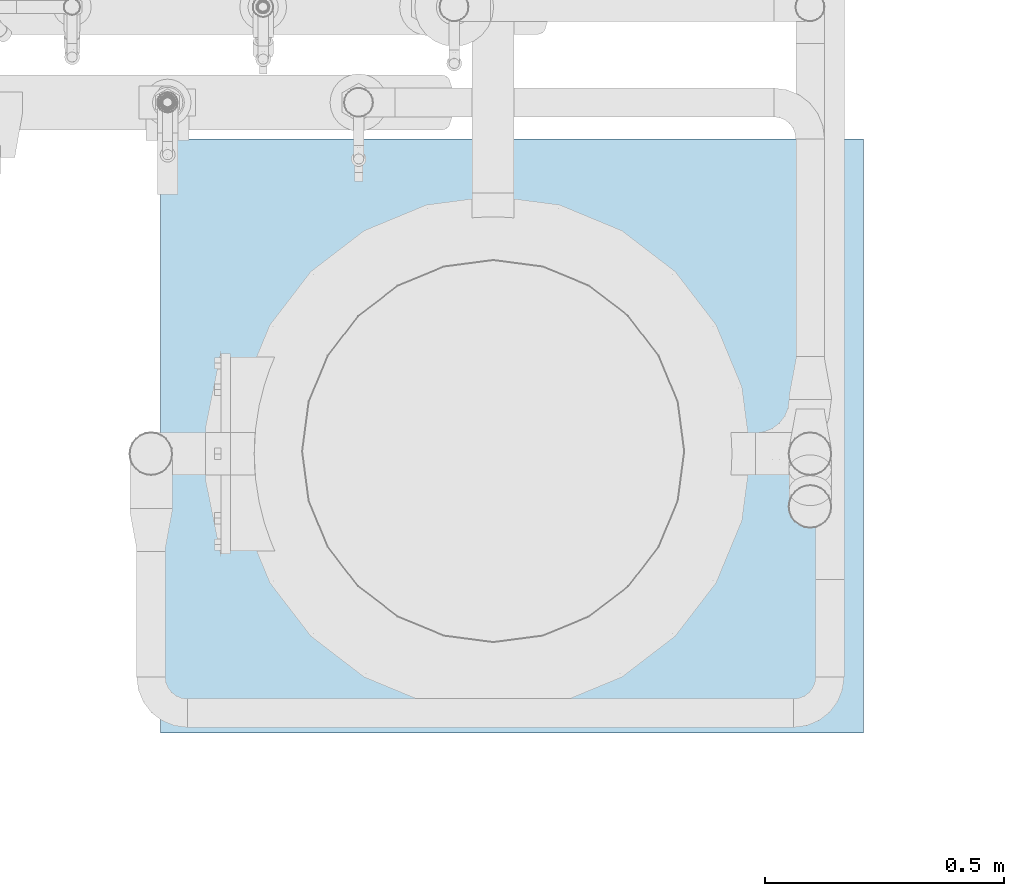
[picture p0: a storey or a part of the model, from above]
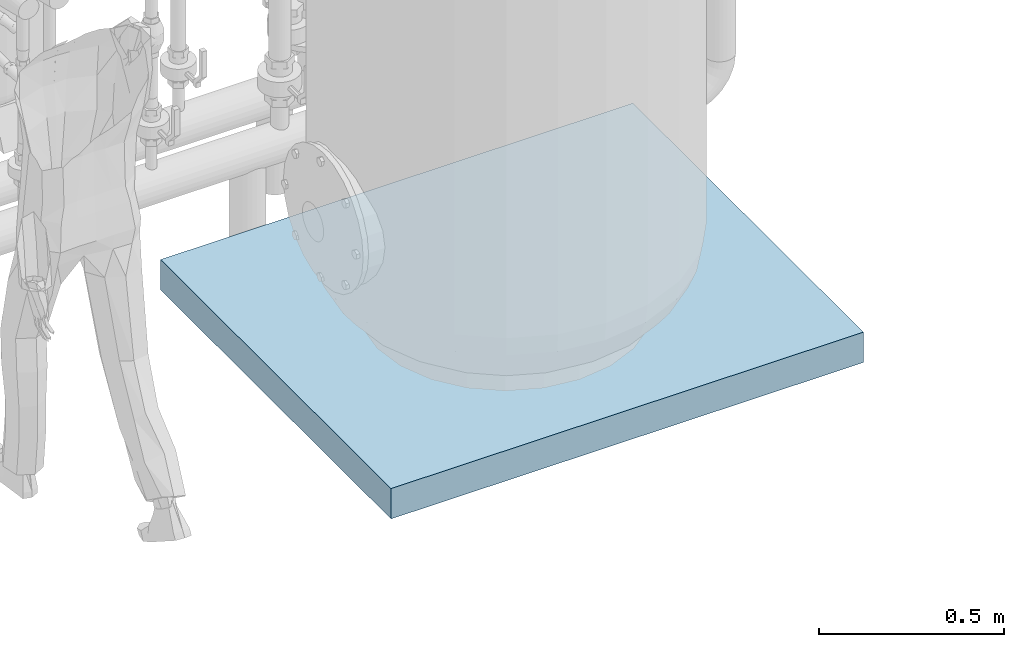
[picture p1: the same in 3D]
Properties of the parts of a building model (IFC2X3), part 1 of 4

# File
Description: ViewDefinition [CoordinationView_V2.0]
File name: Plancal nova.ifc
Time: 2015-04-08T17:33:02+02:00
Written by: Plancal nova (Build = 11.0.0.7, Compile = Apr 1 2015)
Made in: Plancal nova (Build = 11.0.0.7, Compile = Apr 1 2015)

# IfcSite, Site 1
RefLatitude: 50, 43, 8; RefLongitude: 7, 8, 56; RefElevation: 60 m

# IfcBuildingStorey (6)
In: Undefined
Name | Elevation (m)

Toiture | 17.4
R+2 | 13.45
Mezzannine | 9.425
R+1 | 5.4
Rez de chaussŽe | 0

# IfcBuildingElementProxy (54)
Name | In | Description | Group
BuildingElementProxy 1 | Toiture | Cube | Géométrie
BuildingElementProxy 2 | R+2 | Cloison
BuildingElementProxy 3 | R+2 | Cloison
BuildingElementProxy 4 | R+2 | Cloison
BuildingElementProxy 5 | R+2 | Cloison
BuildingElementProxy 6 | Mezzannine | Cloison
BuildingElementProxy 7 | Mezzannine | Cloison
BuildingElementProxy 8 | Mezzannine | Cloison
BuildingElementProxy 9 | Mezzannine | Cloison
BuildingElementProxy 10 | R+1 | Cloison
BuildingElementProxy 11 | R+1 | Cloison
BuildingElementProxy 12 | R+1 | Cloison
BuildingElementProxy 13 | R+1 | Cloison
BuildingElementProxy 14 | Rez de chaussŽe | IfcBuildingElementProxy | Géométrie
BuildingElementProxy 15 | Rez de chaussŽe | IfcBuildingElementProxy | Géométrie
BuildingElementProxy 16 | Rez de chaussŽe | IfcBuildingElementProxy | Géométrie
BuildingElementProxy 17 | Rez de chaussŽe | IfcBuildingElementProxy | Géométrie
BuildingElementProxy 18 | Rez de chaussŽe | IfcBuildingElementProxy | Géométrie
BuildingElementProxy 19 | Rez de chaussŽe | IfcBuildingElementProxy | Géométrie
BuildingElementProxy 20 | Rez de chaussŽe | IfcBuildingElementProxy | Géométrie
BuildingElementProxy 21 | Rez de chaussŽe | IfcBuildingElementProxy | Géométrie
BuildingElementProxy 22 | Rez de chaussŽe | IfcBuildingElementProxy | Géométrie
BuildingElementProxy 23 | Rez de chaussŽe | IfcBuildingElementProxy | Géométrie
BuildingElementProxy 24 | Rez de chaussŽe | IfcBuildingElementProxy | Géométrie
BuildingElementProxy 25 | Rez de chaussŽe | IfcBuildingElementProxy | Géométrie
BuildingElementProxy 26 | Rez de chaussŽe | IfcBuildingElementProxy | Géométrie
BuildingElementProxy 27 | Rez de chaussŽe | IfcBuildingElementProxy | Géométrie
BuildingElementProxy 28 | Rez de chaussŽe | IfcBuildingElementProxy | Géométrie
BuildingElementProxy 29 | Rez de chaussŽe | IfcBuildingElementProxy | Géométrie
BuildingElementProxy 30 | Rez de chaussŽe | IfcBuildingElementProxy | Géométrie
BuildingElementProxy 31 | Rez de chaussŽe | IfcBuildingElementProxy | Géométrie
BuildingElementProxy 32 | Rez de chaussŽe | IfcBuildingElementProxy | Géométrie
BuildingElementProxy 33 | Rez de chaussŽe | IfcBuildingElementProxy | Géométrie
BuildingElementProxy 34 | Rez de chaussŽe | IfcBuildingElementProxy | Géométrie
BuildingElementProxy 35 | Rez de chaussŽe | IfcBuildingElementProxy | Géométrie
BuildingElementProxy 36 | Rez de chaussŽe | IfcBuildingElementProxy | Géométrie
BuildingElementProxy 37 | Rez de chaussŽe | IfcBuildingElementProxy | Géométrie
BuildingElementProxy 38 | Rez de chaussŽe | IfcBuildingElementProxy | Géométrie
BuildingElementProxy 39 | Rez de chaussŽe | IfcBuildingElementProxy | Géométrie
BuildingElementProxy 40 | Rez de chaussŽe | IfcBuildingElementProxy | Géométrie
BuildingElementProxy 41 | Rez de chaussŽe | IfcBuildingElementProxy | Géométrie
BuildingElementProxy 42 | Rez de chaussŽe | IfcBuildingElementProxy | Géométrie
BuildingElementProxy 43 | Rez de chaussŽe | IfcBuildingElementProxy | Géométrie
BuildingElementProxy 44 | Rez de chaussŽe | IfcBuildingElementProxy | Géométrie
BuildingElementProxy 45 | Rez de chaussŽe | IfcBuildingElementProxy | Géométrie
BuildingElementProxy 46 | Rez de chaussŽe | IfcBuildingElementProxy | Géométrie
BuildingElementProxy 47 | Rez de chaussŽe | IfcBuildingElementProxy | Géométrie
BuildingElementProxy 48 | Rez de chaussŽe | IfcBuildingElementProxy | Géométrie
BuildingElementProxy 49 | Rez de chaussŽe | IfcBuildingElementProxy | Géométrie
BuildingElementProxy 50 | Rez de chaussŽe | IfcBuildingElementProxy | Géométrie
BuildingElementProxy 51 | Rez de chaussŽe | Cloison
BuildingElementProxy 52 | Rez de chaussŽe | Cloison
BuildingElementProxy 53 | Rez de chaussŽe | Cloison
BuildingElementProxy 54 | Rez de chaussŽe | Cloison

# IfcDistributionControlElement: Compteur d'eau (3)
In: Rez de chaussŽe
Description: Compteur d'eau
Pset Plancal nova - MEP - Tech-Type de connection (filetage=2, bride=3): 3; Nom: Compteur d'eau; Tech-PN: 16; Tech-Epaisseur isolant (m): 0 m
Name | Geom-Ø exterieur (m) (m) | Geom-DN | Geom-Longueur (m) (m) | Group
Compteur d'eau | 0.185 | 65 | 0.185 | Eau froide
Compteur d'eau | 0.105 | 20 | 0.13 | Aller
Compteur d'eau | 0.115 | 25 | 0.13 | Aller

# IfcDistributionControlElement: Thermomètre droit (12)
In: Rez de chaussŽe
Description: Thermomètre droit
Pset Plancal nova - MEP - Nom: Thermomètre droit; Tech-Epaisseur isolant (m): 0 m
Name | Group
6 x Thermomètre droit | Aller
6 x Thermomètre droit | Retour

# IfcDistributionControlElement: Thermomètre droit ind. horloge
In: Rez de chaussŽe
Description: Thermomètre droit ind. horloge; Group: Retour
Pset Plancal nova - MEP - Nom: Thermomètre droit ind. horloge; Tech-Epaisseur isolant (m): 0 m

# IfcDistributionElement: Angle (7)
Description: Angle; Group: Medium
Pset Plancal nova - MEP - Geom-Côte 1 (m): 0.08 m; Info: CDC d'installation; Nom: Angle; Geom-Angle (gauche) (°): 90 rad
Name | In | Geom-Côte 2 (m) (m)
2 x Angle | R+2 | 0.4
Angle | R+1 | 0.6
2 x Angle | Rez de chaussŽe | 0.4
2 x Angle | Rez de chaussŽe | 0.6

# IfcDistributionElement: Chemin(s) de câbles (229)
Description: Chemin(s) de câbles; Group: Medium
Pset Plancal nova - MEP - Geom-Côte 1 (m): 0.08 m; Info: CDC d'installation; Nom: Chemin(s) de câbles
Name | In | Geom-Côte 2 (m) (m) | Geom-Longueur (m) (m)
Chemin(s) de câbles | R+2 | 0.6 | 2.89034
17 x Chemin(s) de câbles | R+2 | 0.6 | 3
6 x Chemin(s) de câbles | R+2 | 0.4 | 0.57
Chemin(s) de câbles | R+2 | 0.6 | 1.03241
Chemin(s) de câbles | R+2 | 0.4 | 0.943808
5 x Chemin(s) de câbles | R+2 | 0.4 | 3
3 x Chemin(s) de câbles | R+2 | 0.4 | 0.239526
Chemin(s) de câbles | R+2 | 0.6 | 2.85
Chemin(s) de câbles | R+2 | 0.4 | 2.47819
Chemin(s) de câbles | R+2 | 0.4 | 2.9178
Chemin(s) de câbles | R+2 | 0.6 | 2.65
Chemin(s) de câbles | R+2 | 0.4 | 0.818883
Chemin(s) de câbles | R+2 | 0.4 | 2.54668
Chemin(s) de câbles | R+2 | 0.4 | 1.85332
Chemin(s) de câbles | R+2 | 0.4 | 2.05628
Chemin(s) de câbles | R+2 | 0.4 | 0.321721
Chemin(s) de câbles | R+2 | 0.6 | 2
Chemin(s) de câbles | R+2 | 0.6 | 0.636449
Chemin(s) de câbles | R+2 | 0.6 | 0.175401
Chemin(s) de câbles | R+2 | 0.6 | 0.564941
Chemin(s) de câbles | R+2 | 0.4 | 0.974952
2 x Chemin(s) de câbles | R+2 | 0.4 | 0.108728
Chemin(s) de câbles | R+2 | 0.4 | 0.503318
Chemin(s) de câbles | R+2 | 0.4 | 1.96584
Chemin(s) de câbles | R+2 | 0.6 | 1.20888
Chemin(s) de câbles | R+2 | 0.4 | 0.977718
2 x Chemin(s) de câbles | R+2 | 0.4 | 0.17756
Chemin(s) de câbles | R+2 | 0.4 | 2.1746
Chemin(s) de câbles | R+2 | 0.4 | 1.61629
Chemin(s) de câbles | R+2 | 0.4 | 1.37933
Chemin(s) de câbles | R+2 | 0.4 | 1.18202
Chemin(s) de câbles | R+2 | 0.4 | 0.250378
18 x Chemin(s) de câbles | Mezzannine | 0.6 | 3
Chemin(s) de câbles | Mezzannine | 0.6 | 2.89034
Chemin(s) de câbles | Mezzannine | 0.6 | 0.324264
2 x Chemin(s) de câbles | Mezzannine | 0.4 | 0.19664
Chemin(s) de câbles | Mezzannine | 0.4 | 0.14602
Chemin(s) de câbles | Mezzannine | 0.6 | 1.03241
9 x Chemin(s) de câbles | Mezzannine | 0.4 | 3
Chemin(s) de câbles | Mezzannine | 0.6 | 0.931529
Chemin(s) de câbles | Mezzannine | 0.6 | 2.85
Chemin(s) de câbles | Mezzannine | 0.6 | 2.65
Chemin(s) de câbles | Mezzannine | 0.4 | 0.818883
4 x Chemin(s) de câbles | Mezzannine | 0.4 | 0.57
2 x Chemin(s) de câbles | Mezzannine | 0.4 | 2.2
2 x Chemin(s) de câbles | Mezzannine | 0.4 | 0.239526
Chemin(s) de câbles | Mezzannine | 0.4 | 0.943808
Chemin(s) de câbles | Mezzannine | 0.4 | 2.9178
Chemin(s) de câbles | Mezzannine | 0.4 | 1.4642
Chemin(s) de câbles | Mezzannine | 0.6 | 1.35025
Chemin(s) de câbles | Mezzannine | 0.4 | 0.978
Chemin(s) de câbles | Mezzannine | 0.4 | 2.47819
Chemin(s) de câbles | Mezzannine | 0.6 | 0.772425
2 x Chemin(s) de câbles | Mezzannine | 0.4 | 0.484968
Chemin(s) de câbles | Mezzannine | 0.4 | 0.388981
Chemin(s) de câbles | Mezzannine | 0.4 | 0.475627
Chemin(s) de câbles | Mezzannine | 0.4 | 1.5
Chemin(s) de câbles | R+1 | 0.6 | 1.03241
Chemin(s) de câbles | R+1 | 0.6 | 2.89034
Chemin(s) de câbles | R+1 | 0.6 | 0.324264
Chemin(s) de câbles | R+1 | 0.6 | 0.372253
9 x Chemin(s) de câbles | R+1 | 0.6 | 3
Chemin(s) de câbles | R+1 | 0.6 | 2.025
Chemin(s) de câbles | R+1 | 0.4 | 0.486201
2 x Chemin(s) de câbles | R+1 | 0.4 | 0.19664
Chemin(s) de câbles | R+1 | 0.4 | 0.14602
18 x Chemin(s) de câbles | R+1 | 0.4 | 3
Chemin(s) de câbles | R+1 | 0.4 | 2.125
Chemin(s) de câbles | R+1 | 0.4 | 1.98413
4 x Chemin(s) de câbles | R+1 | 0.4 | 0.57
Chemin(s) de câbles | R+1 | 0.6 | 0.443752
Chemin(s) de câbles | R+1 | 0.4 | 1.5733
Chemin(s) de câbles | R+1 | 0.4 | 0.541421
Chemin(s) de câbles | R+1 | 0.4 | 1.96584
Chemin(s) de câbles | R+1 | 0.4 | 0.735506
Chemin(s) de câbles | R+1 | 0.4 | 2.291
Chemin(s) de câbles | R+1 | 0.4 | 1.48875
Chemin(s) de câbles | R+1 | 0.4 | 0.127835
Chemin(s) de câbles | R+1 | 0.4 | 2.31888
Chemin(s) de câbles | R+1 | 0.4 | 0.290161
Chemin(s) de câbles | R+1 | 0.4 | 2.65509
Chemin(s) de câbles | R+1 | 0.4 | 1.40586
Chemin(s) de câbles | R+1 | 0.4 | 0.1925
Chemin(s) de câbles | R+1 | 0.4 | 1.13405
Chemin(s) de câbles | R+1 | 0.4 | 2.89846
Chemin(s) de câbles | Rez de chaussŽe | 0.4 | 1.44436
21 x Chemin(s) de câbles | Rez de chaussŽe | 0.4 | 3
Chemin(s) de câbles | Rez de chaussŽe | 0.4 | 0.398976
Chemin(s) de câbles | Rez de chaussŽe | 0.4 | 1.96335
Chemin(s) de câbles | Rez de chaussŽe | 0.4 | 1.83191
Chemin(s) de câbles | Rez de chaussŽe | 0.4 | 2.10462
Chemin(s) de câbles | Rez de chaussŽe | 0.4 | 0.95
Chemin(s) de câbles | Rez de chaussŽe | 0.4 | 1.55
Chemin(s) de câbles | Rez de chaussŽe | 0.3 | 3
Chemin(s) de câbles | Rez de chaussŽe | 0.3 | 2.5
9 x Chemin(s) de câbles | Rez de chaussŽe | 0.6 | 3
Chemin(s) de câbles | Rez de chaussŽe | 0.6 | 0.415136
Chemin(s) de câbles | Rez de chaussŽe | 0.6 | 1.4
Chemin(s) de câbles | Rez de chaussŽe | 0.6 | 2.30191
Chemin(s) de câbles | Rez de chaussŽe | 0.4 | 1.49536
Chemin(s) de câbles | Rez de chaussŽe | 0.6 | 1.058
Chemin(s) de câbles | Rez de chaussŽe | 0.6 | 2.31727
Chemin(s) de câbles | Rez de chaussŽe | 0.4 | 1.73463
Chemin(s) de câbles | Rez de chaussŽe | 0.4 | 1.33737
2 x Chemin(s) de câbles | Rez de chaussŽe | 0.4 | 2.9
Chemin(s) de câbles | Rez de chaussŽe | 0.6 | 1.35
Chemin(s) de câbles | Rez de chaussŽe | 0.4 | 2.40002
Chemin(s) de câbles | Rez de chaussŽe | 0.6 | 0.816972
2 x Chemin(s) de câbles | Rez de chaussŽe | 0.4 | 2.18303

# IfcDistributionElement: Connecteur articulé vertical Descendant (26)
Description: Connecteur articulé vertical Descendant; Group: Medium
Pset Plancal nova - MEP - Geom-Côte 1 (m): 0.08 m; Info: CDC d'installation; Nom: Connecteur articulé vertical Descendant
Name | In | Geom-Côte 2 (m) (m) | Geom-Angle (°) (rad)
6 x Connecteur articulé vertical Descendant | R+2 | 0.4 | 30
4 x Connecteur articulé vertical Descendant | Mezzannine | 0.4 | 45
Connecteur articulé vertical Descendant | Mezzannine | 0.6 | 45
4 x Connecteur articulé vertical Descendant | Mezzannine | 0.4 | 30
Connecteur articulé vertical Descendant | R+1 | 0.6 | 45
2 x Connecteur articulé vertical Descendant | R+1 | 0.4 | 45
7 x Connecteur articulé vertical Descendant | R+1 | 0.4 | 30
Connecteur articulé vertical Descendant | R+1 | 0.4 | 90

# IfcDistributionElement: Connecteur articulé vertical Montant (20)
Description: Connecteur articulé vertical Montant; Group: Medium
Pset Plancal nova - MEP - Geom-Côte 1 (m): 0.08 m; Info: CDC d'installation; Nom: Connecteur articulé vertical Montant
Name | In | Geom-Côte 2 (m) (m) | Geom-Angle (°) (rad)
6 x Connecteur articulé vertical Montant | R+2 | 0.4 | 30
4 x Connecteur articulé vertical Montant | Mezzannine | 0.4 | 45
Connecteur articulé vertical Montant | Mezzannine | 0.6 | 45
4 x Connecteur articulé vertical Montant | Mezzannine | 0.4 | 30
Connecteur articulé vertical Montant | R+1 | 0.6 | 45
2 x Connecteur articulé vertical Montant | R+1 | 0.4 | 45
Connecteur articulé vertical Montant | R+1 | 0.4 | 30
Connecteur articulé vertical Montant | R+1 | 0.4 | 90

# IfcDistributionElement: Coude (7)
In: R+1
Description: Coude; Group: Medium
Pset Plancal nova - MEP - Geom-Côte 1 (m): 0.08 m; Geom-Côte 2 (m): 0.4 m; Info: CDC d'installation; Nom: Coude
Name | Geom-Angle (°) (rad)
2 x Coude | 45
2 x Coude | 49
2 x Coude | 90
Coude | 82.4

# IfcDistributionElement: Coude vertical 2 parties Descendant (7)
In: R+2
Description: Coude vertical 2 parties Descendant; Group: Medium
Pset Plancal nova - MEP - Geom-Côte 1 (m): 0.08 m; Info: CDC d'installation; Nom: Coude vertical 2 parties Descendant; Geom-Angle (°): 45 rad
Name | Geom-Côte 2 (m) (m)
Coude vertical 2 parties Descendant | 0.6
6 x Coude vertical 2 parties Descendant | 0.4

# IfcDistributionElement: Coude vertical 2 parties Montant (7)
In: R+2
Description: Coude vertical 2 parties Montant; Group: Medium
Pset Plancal nova - MEP - Geom-Côte 1 (m): 0.08 m; Info: CDC d'installation; Nom: Coude vertical 2 parties Montant; Geom-Angle (°): 45 rad
Name | Geom-Côte 2 (m) (m)
Coude vertical 2 parties Montant | 0.6
6 x Coude vertical 2 parties Montant | 0.4

# IfcDistributionElement: Croisement (2)
Description: Croisement; Group: Medium
Pset Plancal nova - MEP - Geom-Côte 1 (m): 0.08 m; Geom-Côte 2 (m): 0.6 m; Info: CDC d'installation; Nom: Croisement; Geom-Longueur suppl (m): 0.05 m
Name | In
Croisement | R+2
Croisement | Mezzannine

# IfcDistributionElement: Decken-Rechteckleuchte mit Rahmen AP (607)
Description: IfcDistributionElement; Group: Luminaires
Pset Plancal nova - MEP - Description: Decken-Rechteckleuchte mit Rahmen AP; Tech-Hauteur de montage (m): 0.15 m; Calc-Puissance nominale (W): 100 W; Code de reperage: E; Calc-Voltage (V): 230 V
Name | In
185 x Decken-Rechteckleuchte mit Rahmen AP | R+2
184 x Decken-Rechteckleuchte mit Rahmen AP | Mezzannine
89 x Decken-Rechteckleuchte mit Rahmen AP | R+1
149 x Decken-Rechteckleuchte mit Rahmen AP | Rez de chaussŽe

# IfcDistributionElement: Einbau-Downlight, 1-flammig (12)
Description: IfcDistributionElement; Group: Luminaires
Pset Plancal nova - MEP - Description: Einbau-Downlight, 1-flammig; Tech-Hauteur de montage (m): 0 m; Calc-Puissance nominale (W): 100 W; Code de reperage: E; Calc-Voltage (V): 230 V
Name | In
3 x Einbau-Downlight, 1-flammig | R+2
3 x Einbau-Downlight, 1-flammig | Mezzannine
3 x Einbau-Downlight, 1-flammig | R+1
3 x Einbau-Downlight, 1-flammig | Rez de chaussŽe

# IfcDistributionElement: Entonnoir, axial (4)
Description: Entonnoir, axial; Group: Medium
Pset Plancal nova - MEP - Geom-Côte 1 (m): 0.08 m; Geom-Côte 2 (m): 0.6 m; Info: CDC d'installation; Nom: Entonnoir, axial
Name | In | Geom-Longueur (m) (m)
Entonnoir, axial | R+2 | 0.34
Entonnoir, axial | Mezzannine | 0.34
Entonnoir, axial | R+1 | 0.34
Entonnoir, axial | Rez de chaussŽe | 0.58

# IfcDistributionElement: HAK (4)
Description: IfcDistributionElement; Group: Courant fort
Pset Plancal nova - MEP - Geom-Largeur (m): 2.8 m; Description: HAK; Geom-Description fonctionnelle: HAK; Geom-Hauteur (m): 2 m; Geom-Hauteur de montage (m): 0 m; Geom-Profondeur (m): 0.4 m
Name | In
HAK | R+2
HAK | Mezzannine
HAK | R+1
HAK | Rez de chaussŽe

# IfcDistributionElement: Pièce en té (10)
Description: Pièce en té; Group: Medium
Pset Plancal nova - MEP - Geom-Epaisseur (m): 0.08 m; Info: CDC d'installation; Nom: Pièce en té; Geom-Longueur suppl (m): 0.05 m
Name | In | Geom-côte 1 (m) (m) = Geom-côte 2 (m) (m) | Geom-Debordement largeur (m) (m)
Pièce en té | R+2 | 0.4 | 0.6
Pièce en té | R+2 | 0.6 | 0.6
Pièce en té | Mezzannine | 0.4 | 0.6
Pièce en té | Mezzannine | 0.6 | 0.6
Pièce en té | R+1 | 0.6 | 0.6
Pièce en té | R+1 | 0.4 | 0.6
2 x Pièce en té | Rez de chaussŽe | 0.4 | 0.6
Pièce en té | Rez de chaussŽe | 0.4 | 0.3
Pièce en té | Rez de chaussŽe | 0.6 | 0.6

# IfcDistributionElement: Réduction
In: R+1
Description: Réduction; Group: Medium
Pset Plancal nova - MEP - Geom-Côte 1 (m): 0.08 m; Geom-Côte 2 (m): 0.6 m; Info: CDC d'installation; Nom: Réduction; Geom-Longueur 1 (m): 0.05 m; Geom-Longueur 2 (m): 0.05 m

# IfcDistributionElement: T5 1-flammig 21W (8)
Description: IfcDistributionElement; Group: Luminaires
Pset Plancal nova - MEP - Description: T5 1-flammig 21W; Tech-Hauteur de montage (m): -0.1 m; Calc-Puissance nominale (W): 2.1 W; Code de reperage: E; Calc-Voltage (V): 230 V
Name | In
2 x T5 1-flammig 21W | R+2
2 x T5 1-flammig 21W | Mezzannine
2 x T5 1-flammig 21W | R+1
2 x T5 1-flammig 21W | Rez de chaussŽe

# IfcDistributionFlowElement: Chambre de répartition (4)
In: Toiture
Description: Chambre de répartition; Group: Climatiseur
Pset Plancal nova - MEP - Geom-Largeur (m): 1.5 m; Nom: Chambre de répartition; Geom-Hauteur (m): 1.4 m; Geom-Longueur (m): 3 m; Tech-Fluide: V_Air_soufflé

# IfcDistributionFlowElement: Socle pour appareil/centrale (2)
In: Toiture
Description: Socle pour appareil/centrale; Group: Climatiseur
Pset Plancal nova - MEP - Geom-Largeur (m): 1.5 m; Nom: Socle pour appareil/centrale; Geom-Hauteur (m): 0.2 m; Geom-Longueur (m): 3 m; Tech-Fluide: V_Air_soufflé

# IfcFlowController: Clapet coupe-feu rect. (12)
Description: Clapet coupe-feu rect.; Group: CCF
Pset Plancal nova - MEP - Nom: Clapet coupe-feu rect.; Abbreviation: CCFR; Geom-Longueur (m): 0.5 m; Tech-Epaisseur isolant (m): 0 m; Calc-Zeta: 2
Name | In | Geom-Côte 1 (m) (m) | Geom-Côte 2 (m) (m) | Tech-Fluide
Clapet coupe-feu rect. | R+2 | 0.5 | 0.5 | V_Air_soufflé
Clapet coupe-feu rect. | R+2 | 0.45 | 0.45 | V_Air_soufflé
2 x Clapet coupe-feu rect. | R+2 | 0.8 | 0.5 | V_Air_extrait
Clapet coupe-feu rect. | R+2 | 0.5 | 0.5 | V_Air_extrait
Clapet coupe-feu rect. | R+2 | 0.6 | 0.5 | V_Air_soufflé
Clapet coupe-feu rect. | R+2 | 0.9 | 0.5 | V_Air_extrait
Clapet coupe-feu rect. | Mezzannine | 0.5 | 0.5 | V_Air_soufflé
Clapet coupe-feu rect. | Mezzannine | 0.45 | 0.45 | V_Air_soufflé
Clapet coupe-feu rect. | Mezzannine | 0.8 | 0.5 | V_Air_extrait
Clapet coupe-feu rect. | Mezzannine | 0.5 | 0.5 | V_Air_extrait
Clapet coupe-feu rect. | Mezzannine | 0.9 | 0.5 | V_Air_extrait

# IfcFlowController: Clapet de retenue (5)
In: Rez de chaussŽe
Description: Clapet de retenue
Pset Plancal nova - MEP - Tech-Type de connection (filetage=2, bride=3): 3; Nom: Clapet de retenue; Tech-PN: 16; Tech-Epaisseur isolant (m): 0 m
Name | Geom-Ø exterieur (m) (m) | Geom-DN | Geom-Longueur (m) (m) | Group
Clapet de retenue | 0.185 | 65 | 0.185 | Eau froide
Clapet de retenue | 0.15 | 40 | 0.13 | Aller
2 x Clapet de retenue | 0.115 | 25 | 0.105 | Aller
Clapet de retenue | 0.14 | 32 | 0.12 | Aller

# IfcFlowController: Clapet de réglage cylindrique (13)
Description: Clapet de réglage cylindrique; Group: Elément
Pset Plancal nova - MEP - Nom: Clapet de réglage cylindrique; Abbreviation: DKE; Geom-Longueur (m): 0.5 m; Tech-Epaisseur isolant (m): 0 m; Calc-Zeta: 0.05
Name | In | Geom-Ø (m) (m) | Calc-Perte de charge (Pa) (Pa) | Calc-Valeur d'equilibrage (Pa) (Pa) | Tech-Fluide
Clapet de réglage cylindrique | R+1 | 0.25 | 0.345843 | 107.203 | V_Air_extrait
Clapet de réglage cylindrique | R+1 | 0.25 | 0.345843 | 118.299 | V_Air_extrait
Clapet de réglage cylindrique | R+1 | 0.45 | 0.527119 | 0 | V_Air_extrait
Clapet de réglage cylindrique | R+1 | 0.2 | 0.375264 | 126.714 | V_Air_extrait
Clapet de réglage cylindrique | R+1 | 0.315 | 0.747051 | 14.4965 | V_Air_soufflé
Clapet de réglage cylindrique | R+1 | 0.2 | 0.375264 | 0 | V_Air_soufflé
Clapet de réglage cylindrique | Rez de chaussŽe | 0.355 | 0.604871 | 0 | V_Air_soufflé
Clapet de réglage cylindrique | Rez de chaussŽe | 0.16 | 0.229043 | 66.7975 | V_Air_soufflé
Clapet de réglage cylindrique | Rez de chaussŽe | 0.16 | 0.229043 | 63.6076 | V_Air_soufflé
Clapet de réglage cylindrique | Rez de chaussŽe | 0.25 | 0.345843 | 133.919 | V_Air_extrait
Clapet de réglage cylindrique | Rez de chaussŽe | 0.5 | 0.614832 | 74.982 | V_Air_extrait
Clapet de réglage cylindrique | Rez de chaussŽe | 0.25 | 0.345843 | 125.034 | V_Air_extrait
Clapet de réglage cylindrique | Rez de chaussŽe | 0.45 | 0.618633 | 75.6427 | V_Air_extrait

# IfcFlowController: Clapet/registre d'équilibrage cyl. (2)
Description: Clapet/registre d'équilibrage cyl.; Group: Elément
Pset Plancal nova - MEP - Nom: Clapet/registre d'équilibrage cyl.; Abbreviation: CEC; Geom-Longueur (m): 0.3 m; Tech-Epaisseur isolant (m): 0 m; Calc-Zeta: 2
Name | In | Geom-Ø (m) (m) | Calc-Perte de charge (Pa) (Pa) | Calc-Valeur d'equilibrage (Pa) (Pa) | Tech-Fluide
Clapet/registre d'équilibrage cyl. | R+2 | 0.45 | 28.6987 | 31.3517 | V_Air_extrait
Clapet/registre d'équilibrage cyl. | R+1 | 0.16 | 22 | 0 | V_Air_soufflé

# IfcFlowController: Clapet/registre rect.
In: R+2
Description: Clapet/registre rect.; Group: Elément
Pset Plancal nova - MEP - Geom-Côte 1 (m): 0.5 m; Geom-Côte 2 (m): 0.5 m; Nom: Clapet/registre rect.; Abbreviation: RER; Geom-Longueur (m): 0.18 m; Tech-Fluide: V_Air_extrait; Tech-Epaisseur isolant (m): 0 m; Calc-Zeta: 2

# IfcFlowController: Robinet à boisseau
In: Rez de chaussŽe
Description: Robinet à boisseau; Group: Retour
Pset Plancal nova - MEP - Tech-Type de connection (filetage=2, bride=3): 3; Nom: Robinet à boisseau; Geom-Ø exterieur (m): 0.095 m; Geom-DN: 15; Geom-Longueur (m): 0.055 m; Tech-PN: 16; Tech-Epaisseur isolant (m): 0 m

# IfcFlowController: Robinet à boisseau sphér. DN 32 (3)
In: Rez de chaussŽe
Description: Robinet à boisseau sphér. DN 32
Pset Plancal nova - MEP - Tech-Type de connection (filetage=2, bride=3): 3; Nom: Robinet à boisseau sphér. DN 32; Geom-Longueur (m): 0.078 m; Tech-PN: 16; Tech-Epaisseur isolant (m): 0 m
Name | Geom-Ø exterieur (m) (m) | Geom-DN | Group
2 x Robinet à boisseau sphér. DN 32 | 0.14 | 32 | Aller
Robinet à boisseau sphér. DN 32 | 0.15 | 40 | Eau chaude

# IfcFlowController: Robinet à boisseau sphérique (23)
In: Rez de chaussŽe
Description: Robinet à boisseau sphérique
Pset Plancal nova - MEP - Tech-Type de connection (filetage=2, bride=3): 3; Nom: Robinet à boisseau sphérique; Tech-PN: 16
Name | Geom-Ø exterieur (m) (m) | Geom-DN | Geom-Longueur (m) (m) | Tech-Epaisseur isolant (m) (m) | Group
Robinet à boisseau sphérique | 0.185 | 65 | 0.185 | 0 | Eau froide
4 x Robinet à boisseau sphérique | 0.115 | 25 | 0.105 | 0 | Aller
2 x Robinet à boisseau sphérique | 0.14 | 32 | 0.12 | 0 | Eau froide
Robinet à boisseau sphérique | 0.14 | 32 | 0.12 | 0 | Retour
2 x Robinet à boisseau sphérique | 0.105 | 20 | 0.095 | 0 | Aller
2 x Robinet à boisseau sphérique | 0.115 | 25 | 0.105 | 0 | Retour
2 x Robinet à boisseau sphérique | 0.14 | 32 | 0.12 | 0 | Aller
Robinet à boisseau sphérique | 0.095 | 15 | 0.09 | 0 | Retour
2 x Robinet à boisseau sphérique | 0.15 | 40 | 0.13 | 0 | Aller
Robinet à boisseau sphérique | 0.15 | 40 | 0.13 | 0 | Retour
Robinet à boisseau sphérique | 0.105 | 20 | 0.095 | 0 | Retour
Robinet à boisseau sphérique | 0.095 | 15 | 0.09 | 0 | Aller
Robinet à boisseau sphérique | 0.165 | 50 | 0.15 | 0 | Aller
Robinet à boisseau sphérique | 0.165 | 50 | 0.15 | 0.02 | Retour
Robinet à boisseau sphérique | 0.115 | 25 | 0.105 | 0 | Eau froide

# IfcFlowController: Vanne 3 voies (4)
In: Rez de chaussŽe
Description: Vanne 3 voies
Pset Plancal nova - MEP - Tech-Type de connection (filetage=2, bride=3): 3; Nom: Vanne 3 voies; Tech-PN: 16; Tech-Epaisseur isolant (m): 0 m
Name | Geom-Ø exterieur (m) (m) | Geom-DN | Group
2 x Vanne 3 voies | 0.105 | 20 | Aller
Vanne 3 voies | 0.14 | 32 | Aller
Vanne 3 voies | 0.14 | 32 | Retour

# IfcFlowController: Vanne papillon (2)
In: Rez de chaussŽe
Description: Vanne papillon; Group: Retour
Pset Plancal nova - MEP - Tech-Type de connection (filetage=2, bride=3): 2; Nom: Vanne papillon; Geom-DN: 50; Geom-Longueur (m): 0.043 m; Tech-PN: 16
Name | Tech-Epaisseur isolant (m) (m)
Vanne papillon | 0
Vanne papillon | 0.02

# IfcFlowFitting: Bride (8)
In: Rez de chaussŽe
Description: Bride
Pset Plancal nova - MEP - Nom: Bride; Tech-PN: 16
Name | Geom-Ø exterieur (m) (m) | Geom-DN | Geom-Depth (m) | Tech-Epaisseur isolant (m) (m) | Group | Tech-Material
Bride | 0.42 | 400 | 0.052 | 0 | Medium
Bride | 0.125 | 50 | 0.045 | 0 | Retour | Selon DIN 2627
Bride | 0.125 | 50 | 0.045 | 0.02 | Retour | Selon DIN 2627
3 x Bride | 0.165 | 50 | 0.045 | 0.02 | Retour | Selon DIN 2627
2 x Bride | 0.165 | 50 | 0.045 | 0 | Retour | Selon DIN 2627

# IfcFlowFitting: Contre-coude
In: R+1
Description: Contre-coude; Group: Air extrait
Pset Plancal nova - MEP - Nom: Contre-coude; Geom-Ø principal (m): 0.2 m; Abbreviation: R-ETB; Geom-Longueur (m): 0.403849 m; Geom-Ecart (m): 0.00384941 m; Tech-Fluide: V_Air_extrait; Tech-Materiel (ID): 1; Tech-Epaisseur isolant (m): 0 m

# IfcFlowFitting: Coude (161)
Description: Coude
Pset Plancal nova - MEP - Nom: Coude; Abbreviation: BGE; Tech-Materiel (ID): 1; Tech-Epaisseur isolant (m): 0 m
Name | In | Geom-Ø (m) (m) = Geom-Rayon de courbure (m) | Calc-Perte de charge (Pa) (Pa) | Tech-Fluide | Geom-Surface (m2) (m2) | Geom-Angle (°) (rad) | Group
11 x Coude | R+2 | 0.16 | 1.60447 | V_Air_extrait | 0.166543 | 90 | Air extrait
Coude | R+2 | 0.25 | 2.25817 | V_Air_extrait | 0.402673 | 90 | Air extrait
Coude | R+2 | 0.4 | 3.57272 | V_Air_extrait | 0.99063 | 90 | Air extrait
Coude | R+2 | 0.4 | 2.8939 | V_Air_extrait | 0.99063 | 90 | Air extrait
4 x Coude | R+2 | 0.355 | 3.74923 | V_Air_extrait | 0.75574 | 90 | Air extrait
Coude | R+2 | 0.315 | 2.40408 | V_Air_soufflé | 0.608408 | 90 | Air soufflé
4 x Coude | R+2 | 0.16 | 1.60447 | V_Air_soufflé | 0.166543 | 90 | Air soufflé
Coude | R+2 | 0.25 | 2.25817 | V_Air_soufflé | 0.402673 | 90 | Air soufflé
Coude | R+2 | 0.2 | 2.5364 | V_Air_soufflé | 0.247658 | 90 | Air soufflé
Coude | R+2 | 0.25 |  | V_Air_extrait | 0.402673 | 90 | Air extrait
3 x Coude | Mezzannine | 0.16 | 1.60447 | V_Air_soufflé | 0.166543 | 90 | Air soufflé
Coude | Mezzannine | 0.315 | 3.46187 | V_Air_soufflé | 0.36358 | 45 | Air soufflé
Coude | Mezzannine | 0.315 | 4.71199 | V_Air_soufflé | 0.608408 | 90 | Air soufflé
Coude | Mezzannine | 0.2 | 2.5364 | V_Air_soufflé | 0.247658 | 90 | Air soufflé
5 x Coude | Mezzannine | 0.16 | 1.60447 | V_Air_extrait | 0.166543 | 90 | Air extrait
2 x Coude | Mezzannine | 0.315 | 4.71199 | V_Air_extrait | 0.36358 | 45 | Air extrait
Coude | Mezzannine | 0.25 | 1.00363 | V_Air_extrait | 0.402673 | 90 | Air extrait
Coude | Mezzannine | 0.315 |  | V_Air_soufflé | 0.36358 | 45 | Air soufflé
4 x Coude | Mezzannine | 0.16 | 2.5364 | V_Air_soufflé | 0.103378 | 45 | Air soufflé
2 x Coude | Mezzannine | 0.16 | 2.5364 | V_Air_soufflé | 0.166543 | 90 | Air soufflé
4 x Coude | Mezzannine | 0.16 | 1.00363 | V_Air_extrait | 0.103378 | 45 | Air extrait
3 x Coude | Mezzannine | 0.16 | 1.60447 | V_Air_extrait | 0.103378 | 45 | Air extrait
2 x Coude | R+1 | 0.25 | 2.25817 | V_Air_extrait | 0.402673 | 90 | Air extrait
6 x Coude | R+1 | 0.16 | 1.60447 | V_Air_extrait | 0.166543 | 90 | Air extrait
Coude | R+1 | 0.2 | 2.5364 | V_Air_extrait | 0.247658 | 90 | Air extrait
Coude | R+1 | 0.315 | 2.40408 | V_Air_extrait | 0.160101 | 7.6 | Air extrait
2 x Coude | R+1 | 0.16 | 1.60447 | V_Air_soufflé | 0.166543 | 90 | Air soufflé
Coude | R+1 | 0.315 | 4.71199 | V_Air_soufflé | 0.608408 | 90 | Air soufflé
Coude | R+1 | 0.2 | 2.5364 | V_Air_soufflé | 0.247658 | 90 | Air soufflé
6 x Coude | R+1 | 0.315 | 1.53861 | V_Air_soufflé | 0.608408 | 90 | Air soufflé
Coude | R+1 | 0.315 | 1.53861 | V_Air_soufflé | 0.160645 | 7.7 | Air soufflé
Coude | R+1 | 0.315 | 1.53861 | V_Air_soufflé | 0.566515 | 82.3 | Air soufflé
2 x Coude | R+1 | 0.16 | 1.60447 | V_Air_soufflé | 0.103378 | 45 | Air soufflé
4 x Coude | R+1 | 0.16 |  | V_Air_extrait | 0.103378 | 45 | Air extrait
Coude | R+1 | 0.315 | 1.53861 | V_Air_extrait | 0.566515 | 82.3 | Air extrait
4 x Coude | R+1 | 0.315 | 1.53861 | V_Air_extrait | 0.608408 | 90 | Air extrait
3 x Coude | R+1 | 0.16 | 1.60447 | V_Air_extrait | 0.103378 | 45 | Air extrait
Coude | Rez de chaussŽe | 0.355 | 3.74923 | V_Air_soufflé | 0.75574 | 90 | Air soufflé
22 x Coude | Rez de chaussŽe | 0.16 | 1.60447 | V_Air_soufflé | 0.166543 | 90 | Air soufflé
Coude | Rez de chaussŽe | 0.25 | 2.25817 | V_Air_soufflé | 0.402673 | 90 | Air soufflé
2 x Coude | Rez de chaussŽe | 0.4 | 2.8939 | V_Air_soufflé | 0.595846 | 45 | Air soufflé
Coude | Rez de chaussŽe | 0.25 | 2.25817 | V_Air_extrait | 0.402673 | 90 | Air extrait
36 x Coude | Rez de chaussŽe | 0.16 | 1.60447 | V_Air_extrait | 0.166543 | 90 | Air extrait
2 x Coude | Rez de chaussŽe | 0.315 | 4.71199 | V_Air_extrait | 0.36358 | 45 | Air extrait
2 x Coude | Rez de chaussŽe | 0.16 |  | V_Air_soufflé | 0.0823227 | 30 | Air soufflé
Coude | Rez de chaussŽe | 0.16 |  | V_Air_extrait | 0.166543 | 90 | Air extrait
3 x Coude | Rez de chaussŽe | 0.16 | 1.60447 | V_Air_extrait | 0.103378 | 45 | Air extrait

# IfcFlowFitting: Coude asymétrique (5)
Description: Coude asymétrique
Pset Plancal nova - MEP - Nom: Coude asymétrique; Abbreviation: BA; Tech-Materiel (ID): 1; Geom-Rayon de courbure (m): 0.1 m; Geom-Angle (°): 90 rad; Tech-Epaisseur isolant (m): 0 m
Name | In | Geom-Epaisseur (m) (m) | Geom-Côte 1 (m) (m) | Geom-Côte 2 (m) (m) | Calc-Perte de charge (Pa) (Pa) | Tech-Poids (kg) (kg) | Tech-Fluide | Geom-Surface (m2) (m2) | Group
Coude asymétrique | Toiture | 0.9 | 0.5 | 0.6 | 3.85329 | 23.0315 | V_Air_extrait | 3.59867 | Air extrait
Coude asymétrique | Toiture | 1.3 | 1.2 | 0.5 | 4.3208 | 85.6814 | V_Air_extrait | 10.7102 | Air extrait
Coude asymétrique | Mezzannine | 0.9 | 0.5 | 0.4 | 6.31612 | 18.6812 | V_Air_extrait | 2.91894 | Air extrait
Coude asymétrique | Mezzannine | 0.55 | 0.45 | 0.4 | 2.41486 | 12.3384 | V_Air_soufflé | 1.92788 | Air soufflé
Coude asymétrique | R+1 | 0.45 | 0.45 | 0.4 | 4.25929 | 8.32842 | V_Air_soufflé | 1.73509 | Air soufflé

# IfcFlowFitting: Coude symétrique (55)
Description: Coude symétrique
Pset Plancal nova - MEP - Nom: Coude symétrique; Abbreviation: BS; Tech-Materiel (ID): 1; Geom-Rayon de courbure (m): 0.1 m; Tech-Epaisseur isolant (m): 0 m
Name | In | Geom-Epaisseur (m) (m) | Geom-Côte 1 (m) (m) = Geom-Côte 2 (m) (m) | Calc-Perte de charge (Pa) (Pa) | Tech-Poids (kg) (kg) | Tech-Fluide | Geom-Surface (m2) (m2) | Geom-Angle (°) (rad) | Group
Coude symétrique | Toiture | 0.6 | 0.9 | 2.58943 | 32.0793 | V_Air_extrait | 5.01239 | 90 | Air extrait
2 x Coude symétrique | Toiture | 1 | 0.5 | 2.91832 | 20.0156 | V_Air_soufflé | 3.12743 | 90 | Air soufflé
Coude symétrique | Toiture | 0.8 | 0.5 | 4.15339 | 17.3468 | V_Air_extrait | 2.71044 | 90 | Air extrait
Coude symétrique | Toiture | 0.6 | 0.5 | 4.40922 | 14.6781 | V_Air_soufflé | 2.29345 | 90 | Air soufflé
Coude symétrique | Toiture | 0.5 | 0.8 | 4.67209 | 25.1882 | V_Air_extrait | 3.93566 | 90 | Air extrait
Coude symétrique | Toiture | 0.5 | 0.6 | 1.58732 | 16.8898 | V_Air_soufflé | 2.63903 | 90 | Air soufflé
4 x Coude symétrique | Toiture | 1.2 | 1.3 | 0.66232 | 91.9646 | V_Air_rejeté | 11.4956 | 90 | Air rejeté
Coude symétrique | Toiture | 0.5 | 0.5 | 4.62162 | 10.0078 | V_Air_extrait | 2.08496 | 90 | Air extrait
Coude symétrique | Toiture | 0.5 | 0.5 | 2.68284 | 10.0078 | V_Air_soufflé | 2.08496 | 90 | Air soufflé
Coude symétrique | Toiture | 0.5 | 0.8 | 4.15339 | 25.1882 | V_Air_extrait | 3.93566 | 90 | Air extrait
Coude symétrique | Toiture | 1.3 | 1.2 | 0.66232 | 85.6814 | V_Air_extrait | 10.7102 | 90 | Air extrait
Coude symétrique | Toiture | 0.5 | 0.5 | 3.78323 | 10.0078 | V_Air_soufflé | 2.08496 | 90 | Air soufflé
Coude symétrique | Toiture | 0.5 | 0.6 | 4.40922 | 16.8898 | V_Air_soufflé | 2.63903 | 90 | Air soufflé
2 x Coude symétrique | R+2 | 0.5 | 0.5 | 3.78323 | 10.0078 | V_Air_extrait | 2.08496 | 90 | Air extrait
Coude symétrique | R+2 | 0.5 | 0.6 | 4.40922 | 16.8898 | V_Air_soufflé | 2.63903 | 90 | Air soufflé
Coude symétrique | R+2 | 0.6 | 0.5 | 4.40922 | 14.6781 | V_Air_soufflé | 2.29345 | 90 | Air soufflé
3 x Coude symétrique | R+2 | 0.5 | 0.5 | 3.78323 | 10.0078 | V_Air_soufflé | 2.08496 | 90 | Air soufflé
3 x Coude symétrique | R+2 | 0.45 | 0.45 | 4.25929 | 8.32842 | V_Air_soufflé | 1.73509 | 90 | Air soufflé
2 x Coude symétrique | R+2 | 0.8 | 0.5 | 4.67209 | 17.3468 | V_Air_extrait | 2.71044 | 90 | Air extrait
3 x Coude symétrique | R+2 | 0.5 | 0.5 | 4.62162 | 10.0078 | V_Air_extrait | 2.08496 | 90 | Air extrait
2 x Coude symétrique | R+2 | 0.9 | 0.5 | 3.85329 | 18.6812 | V_Air_extrait | 2.91894 | 90 | Air extrait
Coude symétrique | R+2 | 0.5 | 0.8 | 4.67209 | 25.1882 | V_Air_extrait | 3.93566 | 90 | Air extrait
3 x Coude symétrique | R+2 | 0.5 | 0.9 | 3.85329 | 29.9407 | V_Air_extrait | 4.67823 | 90 | Air extrait
Coude symétrique | R+2 | 0.5 | 0.8 | 3.67589 | 13.4261 | V_Air_extrait | 2.09783 | 45 | Air extrait
2 x Coude symétrique | R+2 | 0.5 | 0.5 | 3.54561 | 5.48389 | V_Air_extrait | 1.14248 | 45 | Air extrait
Coude symétrique | R+2 | 0.5 | 0.8 |  | 13.4261 | V_Air_extrait | 2.09783 | 45 | Air extrait
Coude symétrique | R+2 | 0.45 | 0.45 | 3.54561 | 4.59621 | V_Air_soufflé | 1 | 45 | Air soufflé
Coude symétrique | R+2 | 0.45 | 0.45 |  | 4.59621 | V_Air_soufflé | 1 | 45 | Air soufflé
Coude symétrique | R+2 | 0.5 | 0.5 | 3.54561 | 5.48389 | V_Air_soufflé | 1.14248 | 45 | Air soufflé
Coude symétrique | R+2 | 0.5 | 0.5 |  | 5.48389 | V_Air_soufflé | 1.14248 | 45 | Air soufflé
Coude symétrique | Mezzannine | 0.45 | 0.45 | 5.39066 | 8.32842 | V_Air_extrait | 1.73509 | 90 | Air extrait
Coude symétrique | Mezzannine | 0.4 | 0.55 | 3.13533 | 13.6316 | V_Air_soufflé | 2.12993 | 90 | Air soufflé
Coude symétrique | R+1 | 0.65 | 0.35 | 5.7875 | 10.3278 | V_Air_extrait | 1.61372 | 90 | Air extrait
2 x Coude symétrique | R+1 | 0.35 | 0.65 | 5.7875 | 16.3596 | V_Air_extrait | 2.55619 | 90 | Air extrait
Coude symétrique | R+1 | 0.45 | 0.45 |  | 8.32842 | V_Air_soufflé | 1.73509 | 90 | Air soufflé
Coude symétrique | Rez de chaussŽe | 0.5 | 0.5 | 3.78323 | 10.0078 | V_Air_soufflé | 2.08496 | 90 | Air soufflé
Coude symétrique | Rez de chaussŽe | 0.8 | 0.5 | 4.67209 | 17.3468 | V_Air_extrait | 2.71044 | 90 | Air extrait
Coude symétrique | Rez de chaussŽe | 0.5 | 0.5 |  | 10.0078 | V_Air_soufflé | 2.08496 | 90 | Air soufflé

# IfcFlowFitting: Coude à segment 3 parties (3)
Description: Coude à segment 3 parties
Pset Plancal nova - MEP - Nom: Coude à segment 3 parties; Geom-Ø (m): 0.5 m; Abbreviation: BSE; Tech-Materiel (ID): 1; Geom-Rayon de courbure (m): 0.5; Geom-Nb de segments (si segmente): 3; Tech-Epaisseur isolant (m): 0 m
Name | In | Calc-Perte de charge (Pa) (Pa) | Tech-Fluide | Geom-Surface (m2) (m2) | Geom-Angle (°) (rad) | Group
2 x Coude à segment 3 parties | R+2 | 4.92877 | V_Air_soufflé | 0.868178 | 45 | Air soufflé
Coude à segment 3 parties | Rez de chaussŽe | 6.15009 | V_Air_extrait | 1.48503 | 90 | Air extrait

# IfcFlowFitting: Coude à segment 4 parties (7)
Description: Coude à segment 4 parties
Pset Plancal nova - MEP - Nom: Coude à segment 4 parties; Abbreviation: BSE; Tech-Materiel (ID): 1; Geom-Nb de segments (si segmente): 4; Geom-Angle (°): 90 rad; Tech-Epaisseur isolant (m): 0 m
Name | In | Geom-Ø (m) (m) = Geom-Rayon de courbure (m) | Calc-Perte de charge (Pa) (Pa) | Tech-Fluide | Geom-Surface (m2) (m2) | Group
Coude à segment 4 parties | Toiture | 0.5 | 4.92877 | V_Air_soufflé | 1.48503 | Air soufflé
Coude à segment 4 parties | R+2 | 0.45 | 4.80782 | V_Air_soufflé | 1.22549 | Air soufflé
3 x Coude à segment 4 parties | R+2 | 0.5 | 4.92877 | V_Air_soufflé | 1.48503 | Air soufflé
Coude à segment 4 parties | Mezzannine | 0.5 | 6.33073 | V_Air_extrait | 1.48503 | Air extrait
Coude à segment 4 parties | Rez de chaussŽe | 0.5 | 5.60784 | V_Air_extrait | 1.48503 | Air extrait

# IfcFlowFitting: Couvercle circulaire (2)
In: Mezzannine
Description: Couvercle circulaire; Group: Air extrait
Pset Plancal nova - MEP - Nom: Couvercle circulaire; Geom-Ø (m): 0.16 m; Abbreviation: CC; Geom-Longueur (m): 0.04 m; Tech-Fluide: V_Air_extrait; Tech-Materiel (ID): 1; Tech-Epaisseur isolant (m): 0 m

# IfcFlowFitting: Couvercle de nettoyage (3)
Description: Couvercle de nettoyage; Group: Air extrait
Pset Plancal nova - MEP - Nom: Couvercle de nettoyage; Abbreviation: CNC; Tech-Fluide: V_Air_extrait; Tech-Materiel (ID): 1; Tech-Epaisseur isolant (m): 0 m
Name | In | Geom-Ø (m) (m) | Geom-Longueur (m) (m)
Couvercle de nettoyage | Mezzannine | 0.16 | 0.04
Couvercle de nettoyage | Rez de chaussŽe | 0.25 | 0.06
Couvercle de nettoyage | Rez de chaussŽe | 0.16 | 0.04

# IfcFlowFitting: Enddeckel (16)
Description: Enddeckel
Pset Plancal nova - MEP - Nom: Enddeckel; Abbreviation: DRE; Tech-Materiel (ID): 1; Tech-Epaisseur isolant (m): 0 m
Name | In | Geom-Ø (m) (m) | Geom-Longueur (m) (m) | Tech-Fluide | Group
Enddeckel | R+2 | 0.2 | 0.04 | V_Air_soufflé | Air soufflé
Enddeckel | Mezzannine | 0.315 | 0.06 | V_Air_soufflé | Air soufflé
Enddeckel | Mezzannine | 0.16 | 0.04 | V_Air_soufflé | Air soufflé
Enddeckel | Mezzannine | 0.16 | 0.04 | V_Air_extrait | Air extrait
Enddeckel | Mezzannine | 0.5 | 0.08 | V_Air_extrait | Air extrait
2 x Enddeckel | R+1 | 0.16 | 0.04 | V_Air_extrait | Air extrait
2 x Enddeckel | R+1 | 0.315 | 0.06 | V_Air_extrait | Air extrait
Enddeckel | R+1 | 0.5 | 0.08 | V_Air_extrait | Air extrait
Enddeckel | R+1 | 0.2 | 0.04 | V_Air_soufflé | Air soufflé
Enddeckel | R+1 | 0.315 | 0.06 | V_Air_soufflé | Air soufflé
Enddeckel | R+1 | 0.16 | 0.04 | V_Air_soufflé | Air soufflé
2 x Enddeckel | Rez de chaussŽe | 0.25 | 0.06 | V_Air_extrait | Air extrait
Enddeckel | Rez de chaussŽe | 0.315 | 0.06 | V_Air_extrait | Air extrait

# IfcFlowFitting: Fixation pour bride de raccord
In: Rez de chaussŽe
Description: Fixation pour bride de raccord; Group: Medium
Pset Plancal nova - MEP - Nom: Fixation pour bride de raccord; Geom-DN: 400; Tech-PN: 16

# IfcFlowFitting: Fond/couvercle (3)
In: Rez de chaussŽe
Description: Fond/couvercle
Pset Plancal nova - MEP - Nom: Fond/couvercle; Tech-Material: Tube acier d'après DIN 2448; Tech-Epaisseur isolant (m): 0 m
Name | Geom-Ø exterieur (m) (m) | Geom-DN | Group
Fond/couvercle | 0.0603 | 50 | Retour
Fond/couvercle | 0.0603 | 50 | Medium
Fond/couvercle | 0.0761 | 65 | Eau froide

# IfcFlowFitting: Grille de sol verticale (4)
In: Toiture
Description: Grille de sol verticale; Group: Eaux pluviales (EP)
Pset Plancal nova - MEP - Nom: Grille de sol verticale; Geom-DN: 100; Tech-Fluide: S_Eaux_pluviales

# IfcFlowFitting: Nourrice (2)
In: Rez de chaussŽe
Description: Nourrice
Pset - MEP - Tech-Type de connection (filetage=2, bride=3): 2; Nom: Nourrice; Geom-DN Manifold: 100; Geom-Longueur (m): 2.4 m; Tech-PN: 16; Tech-Epaisseur isolant (m): 0.02 m
Name | Group
Nourrice | Aller
Nourrice | Retour

# IfcFlowFitting: PE-HD Entonnoir ovale, siphonné
In: Rez de chaussŽe
Description: PE-HD Entonnoir ovale, siphonné; Group: Eaux usées (EU)
Pset Plancal nova - MEP - Nom: PE-HD Entonnoir ovale, siphonné; Geom-DN: 48; Tech-Fluide: S_Eaux_usées

# IfcFlowFitting: PE-HD coude 45° (99)
Description: PE-HD coude 45°
Pset Plancal nova - MEP - Nom: PE-HD coude 45°; Tech-Catalogue: Geberit Evacuation des eaux usées 2012 CH; Tech-Systeme: PE HD; Tech-Nom de produit: PE-HD coude 45°; Geom-angle (°): 45 rad
Name | In | Info | Tech-N° d'article | Geom-DN (m) | Tech-Fluide | Group
3 x PE-HD coude 45° | R+2 | DN 125 | 368.045.16.1 | 0.125 | S_Eaux_pluviales | Eaux pluviales (EP)
13 x PE-HD coude 45° | R+2 | DN 100 | 367.045.16.1 | 0.11 | S_Eaux_pluviales | Eaux pluviales (EP)
4 x PE-HD coude 45° | R+2 | DN 100 | 367.045.16.1 | 0.11 | S_Eaux_usées | Eaux usées (EU)
8 x PE-HD coude 45° | Mezzannine | DN 60 | 364.045.16.1 | 0.063 | S_Eaux_usées | Eaux usées (EU)
4 x PE-HD coude 45° | Mezzannine | DN 100 | 367.045.16.1 | 0.11 | S_Eaux_usées | Eaux usées (EU)
8 x PE-HD coude 45° | R+1 | DN 60 | 364.045.16.1 | 0.063 | S_Eaux_usées | Eaux usées (EU)
4 x PE-HD coude 45° | R+1 | DN 100 | 367.045.16.1 | 0.11 | S_Eaux_usées | Eaux usées (EU)
19 x PE-HD coude 45° | Rez de chaussŽe | DN 100 | 367.045.16.1 | 0.11 | S_Eaux_usées | Eaux usées (EU)
18 x PE-HD coude 45° | Rez de chaussŽe | DN 150 | 369.045.16.1 | 0.16 | S_Eaux_pluviales | Eaux pluviales (EP)
10 x PE-HD coude 45° | Rez de chaussŽe | DN 125 | 368.045.16.1 | 0.125 | S_Eaux_pluviales | Eaux pluviales (EP)
8 x PE-HD coude 45° | Rez de chaussŽe | DN 60 | 364.045.16.1 | 0.063 | S_Eaux_usées | Eaux usées (EU)

# IfcFlowFitting: PE-HD coude 90° à grand rayon (11)
Description: PE-HD coude 90° à grand rayon
Pset Plancal nova - MEP - Nom: PE-HD coude 90° à grand rayon; Tech-Catalogue: Geberit Evacuation des eaux usées 2012 CH; Tech-Systeme: PE HD; Tech-Nom de produit: PE-HD coude 90° à grand rayon; Geom-angle (°): 90 rad
Name | In | Info | Info 1 | Tech-N° d'article | Geom-DN (m) | Tech-Fluide | Group
2 x PE-HD coude 90° à grand rayon | R+2 | DN 100 | Couper l' angle à la dimension | 367.055.16.1 | 0.11 | S_Eaux_pluviales | Eaux pluviales (EP)
7 x PE-HD coude 90° à grand rayon | Rez de chaussŽe | DN 150 | Couper l' angle à la dimension | 369.055.16.1 | 0.16 | S_Eaux_pluviales | Eaux pluviales (EP)
PE-HD coude 90° à grand rayon | Rez de chaussŽe | DN 125 |  | 368.055.16.1 | 0.125 | S_Eaux_pluviales | Eaux pluviales (EP)
PE-HD coude 90° à grand rayon | Rez de chaussŽe | DN 56 |  | 363.055.16.1 | 0.056 | S_Eaux_usées | Eaux usées (EU)

# IfcFlowFitting: PE-HD embranchement 45° (19)
Description: PE-HD embranchement 45°
Pset Plancal nova - MEP - Nom: PE-HD embranchement 45°; Tech-Catalogue: Geberit Evacuation des eaux usées 2012 CH; Tech-Systeme: PE HD; Tech-Nom de produit: PE-HD embranchement 45°; Geom-angle (°): 45 rad
Name | In | Info | Tech-N° d'article | Geom-DN | Geom-DN embranchement | Tech-Fluide | Group
2 x PE-HD embranchement 45° | R+2 | 125/100 | 368.135.16.1 | 125 | 100 | S_Eaux_pluviales | Eaux pluviales (EP)
PE-HD embranchement 45° | R+2 | 125/125 | 368.139.16.1 | 125 | 125 | S_Eaux_pluviales | Eaux pluviales (EP)
PE-HD embranchement 45° | Mezzannine | 60/60 | 364.120.16.1 | 60 | 60 | S_Eaux_usées | Eaux usées (EU)
2 x PE-HD embranchement 45° | Mezzannine | 100/100 | 367.135.16.1 | 100 | 100 | S_Eaux_usées | Eaux usées (EU)
PE-HD embranchement 45° | Mezzannine | 100/60 | 367.120.16.1 | 100 | 60 | S_Eaux_usées | Eaux usées (EU)
2 x PE-HD embranchement 45° | R+1 | 100/100 | 367.135.16.1 | 100 | 100 | S_Eaux_usées | Eaux usées (EU)
PE-HD embranchement 45° | R+1 | 100/60 | 367.120.16.1 | 100 | 60 | S_Eaux_usées | Eaux usées (EU)
PE-HD embranchement 45° | R+1 | 60/60 | 364.120.16.1 | 60 | 60 | S_Eaux_usées | Eaux usées (EU)
6 x PE-HD embranchement 45° | Rez de chaussŽe | 100/100 | 367.135.16.1 | 100 | 100 | S_Eaux_usées | Eaux usées (EU)
PE-HD embranchement 45° | Rez de chaussŽe | 100/60 | 367.120.16.1 | 100 | 60 | S_Eaux_usées | Eaux usées (EU)
PE-HD embranchement 45° | Rez de chaussŽe | 60/60 | 364.120.16.1 | 60 | 60 | S_Eaux_usées | Eaux usées (EU)

# IfcFlowFitting: PE-HD machon long (11)
Description: PE-HD machon long
Pset Plancal nova - MEP - Nom: PE-HD machon long; Tech-Catalogue: Geberit Evacuation des eaux usées 2012 CH; Tech-Systeme: PE HD; Tech-Nom de produit: PE-HD machon long
Name | In | Info | Tech-N° d'article | Geom-DN | Tech-Fluide | Group
2 x PE-HD machon long | R+2 | DN 100 | 367.700.16.1 | 100 | S_Eaux_usées | Eaux usées (EU)
PE-HD machon long | R+2 | DN 125 | 368.700.16.1 | 125 | S_Eaux_pluviales | Eaux pluviales (EP)
2 x PE-HD machon long | R+2 | DN 100 | 367.700.16.1 | 100 | S_Eaux_pluviales | Eaux pluviales (EP)
PE-HD machon long | Mezzannine | DN 100 | 367.700.16.1 | 100 | S_Eaux_usées | Eaux usées (EU)
PE-HD machon long | Mezzannine | DN 125 | 368.700.16.1 | 125 | S_Eaux_pluviales | Eaux pluviales (EP)
PE-HD machon long | R+1 | DN 100 | 367.700.16.1 | 100 | S_Eaux_usées | Eaux usées (EU)
PE-HD machon long | R+1 | DN 125 | 368.700.16.1 | 125 | S_Eaux_pluviales | Eaux pluviales (EP)
PE-HD machon long | Rez de chaussŽe | DN 100 | 367.700.16.1 | 100 | S_Eaux_usées | Eaux usées (EU)
PE-HD machon long | Rez de chaussŽe | DN 125 | 368.700.16.1 | 125 | S_Eaux_pluviales | Eaux pluviales (EP)

# IfcFlowFitting: PE-HD manchon pour WC au sol (8)
Description: PE-HD manchon pour WC au sol; Group: Eaux usées (EU)
Pset Plancal nova - MEP - Info: DN 100; Tech-N° d'article: 367.898.16.1; Nom: PE-HD manchon pour WC au sol; Geom-DN: 100; Tech-Catalogue: Geberit Evacuation des eaux usées 2012 CH; Tech-Fluide: S_Eaux_usées; Tech-Systeme: PE HD; Tech-Nom de produit: PE-HD manchon pour WC au sol
Name | In
2 x PE-HD manchon pour WC au sol | Mezzannine
2 x PE-HD manchon pour WC au sol | R+1
4 x PE-HD manchon pour WC au sol | Rez de chaussŽe

# IfcFlowFitting: PE-HD manchon à emboiter (6)
Description: PE-HD manchon à emboiter
Pset Plancal nova - MEP - Info: DN 100; Tech-N° d'article: 367.779.16.1; Nom: PE-HD manchon à emboiter; Geom-DN: 100; Tech-Catalogue: Geberit Evacuation des eaux usées 2012 CH; Tech-Systeme: PE HD; Tech-Nom de produit: PE-HD manchon à emboiter
Name | In | Tech-Fluide | Group
4 x PE-HD manchon à emboiter | R+2 | S_Eaux_pluviales | Eaux pluviales (EP)
2 x PE-HD manchon à emboiter | Rez de chaussŽe | S_Eaux_usées | Eaux usées (EU)

# IfcFlowFitting: PE-HD manchon à emboiter réduit (6)
Description: PE-HD manchon à emboiter réduit; Group: Eaux usées (EU)
Pset Plancal nova - MEP - Info: DN 60/56; Tech-N° d'article: 364.752.16.1; Nom: PE-HD manchon à emboiter réduit; Geom-DN: 0.063 m; Tech-Catalogue: Geberit Evacuation des eaux usées 2012 CH; Tech-Fluide: S_Eaux_usées; Tech-Systeme: PE HD; Tech-Nom de produit: PE-HD manchon à emboiter réduit; Geom-angle (°): 0.004 rad
Name | In
2 x PE-HD manchon à emboiter réduit | Mezzannine
2 x PE-HD manchon à emboiter réduit | R+1
2 x PE-HD manchon à emboiter réduit | Rez de chaussŽe

# IfcFlowFitting: PE-HD manchon électro soudable (25)
Description: PE-HD manchon électro soudable
Pset Plancal nova - MEP - Nom: PE-HD manchon électro soudable; Tech-Catalogue: Geberit Evacuation des eaux usées 2012 CH; Tech-Systeme: PE HD; Tech-Nom de produit: PE-HD manchon électro soudable
Name | In | Info | Tech-N° d'article | Geom-DN | Tech-Fluide | Group
3 x PE-HD manchon électro soudable | R+2 | DN 100 | 367.771.16.1 | 100 | S_Eaux_usées | Eaux usées (EU)
3 x PE-HD manchon électro soudable | R+2 | DN 100 | 367.771.16.1 | 100 | S_Eaux_pluviales | Eaux pluviales (EP)
PE-HD manchon électro soudable | R+2 | DN 125 | 368.771.16.1 | 125 | S_Eaux_pluviales | Eaux pluviales (EP)
5 x PE-HD manchon électro soudable | Mezzannine | DN 100 | 367.771.16.1 | 100 | S_Eaux_usées | Eaux usées (EU)
PE-HD manchon électro soudable | Mezzannine | DN 60 | 364.771.16.1 | 60 | S_Eaux_usées | Eaux usées (EU)
5 x PE-HD manchon électro soudable | R+1 | DN 100 | 367.771.16.1 | 100 | S_Eaux_usées | Eaux usées (EU)
PE-HD manchon électro soudable | R+1 | DN 60 | 364.771.16.1 | 60 | S_Eaux_usées | Eaux usées (EU)
5 x PE-HD manchon électro soudable | Rez de chaussŽe | DN 100 | 367.771.16.1 | 100 | S_Eaux_usées | Eaux usées (EU)
PE-HD manchon électro soudable | Rez de chaussŽe | DN 60 | 364.771.16.1 | 60 | S_Eaux_usées | Eaux usées (EU)

# IfcFlowFitting: PE-HD réduction concentrique (2)
In: Rez de chaussŽe
Description: PE-HD réduction concentrique; Group: Eaux usées (EU)
Pset Plancal nova - MEP - Info: 100/56; Tech-N° d'article: 367.565.16.1; Nom: PE-HD réduction concentrique; Geom-DN 1: 100; Geom-DN 2: 56; Tech-Catalogue: Geberit Evacuation des eaux usées 2012 CH; Tech-Fluide: S_Eaux_usées; Tech-Systeme: PE HD; Tech-Nom de produit: PE-HD réduction concentrique

# IfcFlowFitting: PE-HD réduction excentrique (2)
In: R+2
Description: PE-HD réduction excentrique; Group: Eaux pluviales (EP)
Pset Plancal nova - MEP - Info: 125/100; Tech-N° d'article: 368.586.16.1; Nom: PE-HD réduction excentrique; Geom-DN 1: 125; Geom-DN 2: 100; Tech-Catalogue: Geberit Evacuation des eaux usées 2012 CH; Tech-Fluide: S_Eaux_pluviales; Tech-Systeme: PE HD; Tech-Nom de produit: PE-HD réduction excentrique

# IfcFlowFitting: PE-HD tubulure avec raccord
In: Rez de chaussŽe
Description: PE-HD tubulure avec raccord; Group: Eaux usées (EU)
Pset Plancal nova - MEP - Info: DN 56 Rg 70x1/6; Tech-N° d'article: 363.740.16.1; Nom: PE-HD tubulure avec raccord; Geom-DN: 56; Tech-Catalogue: Geberit Evacuation des eaux usées 2012 CH; Tech-Fluide: S_Eaux_usées; Tech-Systeme: PE HD; Tech-Nom de produit: PE-HD tubulure avec raccord

# IfcFlowFitting: PE-HD équerre avec mamachon de raccordement pour siphon (8)
Description: PE-HD équerre avec mamachon de raccordement pour siphon; Group: Eaux usées (EU)
Pset Plancal nova - MEP - Info: DN 56; Tech-N° d'article: 363.061.16.1; Nom: PE-HD équerre avec mamachon de raccordement pour siphon; Geom-DN: 0.056 m; Tech-Catalogue: Geberit Evacuation des eaux usées 2012 CH; Tech-Fluide: S_Eaux_usées; Tech-Systeme: PE HD; Tech-Nom de produit: PE-HD équerre avec mamachon de raccordement pour siphon; Geom-angle (°): 90 rad
Name | In
2 x PE-HD équerre avec mamachon de raccordement pour siphon | R+2
2 x PE-HD équerre avec mamachon de raccordement pour siphon | Mezzannine
2 x PE-HD équerre avec mamachon de raccordement pour siphon | R+1
2 x PE-HD équerre avec mamachon de raccordement pour siphon | Rez de chaussŽe

# IfcFlowFitting: PE-HD équerre de raccordement 88.5° (10)
Description: PE-HD équerre de raccordement 88.5°; Group: Eaux usées (EU)
Pset Plancal nova - MEP - Nom: PE-HD équerre de raccordement 88.5°; Tech-Catalogue: Geberit Evacuation des eaux usées 2012 CH; Tech-Fluide: S_Eaux_usées; Tech-Systeme: PE HD; Tech-Nom de produit: PE-HD équerre de raccordement 88.5°; Geom-angle (°): 88.5 rad
Name | In | Info | Tech-N° d'article | Geom-DN (m)
2 x PE-HD équerre de raccordement 88.5° | R+2 | DN 100 | 367.088.16.1 | 0.11
4 x PE-HD équerre de raccordement 88.5° | Rez de chaussŽe | DN 100 | 367.088.16.1 | 0.11
4 x PE-HD équerre de raccordement 88.5° | Rez de chaussŽe | DN 50 | 361.088.16.1 | 0.05

# IfcFlowFitting: Pièce combinée 2 Parties (4)
In: Toiture
Description: Pièce combinée 2 Parties
Pset Plancal nova - MEP - Info: Eléments: N° Pos: .1 N° Pos: .2; Nom: Pièce combinée 2 Parties; Abbreviation: KO; Tech-Materiel (ID): 1; Tech-Epaisseur isolant (m): 0 m
Name | Geom-Epaisseur (m) (m) | Geom-Overall side (m) (m) | Tech-Poids (kg) (kg) | Tech-Fluide | Geom-Surface (m2) (m2) | Group
Pièce combinée 2 Parties | 0.6 | 1 | 28.16 | V_Air_soufflé | 4.4 | Air soufflé
Pièce combinée 2 Parties | 0.5 | 1.3 | 20.992 | V_Air_extrait | 3.68 | Air extrait
Pièce combinée 2 Parties | 0.5 | 1 | 19.2 | V_Air_soufflé | 4 | Air soufflé
Pièce combinée 2 Parties | 1.2 | 1.1 | 84 | V_Air_extrait | 10.5 | Air extrait

# IfcFlowFitting: Pièce combinée rect. 3 parties
In: R+2
Description: Pièce combinée rect. 3 parties; Group: Air extrait
Pset Plancal nova - MEP - Geom-Epaisseur (m): 0.5 m; Geom-Overall side (m): 0.8 m; Nom: Pièce combinée rect. 3 parties; Tech-Poids (kg): 18.014 kg; Abbreviation: PCR; Tech-Fluide: V_Air_extrait; Tech-Materiel (ID): 1; Geom-Surface (m2): 3.75292 m2; Tech-Epaisseur isolant (m): 0 m

# IfcFlowFitting: Pièce d' embranchement (3)
In: Rez de chaussŽe
Description: Pièce d' embranchement
Pset Plancal nova - MEP - Nom: Pièce d' embranchement; Geom-Longueur (m): 0.128 m; Geom-Longueur sorties (m): 0.064 m
Name | Geom-Ø ext 1 (m) (m) = Geom-Ø ext 2 (m) (m) = Geom-Ø ext 3 (m) (m) | Geom-DN1 = Geom-DN2 = Geom-DN3 | Tech-Material | Tech-Epaisseur isolant (m) (m) | Group
Pièce d' embranchement | 0.0424 | 32 | Tube acier d'après DIN 2448 | 0 | Aller
Pièce d' embranchement | 0.0424 | 32 | Tube acier d'après DIN 2448 | 0 | Retour
Pièce d' embranchement | 0.0603 | 50 | Selon DIN 2615 | 0.02 | Retour

# IfcFlowFitting: Pièce en té (oblique)
In: Mezzannine
Description: Pièce en té (oblique); Group: Air extrait
Pset Plancal nova - MEP - Geom-Epaisseur (m): 0.45 m; Geom-Côte 1 (m): 0.45 m; Nom: Pièce en té (oblique); Geom-Côte 2 (m): 0.5 m; Geom-Ecart (m): 0.025 m; Tech-Poids (kg): 5.22619 kg; Abbreviation: TA; Geom-Longueur (m): 0.46 m; Tech-Fluide: V_Air_extrait; Geom-Longueur de branche (m): 0.15 m; Tech-Materiel (ID): 1; Geom-Ecart à branche (m): 0.15 m; Geom-Surface (m2): 1.08879 m2; Tech-Epaisseur isolant (m): 0 m

# IfcFlowFitting: Pièce en té 45°
In: R+1
Description: Pièce en té 45°; Group: Air soufflé
Pset Plancal nova - MEP - Nom: Pièce en té 45°; Geom-Ø principal (m): 0.2 m; Geom-Ø secondaire (m): 0.2 m; Geom-Ø branche (m): 0.16 m; Abbreviation: AYE; Geom-Longueur (m): 0.39 m; Geom-Longueur branch (m): 0.305 m; Tech-Fluide: V_Air_soufflé; Tech-Materiel (ID): 1; Angle (°): 45 rad; Tech-Epaisseur isolant (m): 0 m

# IfcFlowFitting: Pièce en té 90° (121)
Description: Pièce en té 90°
Pset Plancal nova - MEP - Nom: Pièce en té 90°; Abbreviation: ATE; Tech-Materiel (ID): 1; Angle (°): 90 rad; Tech-Epaisseur isolant (m): 0 m
Name | In | Geom-Ø principal (m) (m) = Geom-Ø secondaire (m) (m) | Geom-Ø branche (m) (m) | Geom-Longueur (m) (m) | Geom-Longueur branch (m) (m) | Tech-Fluide | Group
4 x Pièce en té 90° | R+2 | 0.25 | 0.16 | 0.26 | 0.175 | V_Air_extrait | Air extrait
3 x Pièce en té 90° | R+2 | 0.2 | 0.16 | 0.26 | 0.15 | V_Air_extrait | Air extrait
5 x Pièce en té 90° | R+2 | 0.4 | 0.16 | 0.26 | 0.25 | V_Air_extrait | Air extrait
2 x Pièce en té 90° | R+2 | 0.355 | 0.16 | 0.26 | 0.23 | V_Air_extrait | Air extrait
5 x Pièce en té 90° | R+2 | 0.315 | 0.16 | 0.26 | 0.21 | V_Air_extrait | Air extrait
3 x Pièce en té 90° | R+2 | 0.45 | 0.16 | 0.26 | 0.275 | V_Air_extrait | Air extrait
2 x Pièce en té 90° | R+2 | 0.45 | 0.16 | 0.26 | 0.275 | V_Air_soufflé | Air soufflé
3 x Pièce en té 90° | R+2 | 0.4 | 0.16 | 0.26 | 0.25 | V_Air_soufflé | Air soufflé
Pièce en té 90° | R+2 | 0.355 | 0.16 | 0.26 | 0.23 | V_Air_soufflé | Air soufflé
3 x Pièce en té 90° | R+2 | 0.315 | 0.16 | 0.26 | 0.21 | V_Air_soufflé | Air soufflé
2 x Pièce en té 90° | R+2 | 0.25 | 0.16 | 0.26 | 0.175 | V_Air_soufflé | Air soufflé
Pièce en té 90° | R+2 | 0.2 | 0.16 | 0.26 | 0.15 | V_Air_soufflé | Air soufflé
Pièce en té 90° | Mezzannine | 0.5 | 0.16 | 0.26 | 0.3 | V_Air_soufflé | Air soufflé
Pièce en té 90° | Mezzannine | 0.45 | 0.16 | 0.26 | 0.275 | V_Air_soufflé | Air soufflé
Pièce en té 90° | Mezzannine | 0.45 | 0.315 | 0.465 | 0.3 | V_Air_soufflé | Air soufflé
3 x Pièce en té 90° | Mezzannine | 0.315 | 0.16 | 0.26 | 0.21 | V_Air_soufflé | Air soufflé
Pièce en té 90° | Mezzannine | 0.25 | 0.16 | 0.26 | 0.175 | V_Air_soufflé | Air soufflé
Pièce en té 90° | Mezzannine | 0.25 | 0.2 | 0.33 | 0.19 | V_Air_soufflé | Air soufflé
Pièce en té 90° | Mezzannine | 0.2 | 0.16 | 0.26 | 0.15 | V_Air_soufflé | Air soufflé
3 x Pièce en té 90° | Mezzannine | 0.5 | 0.16 | 0.26 | 0.3 | V_Air_extrait | Air extrait
5 x Pièce en té 90° | Mezzannine | 0.45 | 0.16 | 0.26 | 0.275 | V_Air_extrait | Air extrait
6 x Pièce en té 90° | Mezzannine | 0.4 | 0.16 | 0.26 | 0.25 | V_Air_extrait | Air extrait
2 x Pièce en té 90° | Mezzannine | 0.355 | 0.16 | 0.26 | 0.23 | V_Air_extrait | Air extrait
6 x Pièce en té 90° | Mezzannine | 0.315 | 0.16 | 0.26 | 0.21 | V_Air_extrait | Air extrait
6 x Pièce en té 90° | Mezzannine | 0.25 | 0.16 | 0.26 | 0.175 | V_Air_extrait | Air extrait
4 x Pièce en té 90° | Mezzannine | 0.2 | 0.16 | 0.26 | 0.15 | V_Air_extrait | Air extrait
2 x Pièce en té 90° | Mezzannine | 0.16 | 0.16 | 0.26 | 0.13 | V_Air_extrait | Air extrait
2 x Pièce en té 90° | R+1 | 0.25 | 0.16 | 0.26 | 0.175 | V_Air_extrait | Air extrait
4 x Pièce en té 90° | R+1 | 0.2 | 0.16 | 0.26 | 0.15 | V_Air_extrait | Air extrait
Pièce en té 90° | R+1 | 0.45 | 0.16 | 0.26 | 0.275 | V_Air_extrait | Air extrait
3 x Pièce en té 90° | R+1 | 0.4 | 0.16 | 0.26 | 0.25 | V_Air_extrait | Air extrait
Pièce en té 90° | R+1 | 0.355 | 0.16 | 0.26 | 0.23 | V_Air_extrait | Air extrait
2 x Pièce en té 90° | R+1 | 0.315 | 0.16 | 0.26 | 0.21 | V_Air_extrait | Air extrait
2 x Pièce en té 90° | Rez de chaussŽe | 0.355 | 0.16 | 0.26 | 0.23 | V_Air_soufflé | Air soufflé
6 x Pièce en té 90° | Rez de chaussŽe | 0.315 | 0.16 | 0.26 | 0.21 | V_Air_soufflé | Air soufflé
Pièce en té 90° | Rez de chaussŽe | 0.25 | 0.25 | 0.38 | 0.19 | V_Air_soufflé | Air soufflé
3 x Pièce en té 90° | Rez de chaussŽe | 0.25 | 0.16 | 0.26 | 0.175 | V_Air_soufflé | Air soufflé
2 x Pièce en té 90° | Rez de chaussŽe | 0.2 | 0.16 | 0.26 | 0.15 | V_Air_soufflé | Air soufflé
Pièce en té 90° | Rez de chaussŽe | 0.4 | 0.16 | 0.26 | 0.25 | V_Air_soufflé | Air soufflé
2 x Pièce en té 90° | Rez de chaussŽe | 0.5 | 0.16 | 0.26 | 0.3 | V_Air_extrait | Air extrait
2 x Pièce en té 90° | Rez de chaussŽe | 0.45 | 0.16 | 0.26 | 0.275 | V_Air_extrait | Air extrait
5 x Pièce en té 90° | Rez de chaussŽe | 0.4 | 0.16 | 0.26 | 0.25 | V_Air_extrait | Air extrait
Pièce en té 90° | Rez de chaussŽe | 0.355 | 0.16 | 0.26 | 0.23 | V_Air_extrait | Air extrait
Pièce en té 90° | Rez de chaussŽe | 0.5 | 0.45 | 0.62 | 0.335 | V_Air_extrait | Air extrait
2 x Pièce en té 90° | Rez de chaussŽe | 0.25 | 0.16 | 0.26 | 0.175 | V_Air_extrait | Air extrait
Pièce en té 90° | Rez de chaussŽe | 0.16 | 0.16 | 0.26 | 0.13 | V_Air_extrait | Air extrait
Pièce en té 90° | Rez de chaussŽe | 0.315 | 0.16 | 0.26 | 0.21 | V_Air_extrait | Air extrait
Pièce en té 90° | Rez de chaussŽe | 0.16 | 0.16 | 0.26 | 0.13 | V_Désenfumage | Désenfumage

# IfcFlowFitting: Puits collectif (2)
In: Rez de chaussŽe
Description: Puits collectif; Group: Eaux usées
Pset Plancal nova - MEP - Nom: Puits collectif; Geom-Ø ext 1 (m): 0.8 m; Geom-Ø ext 2 (m): 0.6 m; Geom-Heigth (m): 2.5 m

# IfcFlowFitting: Réduction (19)
In: Rez de chaussŽe
Description: Réduction
Pset Plancal nova - MEP - Nom: Réduction; Tech-Material: Selon DIN 2616
Name | Geom-Ø ext 1 (m) (m) | Geom-Ø ext 2 (m) (m) | Geom-DN1 | Geom-DN2 | Geom-Longueur (m) (m) | Tech-Epaisseur isolant (m) (m) | Group
3 x Réduction | 0.0269 | 0.0337 | 20 | 25 | 0.05 | 0 | Retour
2 x Réduction | 0.0337 | 0.0269 | 25 | 20 | 0.05 | 0 | Aller
2 x Réduction | 0.0269 | 0.0337 | 20 | 25 | 0.05 | 0 | Aller
Réduction | 0.0424 | 0.0213 | 32 | 15 | 0.05 | 0 | Aller
2 x Réduction | 0.0483 | 0.0424 | 40 | 32 | 0.064 | 0 | Aller
Réduction | 0.0424 | 0.0213 | 32 | 15 | 0.05 | 0 | Retour
Réduction | 0.0424 | 0.0483 | 32 | 40 | 0.064 | 0 | Aller
Réduction | 0.0424 | 0.0337 | 32 | 25 | 0.05 | 0 | Aller
Réduction | 0.0337 | 0.0424 | 25 | 32 | 0.05 | 0 | Aller
Réduction | 0.0603 | 0.0889 | 50 | 80 | 0.09 | 0 | Retour
Réduction | 0.0889 | 0.0603 | 80 | 50 | 0.09 | 0 | Retour
2 x Réduction | 0.0889 | 0.0603 | 80 | 50 | 0.09 | 0 | Medium
Réduction | 0.0603 | 0.0424 | 50 | 32 | 0.076 | 0.02 | Retour

# IfcFlowFitting: Réduction asymétrique (15)
Description: Réduction asymétrique
Pset Plancal nova - MEP - Nom: Réduction asymétrique; Tech-Materiel (ID): 1; Tech-Epaisseur isolant (m): 0 m
Name | In | Geom-Section 1 côte 1 (m) (m) | Geom-Section 1 côte 2 (m) (m) | Geom-Section 2 côte 1 (m) (m) | Geom-Section 2 côte 2 (m) (m) | Calc-Perte de charge (Pa) (Pa) | Geom-Ecart à section 2 (m) (m) | Geom-Ecart à section 1 (m) (m) | Tech-Poids (kg) (kg) | Abbreviation | Geom-Longueur (m) (m) | Tech-Fluide | Geom-Surface (m2) (m2) | Group
Réduction asymétrique | Toiture | 1.2 | 1.2 | 1.4 | 1.4 | 0.0000286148 | 0.00001 | 0 | 20.0352 | UA | 0.4 | V_Air_neuf | 2.5044 | Air neuf
Réduction asymétrique | Toiture | 1.2 | 1.1 | 1.2 | 1.2 | -0.139195 | 0.1 | 0 | 38.5915 | UA | 1 | V_Air_extrait | 4.82394 | Air extrait
Réduction asymétrique | Toiture | 0.5 | 0.5 | 0.45 | 0.45 | 0.211024 | 0 | 0.00001 | 4.82394 | UA | 0.5 | V_Air_soufflé | 1.00499 | Air soufflé
Réduction asymétrique | Toiture | 0.6 | 1.2 | 0.6 | 0.9 | 0.36744 | 0 | 0 | 30.0681 | UA | 1 | V_Air_extrait | 3.75851 | Air extrait
Réduction asymétrique | Toiture | 1.3 | 1.2 | 1 | 0.5 | 0.729348 | 0 | 0 | 48.8262 | UA | 1 | V_Air_soufflé | 6.10328 | Air soufflé
Réduction asymétrique | Toiture | 0.5 | 1.2 | 0.5 | 0.8 | 1.69983 | 0 | 0 | 29.2953 | UA | 1 | V_Air_extrait | 3.66191 | Air extrait
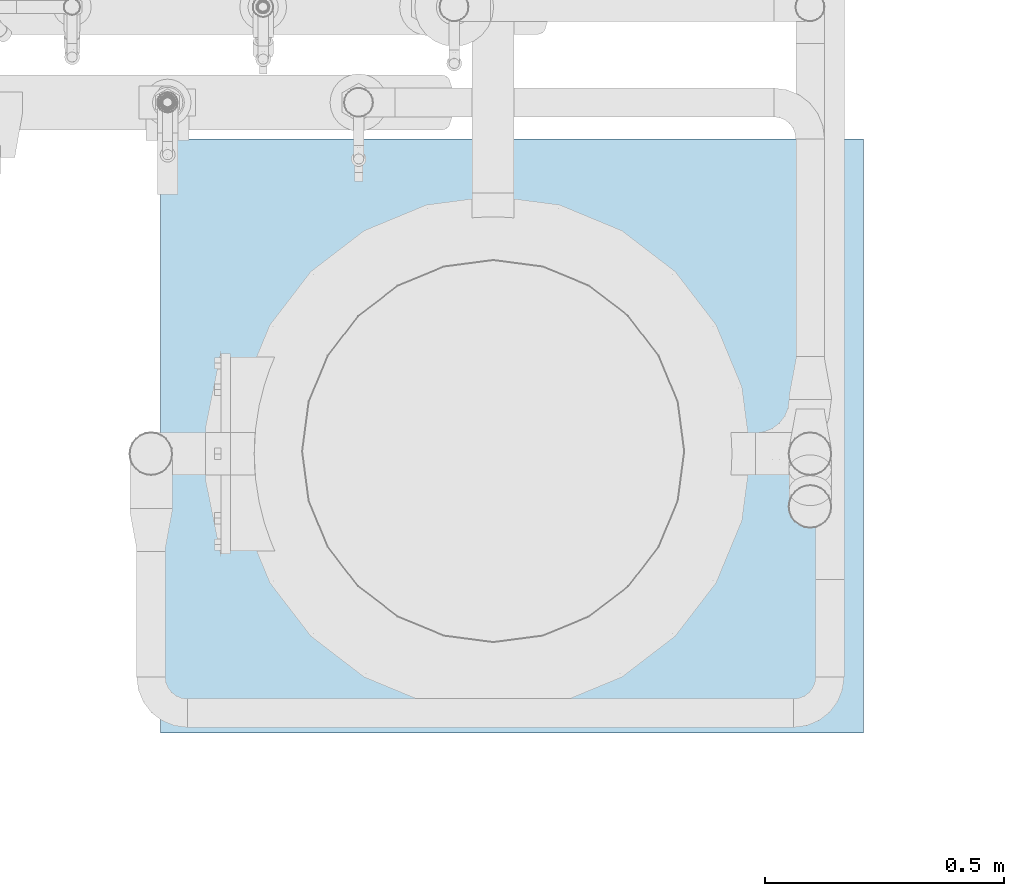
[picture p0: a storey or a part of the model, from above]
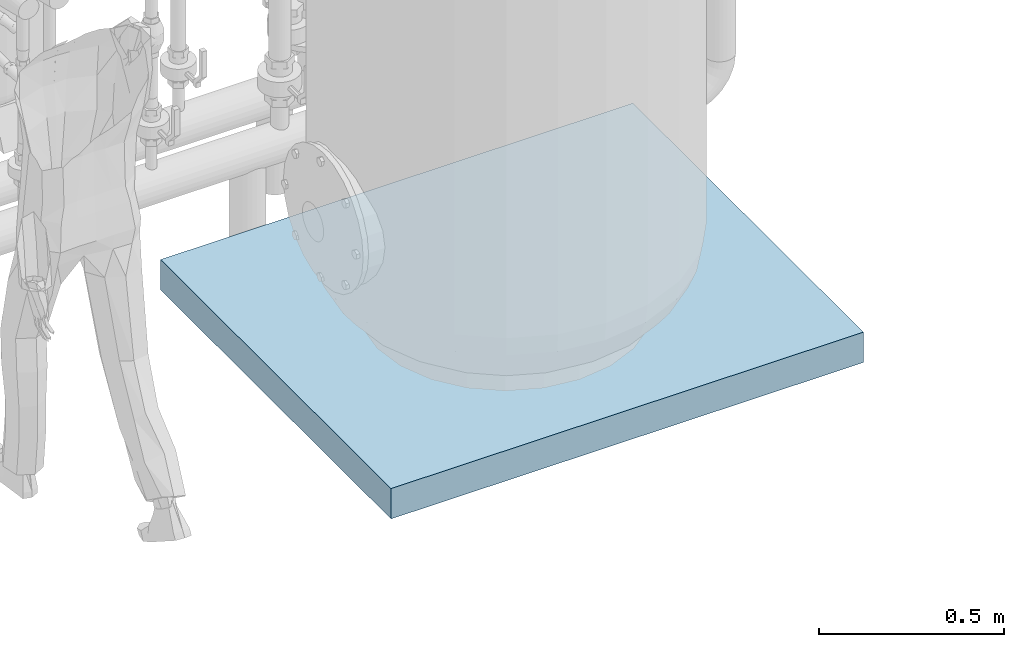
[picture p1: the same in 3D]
Properties of the parts of a building model (IFC2X3), part 2 of 4

# IfcFlowFitting: Réduction asymétrique (15)
Name | In | Geom-Section 1 côte 1 (m) (m) | Geom-Section 1 côte 2 (m) (m) | Geom-Section 2 côte 1 (m) (m) | Geom-Section 2 côte 2 (m) (m) | Calc-Perte de charge (Pa) (Pa) | Geom-Ecart à section 2 (m) (m) | Geom-Ecart à section 1 (m) (m) | Tech-Poids (kg) (kg) | Abbreviation | Geom-Longueur (m) (m) | Tech-Fluide | Geom-Surface (m2) (m2) | Group
Réduction asymétrique | Toiture | 1.3 | 1.2 | 1.4 | 1.4 | 0.0000156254 | 0.00001 | 0 | 18.4715 | UA | 0.4 | V_Air_neuf | 2.30894 | Air neuf
Réduction asymétrique | Toiture | 1.2 | 1.2 | 1 | 0.6 | 0.647179 | -0.15 | 0 | 42.1089 | UA | 1 | V_Air_soufflé | 5.26361 | Air soufflé
Réduction asymétrique | R+2 | 0.5 | 0.9 | 0.5 | 0.85 | 0.0946325 | 0 | 0 | 2.68822 | UA | 0.141435 | V_Air_extrait | 1 | Air extrait
Réduction asymétrique | R+2 | 0.5 | 0.9 | 0.5 | 0.85 | 0.044919 | 0 | 0 | 3.52072 | UA | 0.19 | V_Air_extrait | 1 | Air extrait
Réduction asymétrique | Mezzannine | 0.9 | 0.4 | 0.9 | 0.5 | 0.367737 | 0.095 | 0 | 4.96047 | UA | 0.26 | V_Air_extrait | 1 | Air extrait
Réduction asymétrique | Mezzannine |  |  |  |  | 0.0840352 |  |  | 7.32659 | RA | 0.6 | V_Air_soufflé | 1.14478 | Air soufflé | Pset Plancal nova - MEP - Geom-Côte 1 (m): 0.4 m; Geom-Côte 2 (m): 0.55 m; Geom-Ø (m): 0.5 m; Geom-Ecart 2 (m): -0.025 m; Geom-Ecart 1 (m): 0.055 m; Geom-Tenon (m): 0.05 m
Réduction asymétrique | R+1 |  |  |  |  | 1.18788 |  |  | 3.64752 | RA | 0.4 | V_Air_soufflé | 1 | Air soufflé | Pset Plancal nova - MEP - Geom-Côte 1 (m): 0.45 m; Geom-Côte 2 (m): 0.45 m; Geom-Ø (m): 0.315 m; Geom-Ecart 2 (m): 0 m; Geom-Ecart 1 (m): -0.0675 m; Geom-Tenon (m): 0.05 m
Réduction asymétrique | R+1 | 0.65 | 0.35 | 0.5 | 0.5 | 0.0967309 | 0.125 | -0.075 | 4.39741 | UA | 0.32 | V_Air_extrait | 1 | Air extrait
Réduction asymétrique | R+1 | 0.45 | 0.4 | 0.45 | 0.45 |  | 0.05 | 0 | 2.62775 | UA | 0.3 | V_Air_soufflé | 1 | Air soufflé

# IfcFlowFitting: Réduction conique (90)
Description: Réduction conique
Pset Plancal nova - MEP - Nom: Réduction conique; Abbreviation: USE; Tech-Materiel (ID): 1; Geom-Ecart (m): 0 m; Tech-Epaisseur isolant (m): 0 m
Name | In | Geom-Ø principal (m) (m) | Geom-Ø secondaire (m) (m) | Calc-Perte de charge (Pa) (Pa) | Geom-Longueur (m) (m) | Tech-Fluide | Geom-Surface (m2) (m2) | Group
3 x Réduction conique | R+2 | 0.25 | 0.2 | 1.16978 | 0.099 | V_Air_extrait | 0.164227 | Air extrait
3 x Réduction conique | R+2 | 0.2 | 0.16 | 0.706727 | 0.085 | V_Air_extrait | 0.0983319 | Air extrait
3 x Réduction conique | R+2 | 0.16 | 0.125 | 2.14237 | 0.078 | V_Air_extrait | 0.0751312 | Air extrait
Réduction conique | R+2 | 0.5 | 0.4 | 1.84825 | 0.177 | V_Air_extrait | 0.501555 | Air extrait
2 x Réduction conique | R+2 | 0.4 | 0.355 | 0.807212 | 0.097 | V_Air_extrait | 0.316099 | Air extrait
2 x Réduction conique | R+2 | 0.355 | 0.315 | 1.00057 | 0.085 | V_Air_extrait | 0.223289 | Air extrait
Réduction conique | R+2 | 0.315 | 0.25 | 1.13701 | 0.119 | V_Air_extrait | 0.224365 | Air extrait
Réduction conique | R+2 | 0.45 | 0.4 | 0.928822 | 0.109 | V_Air_extrait | 0.371729 | Air extrait
Réduction conique | R+2 | 0.315 | 0.25 | 2.02136 | 0.119 | V_Air_extrait | 0.224365 | Air extrait
Réduction conique | R+2 | 0.45 | 0.4 | 0.252309 | 0.109 | V_Air_soufflé | 0.371729 | Air soufflé
Réduction conique | R+2 | 0.4 | 0.315 | 0.619218 | 0.152 | V_Air_soufflé | 0.371776 | Air soufflé
Réduction conique | R+2 | 0.315 | 0.2 | 0.593304 | 0.188 | V_Air_soufflé | 0.270837 | Air soufflé
Réduction conique | R+2 | 0.45 | 0.4 | 0.305293 | 0.109 | V_Air_soufflé | 0.371729 | Air soufflé
Réduction conique | R+2 | 0.4 | 0.355 | 0.265421 | 0.097 | V_Air_soufflé | 0.316099 | Air soufflé
Réduction conique | R+2 | 0.355 | 0.315 | 0.32862 | 0.085 | V_Air_soufflé | 0.223289 | Air soufflé
Réduction conique | R+2 | 0.315 | 0.25 | 0.669769 | 0.119 | V_Air_soufflé | 0.224365 | Air soufflé
Réduction conique | R+2 | 0.25 | 0.2 | 0.393189 | 0.099 | V_Air_soufflé | 0.164227 | Air soufflé
Réduction conique | R+2 | 0.2 | 0.16 | 0.239984 | 0.085 | V_Air_soufflé | 0.0983319 | Air soufflé
Réduction conique | Mezzannine | 0.5 | 0.45 | 0.261919 | 0.109 | V_Air_soufflé | 0.413983 | Air soufflé
Réduction conique | Mezzannine | 0.45 | 0.315 | 0.81893 | 0.22 | V_Air_soufflé | 0.49056 | Air soufflé
Réduction conique | Mezzannine | 0.315 | 0.25 | 0.669769 | 0.119 | V_Air_soufflé | 0.224365 | Air soufflé
Réduction conique | Mezzannine | 0.25 | 0.16 | 0.36125 | 0.154 | V_Air_soufflé | 0.193428 | Air soufflé
Réduction conique | Mezzannine | 0.2 | 0.16 | 0.239984 | 0.085 | V_Air_soufflé | 0.0983319 | Air soufflé
Réduction conique | Mezzannine | 0.5 | 0.45 | 0.805211 | 0.109 | V_Air_extrait | 0.413983 | Air extrait
2 x Réduction conique | Mezzannine | 0.45 | 0.4 | 0.928822 | 0.109 | V_Air_extrait | 0.371729 | Air extrait
2 x Réduction conique | Mezzannine | 0.4 | 0.355 | 0.807212 | 0.097 | V_Air_extrait | 0.316099 | Air extrait
2 x Réduction conique | Mezzannine | 0.355 | 0.315 | 1.00057 | 0.085 | V_Air_extrait | 0.223289 | Air extrait
2 x Réduction conique | Mezzannine | 0.315 | 0.25 | 2.02136 | 0.119 | V_Air_extrait | 0.224365 | Air extrait
4 x Réduction conique | Mezzannine | 0.25 | 0.2 | 1.16978 | 0.099 | V_Air_extrait | 0.164227 | Air extrait
4 x Réduction conique | Mezzannine | 0.2 | 0.16 | 0.706727 | 0.085 | V_Air_extrait | 0.0983319 | Air extrait
2 x Réduction conique | Mezzannine | 0.16 | 0.125 | 2.14237 | 0.078 | V_Air_extrait | 0.0751312 | Air extrait
Réduction conique | Mezzannine | 0.16 | 0.125 |  | 0.078 | V_Air_extrait | 0.0751312 | Air extrait
2 x Réduction conique | R+1 | 0.25 | 0.2 | 1.16978 | 0.099 | V_Air_extrait | 0.164227 | Air extrait
4 x Réduction conique | R+1 | 0.2 | 0.16 | 0.706727 | 0.085 | V_Air_extrait | 0.0983319 | Air extrait
Réduction conique | R+1 | 0.45 | 0.4 | 0.928822 | 0.109 | V_Air_extrait | 0.371729 | Air extrait
Réduction conique | R+1 | 0.4 | 0.355 | 0.807212 | 0.097 | V_Air_extrait | 0.316099 | Air extrait
Réduction conique | R+1 | 0.355 | 0.315 | 1.00057 | 0.085 | V_Air_extrait | 0.223289 | Air extrait
Réduction conique | R+1 | 0.315 | 0.2 | 0.593304 | 0.188 | V_Air_soufflé | 0.270837 | Air soufflé
Réduction conique | R+1 | 0.2 | 0.16 | 0.239984 | 0.085 | V_Air_soufflé | 0.0983319 | Air soufflé
3 x Réduction conique | R+1 | 0.16 | 0.125 | 2.14237 | 0.078 | V_Air_extrait | 0.0751312 | Air extrait
Réduction conique | R+1 | 0.315 | 0.2 | 0.593304 | 0.188 | V_Air_extrait | 0.270837 | Air extrait
2 x Réduction conique | Rez de chaussŽe | 0.355 | 0.315 | 0.32862 | 0.085 | V_Air_soufflé | 0.223289 | Air soufflé
2 x Réduction conique | Rez de chaussŽe | 0.315 | 0.25 | 0.669769 | 0.119 | V_Air_soufflé | 0.224365 | Air soufflé
Réduction conique | Rez de chaussŽe | 0.25 | 0.16 | 0.36125 | 0.154 | V_Air_soufflé | 0.193428 | Air soufflé
2 x Réduction conique | Rez de chaussŽe | 0.25 | 0.2 | 0.393189 | 0.099 | V_Air_soufflé | 0.164227 | Air soufflé
2 x Réduction conique | Rez de chaussŽe | 0.2 | 0.16 | 0.239984 | 0.085 | V_Air_soufflé | 0.0983319 | Air soufflé
Réduction conique | Rez de chaussŽe | 0.4 | 0.355 | 0.265421 | 0.097 | V_Air_soufflé | 0.316099 | Air soufflé
3 x Réduction conique | Rez de chaussŽe | 0.125 | 0.16 | 2.14237 | 0.078 | V_Air_extrait | 0.0663347 | Air extrait
Réduction conique | Rez de chaussŽe | 0.5 | 0.45 | 0.805211 | 0.109 | V_Air_extrait | 0.413983 | Air extrait
Réduction conique | Rez de chaussŽe | 0.45 | 0.4 | 0.767622 | 0.109 | V_Air_extrait | 0.371729 | Air extrait
2 x Réduction conique | Rez de chaussŽe | 0.4 | 0.355 | 0.807212 | 0.097 | V_Air_extrait | 0.316099 | Air extrait
Réduction conique | Rez de chaussŽe | 0.355 | 0.315 | 0.326718 | 0.085 | V_Air_extrait | 0.223289 | Air extrait
Réduction conique | Rez de chaussŽe | 0.5 | 0.25 | 5.50411 | 0.378 | V_Air_extrait | 0.696648 | Air extrait
Réduction conique | Rez de chaussŽe | 0.25 | 0.16 | 1.84854 | 0.154 | V_Air_extrait | 0.193428 | Air extrait
Réduction conique | Rez de chaussŽe | 0.45 | 0.4 | 0.928822 | 0.109 | V_Air_extrait | 0.371729 | Air extrait
Réduction conique | Rez de chaussŽe | 0.355 | 0.315 | 1.00057 | 0.085 | V_Air_extrait | 0.223289 | Air extrait
Réduction conique | Rez de chaussŽe | 0.315 | 0.25 | 1.13701 | 0.119 | V_Air_extrait | 0.224365 | Air extrait
Réduction conique | Rez de chaussŽe | 0.16 | 0.04 |  | 0.195166 | V_Désenfumage | 0.101526 | Désenfumage

# IfcFlowFitting: Réduction symétrique (12)
Description: Réduction symétrique
Pset Plancal nova - MEP - Nom: Réduction symétrique; Tech-Materiel (ID): 1; Tech-Epaisseur isolant (m): 0 m
Name | In | Geom-Côte 1 (m) (m) | Geom-Côte 2 (m) (m) | Geom-Ø (m) (m) | Calc-Perte de charge (Pa) (Pa) | Geom-Ecart 2 (m) (m) | Geom-Ecart 1 (m) (m) | Tech-Poids (kg) (kg) | Abbreviation | Geom-Longueur (m) (m) | Tech-Fluide | Geom-Surface (m2) (m2) | Geom-Tenon (m) (m) | Group
Réduction symétrique | Toiture | 0.6 | 0.5 | 0.5 | 0.533091 | 0.00001 | 0.00001 | 7.07511 | RS | 0.5 | V_Air_soufflé | 1.10549 | 0.05 | Air soufflé
Réduction symétrique | R+2 | 0.5 | 0.5 | 0.5 | -0.239009 | 0.00001 | 0.00001 | 1.248 | RS | 0.13 | V_Air_extrait | 1 | 0.05 | Air extrait
Réduction symétrique | R+2 | 0.5 | 0.6 | 0.45 | 0.874455 | 0.00001 | 0.00001 | 3.80876 | RS | 0.259904 | V_Air_soufflé | 1 | 0.05 | Air soufflé
Réduction symétrique | R+2 | 0.3 | 0.5 | 0.45 | 0.0560406 | -0.025 | 0.075 | 4.64386 | RS | 0.6 | V_Air_extrait | 1 | 0.05 | Air extrait
Réduction symétrique | Mezzannine | 0.45 | 0.16 | 0.16 | 1.61516 | 0.00001 | 0.00001 | 2.17072 | RS | 0.341147 | V_Air_extrait | 1 | 0.05 | Air extrait
Réduction symétrique | Mezzannine | 0.45 | 0.5 | 0.5 | -0.735126 | 0.00001 | 0.00001 | 1.59687 | RS | 0.173301 | V_Air_extrait | 1 | 0.05 | Air extrait
Réduction symétrique | Mezzannine | 0.5 | 0.9 | 0.5 | 2.28892 | 0.00001 | 0.00001 | 9.25905 | RS | 0.47641 | V_Air_extrait | 1.44673 | 0.05 | Air extrait
Réduction symétrique | Mezzannine | 0.55 | 0.45 | 0.5 | 0.0672113 | 0.00001 | 0.00001 | 6.408 | RS | 0.5 | V_Air_soufflé | 1.00125 | 0.05 | Air soufflé
Réduction symétrique | R+1 | 0.5 | 0.5 | 0.5 | -0.210067 | 0.00001 | 0.00001 | 1.248 | RS | 0.13 | V_Air_extrait | 1 | 0.05 | Air extrait
Réduction symétrique | R+1 |  |  |  | 0.239482 |  |  | 3.09657 | US | 0.23 | V_Air_extrait | 1 |  | Air extrait | Pset Plancal nova - MEP - Geom-Section 1 côte 1 (m): 0.5 m; Geom-Section 1 côte 2 (m): 0.5 m; Geom-Section 2 côte 1 (m): 0.65 m; Geom-Section 2 côte 2 (m): 0.35 m; Geom-Ecart à section 2 (m): 0.00001 m; Geom-Ecart à section 1 (m): 0.00001 m
Réduction symétrique | Rez de chaussŽe | 0.5 | 0.5 | 0.4 | 0.862161 | 0.00001 | 0.00001 | 2.13407 | RS | 0.216603 | V_Air_soufflé | 1 | 0.05 | Air soufflé
Réduction symétrique | Rez de chaussŽe | 0.5 | 0.8 | 0.5 | 1.8082 | 0.00001 | 0.00001 | 6.95006 | RS | 0.389808 | V_Air_extrait | 1.08595 | 0.05 | Air extrait

# IfcFlowMovingDevice: Pompe double (4)
In: Rez de chaussŽe
Description: Pompe double
Pset Plancal nova - MEP - Nom: Pompe double; Tech-PN: 16
Name | Tech-Type de connection (filetage=2, bride=3) | Geom-Ø exterieur (m) (m) | Geom-DN | Geom-Longueur (m) (m) | Tech-Epaisseur isolant (m) (m) | Group
2 x Pompe double | 3 | 0.115 | 25 | 0.16 | 0 | Aller
Pompe double | 3 | 0.14 | 32 | 0.18 | 0 | Aller
Pompe double | 2 | 0.165 | 50 | 0.23 | 0.02 | Retour

# IfcFlowMovingDevice: Pompe insérée dans réseau (2)
In: Rez de chaussŽe
Description: Pompe insérée dans réseau; Group: Aller
Pset Plancal nova - MEP - Tech-Type de connection (filetage=2, bride=3): 3; Nom: Pompe insérée dans réseau; Geom-Longueur (m): 0.18 m; Tech-PN: 16; Tech-Epaisseur isolant (m): 0 m
Name | Geom-Ø exterieur (m) (m) | Geom-DN
Pompe insérée dans réseau | 0.105 | 20
Pompe insérée dans réseau | 0.14 | 32

# IfcFlowSegment (40)
Group: Connexion de ventilation
Name | In | Description
FlowSegment 1 | Toiture | Connexion sortie réseau de ventilation
FlowSegment 2 | Toiture | Connexion sortie réseau de ventilation
FlowSegment 3 | Toiture | Connexion sortie réseau de ventilation
FlowSegment 4 | Toiture | Connexion sortie réseau de ventilation
FlowSegment 5 | Toiture | Connexion sortie réseau de ventilation
FlowSegment 6 | Toiture | Connexion sortie réseau de ventilation
FlowSegment 7 | Toiture | Connexion sortie réseau de ventilation
FlowSegment 8 | Toiture | Connexion sortie réseau de ventilation
FlowSegment 9 | R+2 | Connexion sortie réseau de ventilation
FlowSegment 10 | R+2 | Connexion sortie réseau de ventilation
FlowSegment 11 | R+2 | Connexion sortie réseau de ventilation
FlowSegment 12 | R+2 | Connexion sortie réseau de ventilation
FlowSegment 13 | R+2 | Connexion sortie réseau de ventilation
FlowSegment 14 | R+2 | Connexion sortie réseau de ventilation
FlowSegment 15 | R+2 | Connexion centrale réseau de ventilation
FlowSegment 16 | R+2 | Connexion centrale réseau de ventilation
FlowSegment 17 | R+2 | Connexion centrale réseau de ventilation
FlowSegment 18 | R+2 | Connexion centrale réseau de ventilation
FlowSegment 19 | R+2 | Connexion centrale réseau de ventilation
FlowSegment 20 | R+2 | Connexion centrale réseau de ventilation
FlowSegment 21 | R+2 | Connexion centrale réseau de ventilation
FlowSegment 22 | R+2 | Connexion centrale réseau de ventilation
FlowSegment 23 | Mezzannine | Connexion sortie réseau de ventilation
FlowSegment 24 | Mezzannine | Connexion sortie réseau de ventilation
FlowSegment 25 | Mezzannine | Connexion sortie réseau de ventilation
FlowSegment 26 | Mezzannine | Connexion sortie réseau de ventilation
FlowSegment 27 | Mezzannine | Connexion centrale réseau de ventilation
FlowSegment 28 | Mezzannine | Connexion centrale réseau de ventilation
FlowSegment 29 | Mezzannine | Connexion centrale réseau de ventilation
FlowSegment 30 | Mezzannine | Connexion centrale réseau de ventilation
FlowSegment 31 | Mezzannine | Connexion centrale réseau de ventilation
FlowSegment 32 | Mezzannine | Connexion centrale réseau de ventilation
FlowSegment 33 | R+1 | Connexion sortie réseau de ventilation
FlowSegment 34 | R+1 | Connexion sortie réseau de ventilation
FlowSegment 35 | R+1 | Connexion centrale réseau de ventilation
FlowSegment 36 | R+1 | Connexion centrale réseau de ventilation
FlowSegment 37 | R+1 | Connexion centrale réseau de ventilation
FlowSegment 38 | R+1 | Connexion centrale réseau de ventilation
FlowSegment 39 | Rez de chaussŽe | Connexion centrale réseau de ventilation
FlowSegment 40 | Rez de chaussŽe | Connexion centrale réseau de ventilation

# IfcFlowSegment: Anti-vibratile (2)
In: Rez de chaussŽe
Description: Anti-vibratile; Group: Retour
Pset Plancal nova - MEP - Tech-Type de connection (filetage=2, bride=3): 2; Nom: Anti-vibratile; Geom-Ø exterieur (m): 0.125 m; Geom-DN: 50; Geom-Longueur (m): 0.12 m; Tech-PN: 16; Tech-Epaisseur isolant (m): 0.02 m

# IfcFlowSegment: Gaine de ventilation (191)
Description: Gaine de ventilation
Pset Plancal nova - MEP - Nom: Gaine de ventilation; Abbreviation: L; Tech-Materiel (ID): 1; Tech-Epaisseur isolant (m): 0 m
Name | In | Geom-Côte 1 (m) (m) | Geom-Côte 2 (m) (m) | Tech-Poids (kg) (kg) | Geom-Longueur (m) (m) | Tech-Fluide | Geom-Surface (m2) (m2) | Group
Gaine de ventilation | Toiture | 1.3 | 1.2 | 44.3462 | 1.10865 | V_Air_neuf | 5.54327 | Air neuf | Pset Plancal nova - MEP - Calc-Perte de charge (Pa): 0.0000296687 Pa; Calc-Debit vol (m3/s): 0.0555556 m3/s; Calc-Vitesse (m/s): 0.0356125 m/s
2 x Gaine de ventilation | Toiture | 1.3 | 1.2 | 57.065 | 1.42663 | V_Air_rejeté | 7.13313 | Air rejeté
2 x Gaine de ventilation | Toiture | 0.5 | 0.6 | 21.12 | 1.5 | V_Air_soufflé | 3.3 | Air soufflé | Pset Plancal nova - MEP - Calc-Perte de charge (Pa): 0.635419 Pa; Calc-Debit vol (m3/s): 1.38889 m3/s; Calc-Vitesse (m/s): 4.62963 m/s
2 x Gaine de ventilation | Toiture | 1.2 | 1.3 | 41.5584 | 1.03896 | V_Air_rejeté | 5.1948 | Air rejeté
2 x Gaine de ventilation | Toiture | 1.2 | 1.3 | 39.3223 | 0.983056 | V_Air_rejeté | 4.91528 | Air rejeté
Gaine de ventilation | Toiture | 0.9 | 0.6 | 19.2 | 1 | V_Air_extrait | 3 | Air extrait | Pset Plancal nova - MEP - Calc-Perte de charge (Pa): 0.199418 Pa; Calc-Debit vol (m3/s): 2 m3/s; Calc-Vitesse (m/s): 3.7037 m/s
Gaine de ventilation | Toiture | 1 | 0.5 | 21.6178 | 1.12593 | V_Air_soufflé | 3.37778 | Air soufflé | Pset Plancal nova - MEP - Calc-Perte de charge (Pa): 0.269946 Pa; Calc-Debit vol (m3/s): 1.94444 m3/s; Calc-Vitesse (m/s): 3.88889 m/s
Gaine de ventilation | Toiture | 0.5 | 0.8 | 24.96 | 1.5 | V_Air_extrait | 3.9 | Air extrait
Gaine de ventilation | Toiture | 1.3 | 1.2 | 39.8993 | 0.997482 | V_Air_extrait | 4.98741 | Air extrait | Pset Plancal nova - MEP - Calc-Perte de charge (Pa): 0.0325618 Pa; Calc-Debit vol (m3/s): 3.11111 m3/s; Calc-Vitesse (m/s): 1.9943 m/s
6 x Gaine de ventilation | Toiture | 1.2 | 1.3 | 60 | 1.5 | V_Air_rejeté | 7.5 | Air rejeté
Gaine de ventilation | Toiture | 1.3 | 1.2 | 36.8334 | 0.920836 | V_Air_extrait | 4.60418 | Air extrait | Pset Plancal nova - MEP - Calc-Perte de charge (Pa): 0.0300597 Pa; Calc-Debit vol (m3/s): 3.11111 m3/s; Calc-Vitesse (m/s): 1.9943 m/s
Gaine de ventilation | Toiture | 1.2 | 1.2 | 42.5723 | 1.10865 | V_Air_neuf | 5.32154 | Air neuf | Pset Plancal nova - MEP - Calc-Perte de charge (Pa): 0.0000357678 Pa; Calc-Debit vol (m3/s): 0.0555556 m3/s; Calc-Vitesse (m/s): 0.0385802 m/s
Gaine de ventilation | Toiture | 1 | 0.5 | 17.68 | 0.920836 | V_Air_soufflé | 2.76251 | Air soufflé | Pset Plancal nova - MEP - Calc-Perte de charge (Pa): 0.220774 Pa; Calc-Debit vol (m3/s): 1.94444 m3/s; Calc-Vitesse (m/s): 3.88889 m/s
2 x Gaine de ventilation | Toiture | 0.8 | 0.5 | 24.96 | 1.5 | V_Air_extrait | 3.9 | Air extrait | Pset Plancal nova - MEP - Calc-Perte de charge (Pa): 0.538517 Pa; Calc-Debit vol (m3/s): 1.83333 m3/s; Calc-Vitesse (m/s): 4.58333 m/s
Gaine de ventilation | Toiture | 0.6 | 0.5 | 19.1159 | 1.35766 | V_Air_soufflé | 2.98686 | Air soufflé | Pset Plancal nova - MEP - Calc-Perte de charge (Pa): 0.222902 Pa; Calc-Debit vol (m3/s): 0.833333 m3/s; Calc-Vitesse (m/s): 2.77778 m/s
Gaine de ventilation | Toiture | 0.5 | 0.5 | 14.4 | 1.5 | V_Air_soufflé | 3 | Air soufflé
Gaine de ventilation | Toiture | 1 | 0.5 | 28.8 | 1.5 | V_Air_soufflé | 4.5 | Air soufflé | Pset Plancal nova - MEP - Calc-Perte de charge (Pa): 0.359631 Pa; Calc-Debit vol (m3/s): 1.94444 m3/s; Calc-Vitesse (m/s): 3.88889 m/s
Gaine de ventilation | Toiture | 0.5 | 0.8 | 16.64 | 1 | V_Air_extrait | 2.6 | Air extrait | Pset Plancal nova - MEP - Calc-Perte de charge (Pa): 0.359011 Pa; Calc-Debit vol (m3/s): 1.83333 m3/s; Calc-Vitesse (m/s): 4.58333 m/s
Gaine de ventilation | Toiture | 0.9 | 0.6 | 28.8 | 1.5 | V_Air_extrait | 4.5 | Air extrait | Pset Plancal nova - MEP - Calc-Perte de charge (Pa): 0.299127 Pa; Calc-Debit vol (m3/s): 2 m3/s; Calc-Vitesse (m/s): 3.7037 m/s
Gaine de ventilation | Toiture | 0.5 | 0.8 | 16.4525 | 0.988733 | V_Air_extrait | 2.57071 | Air extrait | Pset Plancal nova - MEP - Calc-Perte de charge (Pa): 0.396277 Pa; Calc-Debit vol (m3/s): 1.94444 m3/s; Calc-Vitesse (m/s): 4.86111 m/s
Gaine de ventilation | Toiture | 0.6 | 0.5 | 21.12 | 1.5 | V_Air_soufflé | 3.3 | Air soufflé | Pset Plancal nova - MEP - Calc-Perte de charge (Pa): 0.635419 Pa; Calc-Debit vol (m3/s): 1.38889 m3/s; Calc-Vitesse (m/s): 4.62963 m/s
Gaine de ventilation | Toiture | 0.6 | 0.5 | 15.4496 | 1.09727 | V_Air_soufflé | 2.414 | Air soufflé | Pset Plancal nova - MEP - Calc-Perte de charge (Pa): 0.180151 Pa; Calc-Debit vol (m3/s): 0.833333 m3/s; Calc-Vitesse (m/s): 2.77778 m/s
Gaine de ventilation | Toiture | 0.5 | 0.8 | 16.64 | 1 | V_Air_extrait | 2.6 | Air extrait
Gaine de ventilation | Toiture | 0.6 | 0.9 | 19.2 | 1 | V_Air_extrait | 3 | Air extrait | Pset Plancal nova - MEP - Calc-Perte de charge (Pa): 0.199418 Pa; Calc-Debit vol (m3/s): 2 m3/s; Calc-Vitesse (m/s): 3.7037 m/s
Gaine de ventilation | Toiture | 0.5 | 0.6 | 21.12 | 1.5 | V_Air_soufflé | 3.3 | Air soufflé | Pset Plancal nova - MEP - Calc-Perte de charge (Pa): 0.246271 Pa; Calc-Debit vol (m3/s): 0.833333 m3/s; Calc-Vitesse (m/s): 2.77778 m/s
Gaine de ventilation | Toiture | 0.9 | 0.5 | 24.183 | 1.3495 | V_Air_extrait | 3.7786 | Air extrait
Gaine de ventilation | Toiture | 0.45 | 0.45 | 9.81504 | 1.136 | V_Air_soufflé | 2.0448 | Air soufflé
Gaine de ventilation | Toiture | 0.5 | 0.5 | 9.94082 | 1.0355 | V_Air_extrait | 2.071 | Air extrait
Gaine de ventilation | Toiture | 0.6 | 0.5 | 14.08 | 1 | V_Air_soufflé | 2.2 | Air soufflé
Gaine de ventilation | Toiture | 0.9 | 0.5 | 20.3571 | 1.136 | V_Air_extrait | 3.1808 | Air extrait
Gaine de ventilation | Toiture | 0.5 | 0.8 | 15.575 | 0.936 | V_Air_extrait | 2.4336 | Air extrait
2 x Gaine de ventilation | R+2 | 0.5 | 0.5 | 14.4 | 1.5 | V_Air_extrait | 3 | Air extrait | Pset Plancal nova - MEP - Calc-Perte de charge (Pa): 0.594934 Pa; Calc-Debit vol (m3/s): 1.05556 m3/s; Calc-Vitesse (m/s): 4.22222 m/s
3 x Gaine de ventilation | R+2 | 0.5 | 0.5 | 14.4 | 1.5 | V_Air_extrait | 3 | Air extrait | Pset Plancal nova - MEP - Calc-Perte de charge (Pa): 0.53796 Pa; Calc-Debit vol (m3/s): 1 m3/s; Calc-Vitesse (m/s): 4 m/s
3 x Gaine de ventilation | R+2 | 0.5 | 0.5 | 14.4 | 1.5 | V_Air_extrait | 3 | Air extrait | Pset Plancal nova - MEP - Calc-Perte de charge (Pa): 0.483732 Pa; Calc-Debit vol (m3/s): 0.944444 m3/s; Calc-Vitesse (m/s): 3.77778 m/s
Gaine de ventilation | R+2 | 0.5 | 0.5 | 9.6 | 1 | V_Air_extrait | 2 | Air extrait | Pset Plancal nova - MEP - Calc-Perte de charge (Pa): 0.288173 Pa; Calc-Debit vol (m3/s): 0.888889 m3/s; Calc-Vitesse (m/s): 3.55556 m/s
5 x Gaine de ventilation | R+2 | 0.5 | 0.6 | 21.12 | 1.5 | V_Air_soufflé | 3.3 | Air soufflé | Pset Plancal nova - MEP - Calc-Perte de charge (Pa): 0.635419 Pa; Calc-Debit vol (m3/s): 1.38889 m3/s; Calc-Vitesse (m/s): 4.62963 m/s
Gaine de ventilation | R+2 | 0.5 | 0.6 | 20.6507 | 1.46667 | V_Air_soufflé | 3.22667 | Air soufflé | Pset Plancal nova - MEP - Calc-Perte de charge (Pa): 0.621299 Pa; Calc-Debit vol (m3/s): 1.38889 m3/s; Calc-Vitesse (m/s): 4.62963 m/s
Gaine de ventilation | R+2 | 0.5 | 0.5 | 9.6 | 1 | V_Air_extrait | 2 | Air extrait | Pset Plancal nova - MEP - Calc-Perte de charge (Pa): 0.396623 Pa; Calc-Debit vol (m3/s): 1.05556 m3/s; Calc-Vitesse (m/s): 4.22222 m/s
2 x Gaine de ventilation | R+2 | 0.5 | 0.5 | 14.4 | 1.5 | V_Air_soufflé | 3 | Air soufflé | Pset Plancal nova - MEP - Calc-Perte de charge (Pa): 0.594934 Pa; Calc-Debit vol (m3/s): 1.05556 m3/s; Calc-Vitesse (m/s): 4.22222 m/s
Gaine de ventilation | R+2 | 0.5 | 0.5 | 9.12 | 0.95 | V_Air_soufflé | 1.9 | Air soufflé | Pset Plancal nova - MEP - Calc-Perte de charge (Pa): 0.376792 Pa; Calc-Debit vol (m3/s): 1.05556 m3/s; Calc-Vitesse (m/s): 4.22222 m/s
Gaine de ventilation | R+2 | 0.45 | 0.45 | 12.96 | 1.5 | V_Air_soufflé | 2.7 | Air soufflé | Pset Plancal nova - MEP - Calc-Perte de charge (Pa): 0.727493 Pa; Calc-Debit vol (m3/s): 0.888889 m3/s; Calc-Vitesse (m/s): 4.38957 m/s
Gaine de ventilation | R+2 | 0.45 | 0.45 | 8.424 | 0.975 | V_Air_soufflé | 1.755 | Air soufflé | Pset Plancal nova - MEP - Calc-Perte de charge (Pa): 0.472871 Pa; Calc-Debit vol (m3/s): 0.888889 m3/s; Calc-Vitesse (m/s): 4.38957 m/s
Gaine de ventilation | R+2 | 0.45 | 0.45 | 11.2706 | 1.30446 | V_Air_soufflé | 2.34804 | Air soufflé | Pset Plancal nova - MEP - Calc-Perte de charge (Pa): 0.632659 Pa; Calc-Debit vol (m3/s): 0.888889 m3/s; Calc-Vitesse (m/s): 4.38957 m/s
Gaine de ventilation | R+2 | 0.8 | 0.5 | 24.96 | 1.5 | V_Air_extrait | 3.9 | Air extrait | Pset Plancal nova - MEP - Calc-Perte de charge (Pa): 0.601189 Pa; Calc-Debit vol (m3/s): 1.94444 m3/s; Calc-Vitesse (m/s): 4.86111 m/s
Gaine de ventilation | R+2 | 0.8 | 0.5 | 15.808 | 0.95 | V_Air_extrait | 2.47 | Air extrait | Pset Plancal nova - MEP - Calc-Perte de charge (Pa): 0.380753 Pa; Calc-Debit vol (m3/s): 1.94444 m3/s; Calc-Vitesse (m/s): 4.86111 m/s
Gaine de ventilation | R+2 | 0.5 | 0.5 | 14.4 | 1.5 | V_Air_extrait | 3 | Air extrait | Pset Plancal nova - MEP - Calc-Perte de charge (Pa): 0.717098 Pa; Calc-Debit vol (m3/s): 1.16667 m3/s; Calc-Vitesse (m/s): 4.66667 m/s
Gaine de ventilation | R+2 | 0.5 | 0.5 | 9.1488 | 0.953 | V_Air_extrait | 1.906 | Air extrait | Pset Plancal nova - MEP - Calc-Perte de charge (Pa): 0.455596 Pa; Calc-Debit vol (m3/s): 1.16667 m3/s; Calc-Vitesse (m/s): 4.66667 m/s
5 x Gaine de ventilation | R+2 | 0.9 | 0.5 | 26.88 | 1.5 | V_Air_extrait | 4.2 | Air extrait | Pset Plancal nova - MEP - Calc-Perte de charge (Pa): 0.482154 Pa; Calc-Debit vol (m3/s): 2 m3/s; Calc-Vitesse (m/s): 4.44444 m/s
Gaine de ventilation | R+2 | 0.9 | 0.5 | 17.024 | 0.95 | V_Air_extrait | 2.66 | Air extrait | Pset Plancal nova - MEP - Calc-Perte de charge (Pa): 0.305364 Pa; Calc-Debit vol (m3/s): 2 m3/s; Calc-Vitesse (m/s): 4.44444 m/s
Gaine de ventilation | R+2 | 0.5 | 0.6 | 28.16 | 2 | V_Air_soufflé | 4.4 | Air soufflé | Pset Plancal nova - MEP - Calc-Perte de charge (Pa): 0.847225 Pa; Calc-Debit vol (m3/s): 1.38889 m3/s; Calc-Vitesse (m/s): 4.62963 m/s
Gaine de ventilation | R+2 | 0.5 | 0.6 | 13.2387 | 0.940249 | V_Air_soufflé | 2.06855 | Air soufflé | Pset Plancal nova - MEP - Calc-Perte de charge (Pa): 0.398301 Pa; Calc-Debit vol (m3/s): 1.38889 m3/s; Calc-Vitesse (m/s): 4.62963 m/s
Gaine de ventilation | R+2 | 0.5 | 0.85 | 16.808 | 0.972686 | V_Air_extrait | 2.62625 | Air extrait
14 x Gaine de ventilation | R+2 | 0.5 | 0.5 | 14.4 | 1.5 | V_Air_extrait | 3 | Air extrait
11 x Gaine de ventilation | R+2 | 0.5 | 0.8 | 24.96 | 1.5 | V_Air_extrait | 3.9 | Air extrait
Gaine de ventilation | R+2 | 0.5 | 0.8 | 16.64 | 1 | V_Air_extrait | 2.6 | Air extrait
Gaine de ventilation | R+2 | 0.5 | 0.8 | 16.2125 | 0.974311 | V_Air_extrait | 2.53321 | Air extrait
10 x Gaine de ventilation | R+2 | 0.45 | 0.45 | 12.96 | 1.5 | V_Air_soufflé | 2.7 | Air soufflé
Gaine de ventilation | R+2 | 0.5 | 0.5 | 10.8926 | 1.13464 | V_Air_soufflé | 2.26928 | Air soufflé
Gaine de ventilation | R+2 | 0.5 | 0.8 | 15.5397 | 0.933876 | V_Air_extrait | 2.42808 | Air extrait
Gaine de ventilation | R+2 | 0.45 | 0.45 | 8.64 | 1 | V_Air_soufflé | 1.8 | Air soufflé
8 x Gaine de ventilation | R+2 | 0.5 | 0.5 | 14.4 | 1.5 | V_Air_soufflé | 3 | Air soufflé
Gaine de ventilation | R+2 | 0.5 | 0.5 | 11.4316 | 1.1908 | V_Air_soufflé | 2.38159 | Air soufflé
Gaine de ventilation | R+2 | 0.5 | 0.5 | 9.6 | 1 | V_Air_soufflé | 2 | Air soufflé
10 x Gaine de ventilation | R+2 | 0.5 | 0.9 | 26.88 | 1.5 | V_Air_extrait | 4.2 | Air extrait
Gaine de ventilation | R+2 | 0.9 | 0.5 | 25.3886 | 1.41678 | V_Air_extrait | 3.96697 | Air extrait
Gaine de ventilation | R+2 | 0.5 | 0.85 | 22.9807 | 1.3299 | V_Air_extrait | 3.59074 | Air extrait
9 x Gaine de ventilation | Mezzannine | 0.45 | 0.45 | 12.96 | 1.5 | V_Air_extrait | 2.7 | Air extrait | Pset Plancal nova - MEP - Calc-Perte de charge (Pa): 0.906505 Pa; Calc-Debit vol (m3/s): 1 m3/s; Calc-Vitesse (m/s): 4.93827 m/s
2 x Gaine de ventilation | Mezzannine | 0.5 | 0.9 | 26.88 | 1.5 | V_Air_extrait | 4.2 | Air extrait | Pset Plancal nova - MEP - Calc-Perte de charge (Pa): 0.433359 Pa; Calc-Debit vol (m3/s): 1.88889 m3/s; Calc-Vitesse (m/s): 4.19753 m/s
Gaine de ventilation | Mezzannine | 0.5 | 0.9 | 22.5021 | 1.2557 | V_Air_extrait | 3.51595 | Air extrait | Pset Plancal nova - MEP - Calc-Perte de charge (Pa): 0.362778 Pa; Calc-Debit vol (m3/s): 1.88889 m3/s; Calc-Vitesse (m/s): 4.19753 m/s
2 x Gaine de ventilation | Mezzannine | 0.5 | 0.5 | 14.4 | 1.5 | V_Air_soufflé | 3 | Air soufflé | Pset Plancal nova - MEP - Calc-Perte de charge (Pa): 0.594934 Pa; Calc-Debit vol (m3/s): 1.05556 m3/s; Calc-Vitesse (m/s): 4.22222 m/s
2 x Gaine de ventilation | Mezzannine | 0.45 | 0.45 | 12.96 | 1.5 | V_Air_soufflé | 2.7 | Air soufflé | Pset Plancal nova - MEP - Calc-Perte de charge (Pa): 0.727493 Pa; Calc-Debit vol (m3/s): 0.888889 m3/s; Calc-Vitesse (m/s): 4.38957 m/s
2 x Gaine de ventilation | Mezzannine | 0.8 | 0.5 | 24.96 | 1.5 | V_Air_extrait | 3.9 | Air extrait | Pset Plancal nova - MEP - Calc-Perte de charge (Pa): 0.601189 Pa; Calc-Debit vol (m3/s): 1.94444 m3/s; Calc-Vitesse (m/s): 4.86111 m/s
2 x Gaine de ventilation | Mezzannine | 0.5 | 0.5 | 14.4 | 1.5 | V_Air_extrait | 3 | Air extrait | Pset Plancal nova - MEP - Calc-Perte de charge (Pa): 0.717098 Pa; Calc-Debit vol (m3/s): 1.16667 m3/s; Calc-Vitesse (m/s): 4.66667 m/s
Gaine de ventilation | Mezzannine | 0.9 | 0.4 | 29.3903 | 1.76624 | V_Air_extrait | 4.59224 | Air extrait | Pset Plancal nova - MEP - Calc-Perte de charge (Pa): 1.0336 Pa; Calc-Debit vol (m3/s): 2 m3/s; Calc-Vitesse (m/s): 5.55556 m/s
Gaine de ventilation | Mezzannine | 0.9 | 0.5 | 19.2194 | 1.07251 | V_Air_extrait | 3.00303 | Air extrait | Pset Plancal nova - MEP - Calc-Perte de charge (Pa): 0.344744 Pa; Calc-Debit vol (m3/s): 2 m3/s; Calc-Vitesse (m/s): 4.44444 m/s
Gaine de ventilation | Mezzannine | 0.4 | 0.55 | 18.24 | 1.5 | V_Air_soufflé | 2.85 | Air soufflé
Gaine de ventilation | Mezzannine | 0.4 | 0.55 | 11.0342 | 0.907415 | V_Air_soufflé | 1.72409 | Air soufflé
5 x Gaine de ventilation | Mezzannine | 0.45 | 0.45 | 12.96 | 1.5 | V_Air_extrait | 2.7 | Air extrait
Gaine de ventilation | R+1 | 0.5 | 0.5 | 14.4 | 1.5 | V_Air_extrait | 3 | Air extrait | Pset Plancal nova - MEP - Calc-Perte de charge (Pa): 0.53796 Pa; Calc-Debit vol (m3/s): 1 m3/s; Calc-Vitesse (m/s): 4 m/s
Gaine de ventilation | R+1 | 0.5 | 0.5 | 9.6 | 1 | V_Air_extrait | 2 | Air extrait | Pset Plancal nova - MEP - Calc-Perte de charge (Pa): 0.255701 Pa; Calc-Debit vol (m3/s): 0.833333 m3/s; Calc-Vitesse (m/s): 3.33333 m/s
Gaine de ventilation | R+1 | 0.45 | 0.45 | 12.96 | 1.5 | V_Air_soufflé | 2.7 | Air soufflé | Pset Plancal nova - MEP - Calc-Perte de charge (Pa): 0.645086 Pa; Calc-Debit vol (m3/s): 0.833333 m3/s; Calc-Vitesse (m/s): 4.11523 m/s
2 x Gaine de ventilation | R+1 | 0.5 | 0.5 | 14.4 | 1.5 | V_Air_soufflé | 3 | Air soufflé | Pset Plancal nova - MEP - Calc-Perte de charge (Pa): 0.594934 Pa; Calc-Debit vol (m3/s): 1.05556 m3/s; Calc-Vitesse (m/s): 4.22222 m/s
Gaine de ventilation | R+1 | 0.5 | 0.5 | 9.84 | 1.025 | V_Air_soufflé | 2.05 | Air soufflé | Pset Plancal nova - MEP - Calc-Perte de charge (Pa): 0.406539 Pa; Calc-Debit vol (m3/s): 1.05556 m3/s; Calc-Vitesse (m/s): 4.22222 m/s
2 x Gaine de ventilation | R+1 | 0.8 | 0.5 | 24.96 | 1.5 | V_Air_extrait | 3.9 | Air extrait | Pset Plancal nova - MEP - Calc-Perte de charge (Pa): 0.601189 Pa; Calc-Debit vol (m3/s): 1.94444 m3/s; Calc-Vitesse (m/s): 4.86111 m/s
Gaine de ventilation | R+1 | 0.8 | 0.5 | 17.056 | 1.025 | V_Air_extrait | 2.665 | Air extrait | Pset Plancal nova - MEP - Calc-Perte de charge (Pa): 0.410813 Pa; Calc-Debit vol (m3/s): 1.94444 m3/s; Calc-Vitesse (m/s): 4.86111 m/s
Gaine de ventilation | R+1 | 0.5 | 0.5 | 19.2 | 2 | V_Air_extrait | 4 | Air extrait | Pset Plancal nova - MEP - Calc-Perte de charge (Pa): 0.95613 Pa; Calc-Debit vol (m3/s): 1.16667 m3/s; Calc-Vitesse (m/s): 4.66667 m/s
Gaine de ventilation | R+1 | 0.45 | 0.45 | 12.96 | 1.5 | V_Air_soufflé | 2.7 | Air soufflé
Gaine de ventilation | R+1 | 0.45 | 0.4 | 10.7231 | 1.3141 | V_Air_soufflé | 2.23397 | Air soufflé
Gaine de ventilation | R+1 | 0.45 | 0.45 | 8.64 | 1 | V_Air_soufflé | 1.8 | Air soufflé
Gaine de ventilation | R+1 | 0.45 | 0.45 | 10.1243 | 1.17179 | V_Air_soufflé | 2.10922 | Air soufflé
Gaine de ventilation | Rez de chaussŽe | 0.5 | 0.5 | 14.4 | 1.5 | V_Air_soufflé | 3 | Air soufflé | Pset Plancal nova - MEP - Calc-Perte de charge (Pa): 0.594934 Pa; Calc-Debit vol (m3/s): 1.05556 m3/s; Calc-Vitesse (m/s): 4.22222 m/s
Gaine de ventilation | Rez de chaussŽe | 0.5 | 0.5 | 14.4 | 1.5 | V_Air_soufflé | 3 | Air soufflé | Pset Plancal nova - MEP - Calc-Perte de charge (Pa): 0.53796 Pa; Calc-Debit vol (m3/s): 1 m3/s; Calc-Vitesse (m/s): 4 m/s
Gaine de ventilation | Rez de chaussŽe | 0.5 | 0.5 | 13.4632 | 1.40242 | V_Air_soufflé | 2.80484 | Air soufflé | Pset Plancal nova - MEP - Calc-Perte de charge (Pa): 0.502964 Pa; Calc-Debit vol (m3/s): 1 m3/s; Calc-Vitesse (m/s): 4 m/s
Gaine de ventilation | Rez de chaussŽe | 0.5 | 0.8 | 24.96 | 1.5 | V_Air_extrait | 3.9 | Air extrait | Pset Plancal nova - MEP - Calc-Perte de charge (Pa): 0.601189 Pa; Calc-Debit vol (m3/s): 1.94444 m3/s; Calc-Vitesse (m/s): 4.86111 m/s
Gaine de ventilation | Rez de chaussŽe | 0.5 | 0.8 | 24.96 | 1.5 | V_Air_extrait | 3.9 | Air extrait | Pset Plancal nova - MEP - Calc-Perte de charge (Pa): 0.508425 Pa; Calc-Debit vol (m3/s): 1.77778 m3/s; Calc-Vitesse (m/s): 4.44444 m/s
Gaine de ventilation | Rez de chaussŽe | 0.5 | 0.8 | 16.64 | 1 | V_Air_extrait | 2.6 | Air extrait | Pset Plancal nova - MEP - Calc-Perte de charge (Pa): 0.400793 Pa; Calc-Debit vol (m3/s): 1.94444 m3/s; Calc-Vitesse (m/s): 4.86111 m/s
Gaine de ventilation | Rez de chaussŽe | 0.8 | 0.5 | 16.64 | 1 | V_Air_extrait | 2.6 | Air extrait | Pset Plancal nova - MEP - Calc-Perte de charge (Pa): 0.400793 Pa; Calc-Debit vol (m3/s): 1.94444 m3/s; Calc-Vitesse (m/s): 4.86111 m/s
Gaine de ventilation | Rez de chaussŽe | 0.5 | 0.5 | 9.6 | 1 | V_Air_soufflé | 2 | Air soufflé | Pset Plancal nova - MEP - Calc-Perte de charge (Pa): 0.396623 Pa; Calc-Debit vol (m3/s): 1.05556 m3/s; Calc-Vitesse (m/s): 4.22222 m/s
Gaine de ventilation | Rez de chaussŽe | 0.5 | 0.5 | 14.4 | 1.5 | V_Air_soufflé | 3 | Air soufflé
Gaine de ventilation | Rez de chaussŽe | 0.5 | 0.8 | 19.5898 | 1.17727 | V_Air_extrait | 3.06091 | Air extrait

# IfcFlowSegment: Gaine oblique (2)
In: Toiture
Description: Gaine oblique; Group: Air rejeté
Pset Plancal nova - MEP - Geom-Côte 1 (m): 1.2 m; Geom-Côte 2 (m): 1.3 m; Nom: Gaine oblique; Calc-Perte de charge (Pa): 0.0000516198 Pa; Tech-Poids (kg): 84 kg; Abbreviation: SO; Geom-Longueur (m): 1.6 m; Tech-Fluide: V_Air_rejeté; Geom-Excess length (m): 0.5 m; Tech-Materiel (ID): 1; Geom-Surface (m2): 10.5 m2; Tech-Epaisseur isolant (m): 0 m

# IfcFlowSegment: Manchon (80)
Description: Manchon
Pset Plancal nova - MEP - Nom: Manchon; Abbreviation: MFA; Tech-Materiel (ID): 1; Tech-Epaisseur isolant (m): 0 m
Name | In | Geom-Longueur add (m) (m) | Geom-Ø (m) (m) | Geom-Longueur milieu (m) (m) | Tech-Fluide | Group
2 x Manchon | R+2 | 0.015 | 0.25 | 0.06 | V_Air_extrait | Air extrait
3 x Manchon | R+2 | 0.015 | 0.2 | 0.04 | V_Air_extrait | Air extrait
3 x Manchon | R+2 | 0.015 | 0.16 | 0.04 | V_Air_extrait | Air extrait
2 x Manchon | R+2 | 0.02 | 0.4 | 0.08 | V_Air_extrait | Air extrait
3 x Manchon | R+2 | 0.015 | 0.355 | 0.06 | V_Air_extrait | Air extrait
Manchon | R+2 | 0.02 | 0.45 | 0.08 | V_Air_extrait | Air extrait
Manchon | R+2 | 0.015 | 0.315 | 0.06 | V_Air_extrait | Air extrait
Manchon | R+2 | 0.02 | 0.45 | 0.08 | V_Air_soufflé | Air soufflé
Manchon | R+2 | 0.02 | 0.4 | 0.08 | V_Air_soufflé | Air soufflé
Manchon | R+2 | 0.015 | 0.355 | 0.06 | V_Air_soufflé | Air soufflé
Manchon | R+2 | 0.015 | 0.315 | 0.06 | V_Air_soufflé | Air soufflé
Manchon | R+2 | 0.015 | 0.25 | 0.06 | V_Air_soufflé | Air soufflé
Manchon | R+2 | 0.015 | 0.2 | 0.04 | V_Air_soufflé | Air soufflé
Manchon | Mezzannine | 0.02 | 0.45 | 0.08 | V_Air_soufflé | Air soufflé
Manchon | Mezzannine | 0.015 | 0.315 | 0.06 | V_Air_soufflé | Air soufflé
Manchon | Mezzannine | 0.015 | 0.25 | 0.06 | V_Air_soufflé | Air soufflé
Manchon | Mezzannine | 0.015 | 0.2 | 0.04 | V_Air_soufflé | Air soufflé
Manchon | Mezzannine | 0.02 | 0.5 | 0.08 | V_Air_extrait | Air extrait
2 x Manchon | Mezzannine | 0.02 | 0.45 | 0.08 | V_Air_extrait | Air extrait
2 x Manchon | Mezzannine | 0.02 | 0.4 | 0.08 | V_Air_extrait | Air extrait
2 x Manchon | Mezzannine | 0.015 | 0.355 | 0.06 | V_Air_extrait | Air extrait
2 x Manchon | Mezzannine | 0.015 | 0.315 | 0.06 | V_Air_extrait | Air extrait
4 x Manchon | Mezzannine | 0.015 | 0.25 | 0.06 | V_Air_extrait | Air extrait
4 x Manchon | Mezzannine | 0.015 | 0.2 | 0.04 | V_Air_extrait | Air extrait
4 x Manchon | Mezzannine | 0.015 | 0.16 | 0.04 | V_Air_extrait | Air extrait
Manchon | Mezzannine | 0.015 | 0.16 | 0.04 | V_Air_soufflé | Air soufflé
2 x Manchon | R+1 | 0.015 | 0.25 | 0.06 | V_Air_extrait | Air extrait
4 x Manchon | R+1 | 0.015 | 0.2 | 0.04 | V_Air_extrait | Air extrait
Manchon | R+1 | 0.02 | 0.45 | 0.08 | V_Air_extrait | Air extrait
Manchon | R+1 | 0.02 | 0.4 | 0.08 | V_Air_extrait | Air extrait
Manchon | R+1 | 0.015 | 0.355 | 0.06 | V_Air_extrait | Air extrait
Manchon | R+1 | 0.015 | 0.2 | 0.04 | V_Air_soufflé | Air soufflé
3 x Manchon | R+1 | 0.015 | 0.16 | 0.04 | V_Air_extrait | Air extrait
2 x Manchon | Rez de chaussŽe | 0.015 | 0.355 | 0.06 | V_Air_soufflé | Air soufflé
2 x Manchon | Rez de chaussŽe | 0.015 | 0.315 | 0.06 | V_Air_soufflé | Air soufflé
3 x Manchon | Rez de chaussŽe | 0.015 | 0.25 | 0.06 | V_Air_soufflé | Air soufflé
2 x Manchon | Rez de chaussŽe | 0.015 | 0.2 | 0.04 | V_Air_soufflé | Air soufflé
Manchon | Rez de chaussŽe | 0.02 | 0.4 | 0.08 | V_Air_soufflé | Air soufflé
2 x Manchon | Rez de chaussŽe | 0.02 | 0.5 | 0.08 | V_Air_extrait | Air extrait
Manchon | Rez de chaussŽe | 0.02 | 0.45 | 0.08 | V_Air_extrait | Air extrait
Manchon | Rez de chaussŽe | 0.02 | 0.4 | 0.08 | V_Air_extrait | Air extrait
Manchon | Rez de chaussŽe | 0.015 | 0.355 | 0.06 | V_Air_extrait | Air extrait
2 x Manchon | Rez de chaussŽe | 0.015 | 0.25 | 0.06 | V_Air_extrait | Air extrait
Manchon | Rez de chaussŽe | 0.015 | 0.315 | 0.06 | V_Air_extrait | Air extrait
Manchon | Rez de chaussŽe | 0.015 | 0.16 | 0.04 | V_Air_soufflé | Air soufflé
Manchon | Rez de chaussŽe | 0.015 | 0.16 | 0.04 | V_Désenfumage | Désenfumage

# IfcFlowSegment: PE-HD tuyau (139)
Description: PE-HD tuyau
Pset Plancal nova - MEP - Nom: PE-HD tuyau; Tech-Catalogue: Geberit Evacuation des eaux usées 2012 CH; Tech-Systeme: PE HD; Tech-Nom de produit: PE-HD tuyau
Name | In | Info | Tech-N° d'article | Geom-DN | Tech-Pente (%) | Geom-Longueur (m) (m) | Tech-Fluide | Group
PE-HD tuyau | Toiture | DN 100 | 367.000.16.0 | 100 | 0 | 0.0736677 | S_Eaux_pluviales | Eaux pluviales (EP)
3 x PE-HD tuyau | Toiture | DN 100 | 367.000.16.0 | 100 | 0 | 0.075 | S_Eaux_pluviales | Eaux pluviales (EP)
2 x PE-HD tuyau | R+2 | DN 56 | 363.000.16.0 | 56 | 0 | 0.463054 | S_Eaux_usées | Eaux usées (EU)
PE-HD tuyau | R+2 | DN 100 | 367.000.16.0 | 100 | 0 | 5 | S_Eaux_usées | Eaux usées (EU)
PE-HD tuyau | R+2 | DN 100 | 367.000.16.0 | 100 | 2.55741 | 2.36892 | S_Eaux_pluviales | Eaux pluviales (EP)
PE-HD tuyau | R+2 | DN 125 | 368.000.16.0 | 125 | 0.992834 | 13.6611 | S_Eaux_pluviales | Eaux pluviales (EP)
PE-HD tuyau | R+2 | DN 125 | 368.000.16.0 | 125 | 0.992835 | 17.2991 | S_Eaux_pluviales | Eaux pluviales (EP)
PE-HD tuyau | R+2 | DN 100 | 367.000.16.0 | 100 | 101.409 | 0.505 | S_Eaux_pluviales | Eaux pluviales (EP)
PE-HD tuyau | R+2 | DN 100 | 367.000.16.0 | 100 | 0.992835 | 1.07265 | S_Eaux_pluviales | Eaux pluviales (EP)
PE-HD tuyau | R+2 | DN 125 | 368.000.16.0 | 125 | 0.684538 | 1.00578 | S_Eaux_pluviales | Eaux pluviales (EP)
PE-HD tuyau | R+2 | DN 100 | 367.000.16.0 | 100 | 58.8197 | 0.265666 | S_Eaux_pluviales | Eaux pluviales (EP)
PE-HD tuyau | R+2 | DN 100 | 367.000.16.0 | 100 | 3.75973 | 2.51184 | S_Eaux_pluviales | Eaux pluviales (EP)
PE-HD tuyau | R+2 | DN 100 | 367.000.16.0 | 100 | 33367.1 | 0.439664 | S_Eaux_pluviales | Eaux pluviales (EP)
PE-HD tuyau | R+2 | DN 100 | 367.000.16.0 | 100 | 0 | 0.429927 | S_Eaux_pluviales | Eaux pluviales (EP)
PE-HD tuyau | R+2 | DN 100 | 367.000.16.0 | 100 | 0 | 0.43871 | S_Eaux_pluviales | Eaux pluviales (EP)
PE-HD tuyau | R+2 | DN 100 | 367.000.16.0 | 100 | 0.992835 | 9.18776 | S_Eaux_pluviales | Eaux pluviales (EP)
PE-HD tuyau | R+2 | DN 100 | 367.000.16.0 | 100 | 0.702023 | 2.88154 | S_Eaux_pluviales | Eaux pluviales (EP)
PE-HD tuyau | R+2 | DN 125 | 368.000.16.0 | 125 | 0.469892 | 4.71791 | S_Eaux_pluviales | Eaux pluviales (EP)
PE-HD tuyau | R+2 | DN 125 | 368.000.16.0 | 125 | 0 | 2.12754 | S_Eaux_pluviales | Eaux pluviales (EP)
PE-HD tuyau | R+2 | DN 100 | 367.000.16.0 | 100 | 0.4635 | 3.70194 | S_Eaux_pluviales | Eaux pluviales (EP)
PE-HD tuyau | R+2 | DN 100 | 367.000.16.0 | 100 | 1.47262 | 6.10567 | S_Eaux_pluviales | Eaux pluviales (EP)
PE-HD tuyau | R+2 | DN 100 | 367.000.16.0 | 100 | 0.701971 | 1.51032 | S_Eaux_pluviales | Eaux pluviales (EP)
PE-HD tuyau | R+2 | DN 100 | 367.000.16.0 | 100 | 14245.6 | 0.509581 | S_Eaux_pluviales | Eaux pluviales (EP)
PE-HD tuyau | R+2 | DN 100 | 367.000.16.0 | 100 | 0 | 0.540261 | S_Eaux_usées | Eaux usées (EU)
PE-HD tuyau | R+2 | DN 100 | 367.000.16.0 | 100 | 0 | 0.444469 | S_Eaux_usées | Eaux usées (EU)
PE-HD tuyau | R+2 | DN 100 | 367.000.16.0 | 100 | 0 | 2.93346 | S_Eaux_usées | Eaux usées (EU)
PE-HD tuyau | R+2 | DN 100 | 367.000.16.0 | 100 | 0 | 0.377585 | S_Eaux_usées | Eaux usées (EU)
2 x PE-HD tuyau | R+2 | DN 100 | 367.000.16.0 | 100 | 0 | 0.379813 | S_Eaux_usées | Eaux usées (EU)
PE-HD tuyau | R+2 | DN 100 | 367.000.16.0 | 100 | 0 | 0.987142 | S_Eaux_usées | Eaux usées (EU)
PE-HD tuyau | R+2 | DN 100 | 367.000.16.0 | 100 | 0 | 1.02189 | S_Eaux_usées | Eaux usées (EU)
PE-HD tuyau | Mezzannine | DN 60 | 364.000.16.0 | 60 | 0 | 0.373564 | S_Eaux_usées | Eaux usées (EU)
PE-HD tuyau | Mezzannine | DN 100 | 367.000.16.0 | 100 | 1.7471 | 0.343023 | S_Eaux_usées | Eaux usées (EU)
PE-HD tuyau | Mezzannine | DN 100 | 367.000.16.0 | 100 | 1.74766 | 0.464721 | S_Eaux_usées | Eaux usées (EU)
PE-HD tuyau | Mezzannine | DN 125 | 368.000.16.0 | 125 | 0 | 3.91025 | S_Eaux_pluviales | Eaux pluviales (EP)
PE-HD tuyau | Mezzannine | DN 100 | 367.000.16.0 | 100 | 1497279 | 0.818444 | S_Eaux_usées | Eaux usées (EU)
PE-HD tuyau | Mezzannine | DN 60 | 364.000.16.0 | 60 | 15491.9 | 0.23245 | S_Eaux_usées | Eaux usées (EU)
PE-HD tuyau | Mezzannine | DN 100 | 367.000.16.0 | 100 | 0 | 0.877337 | S_Eaux_usées | Eaux usées (EU)
PE-HD tuyau | Mezzannine | DN 100 | 367.000.16.0 | 100 | 0 | 2.29392 | S_Eaux_usées | Eaux usées (EU)
PE-HD tuyau | Mezzannine | DN 100 | 367.000.16.0 | 100 | 0 | 1.33603 | S_Eaux_usées | Eaux usées (EU)
PE-HD tuyau | Mezzannine | DN 100 | 367.000.16.0 | 100 | 1.83359 | 0.739729 | S_Eaux_usées | Eaux usées (EU)
PE-HD tuyau | Mezzannine | DN 60 | 364.000.16.0 | 60 | 0 | 0.381175 | S_Eaux_usées | Eaux usées (EU)
PE-HD tuyau | Mezzannine | DN 60 | 364.000.16.0 | 60 | 0.0831973 | 0.174479 | S_Eaux_usées | Eaux usées (EU)
PE-HD tuyau | Mezzannine | DN 60 | 364.000.16.0 | 60 | 1.5 | 0.801903 | S_Eaux_usées | Eaux usées (EU)
PE-HD tuyau | Mezzannine | DN 60 | 364.000.16.0 | 60 | 1.55282 | 1.45495 | S_Eaux_usées | Eaux usées (EU)
2 x PE-HD tuyau | Mezzannine | DN 56 | 363.000.16.0 | 56 | 0 | 0.463054 | S_Eaux_usées | Eaux usées (EU)
PE-HD tuyau | Mezzannine | DN 60 | 364.000.16.0 | 60 | 2.17788 | 0.12023 | S_Eaux_usées | Eaux usées (EU)
PE-HD tuyau | R+1 | DN 100 | 367.000.16.0 | 100 | 1.74766 | 0.464721 | S_Eaux_usées | Eaux usées (EU)
PE-HD tuyau | R+1 | DN 100 | 367.000.16.0 | 100 | 1.7471 | 0.343023 | S_Eaux_usées | Eaux usées (EU)
PE-HD tuyau | R+1 | DN 125 | 368.000.16.0 | 125 | 0 | 3.91025 | S_Eaux_pluviales | Eaux pluviales (EP)
PE-HD tuyau | R+1 | DN 100 | 367.000.16.0 | 100 | 0 | 2.29388 | S_Eaux_usées | Eaux usées (EU)
PE-HD tuyau | R+1 | DN 100 | 367.000.16.0 | 100 | 0 | 0.877337 | S_Eaux_usées | Eaux usées (EU)
PE-HD tuyau | R+1 | DN 100 | 367.000.16.0 | 100 | 1497368 | 0.818524 | S_Eaux_usées | Eaux usées (EU)
PE-HD tuyau | R+1 | DN 100 | 367.000.16.0 | 100 | 0 | 1.33607 | S_Eaux_usées | Eaux usées (EU)
PE-HD tuyau | R+1 | DN 60 | 364.000.16.0 | 60 | 15495.1 | 0.232489 | S_Eaux_usées | Eaux usées (EU)
PE-HD tuyau | R+1 | DN 100 | 367.000.16.0 | 100 | 1.84321 | 0.73973 | S_Eaux_usées | Eaux usées (EU)
PE-HD tuyau | R+1 | DN 60 | 364.000.16.0 | 60 | 0 | 0.373564 | S_Eaux_usées | Eaux usées (EU)
PE-HD tuyau | R+1 | DN 60 | 364.000.16.0 | 60 | 1.55282 | 1.45495 | S_Eaux_usées | Eaux usées (EU)
PE-HD tuyau | R+1 | DN 60 | 364.000.16.0 | 60 | 0.0831973 | 0.174479 | S_Eaux_usées | Eaux usées (EU)
2 x PE-HD tuyau | R+1 | DN 56 | 363.000.16.0 | 56 | 0 | 0.463054 | S_Eaux_usées | Eaux usées (EU)
PE-HD tuyau | R+1 | DN 60 | 364.000.16.0 | 60 | 1.5 | 0.801903 | S_Eaux_usées | Eaux usées (EU)
PE-HD tuyau | R+1 | DN 60 | 364.000.16.0 | 60 | 0 | 0.381175 | S_Eaux_usées | Eaux usées (EU)
PE-HD tuyau | R+1 | DN 60 | 364.000.16.0 | 60 | 2.18754 | 0.1197 | S_Eaux_usées | Eaux usées (EU)
PE-HD tuyau | Rez de chaussŽe | DN 150 | 369.000.16.0 | 150 | 0 | 0.242472 | S_Eaux_pluviales | Eaux pluviales (EP)
PE-HD tuyau | Rez de chaussŽe | DN 150 | 369.000.16.0 | 150 | 0 | 0.44916 | S_Eaux_pluviales | Eaux pluviales (EP)
PE-HD tuyau | Rez de chaussŽe | DN 150 | 369.000.16.0 | 150 | 0 | 7.1435 | S_Eaux_pluviales | Eaux pluviales (EP)
PE-HD tuyau | Rez de chaussŽe | DN 150 | 369.000.16.0 | 150 | 0 | 20.5437 | S_Eaux_pluviales | Eaux pluviales (EP)
PE-HD tuyau | Rez de chaussŽe | DN 150 | 369.000.16.0 | 150 | 0 | 9.85303 | S_Eaux_pluviales | Eaux pluviales (EP)
PE-HD tuyau | Rez de chaussŽe | DN 150 | 369.000.16.0 | 150 | 0 | 30.0782 | S_Eaux_pluviales | Eaux pluviales (EP)
PE-HD tuyau | Rez de chaussŽe | DN 150 | 369.000.16.0 | 150 | 0 | 0.589931 | S_Eaux_pluviales | Eaux pluviales (EP)
PE-HD tuyau | Rez de chaussŽe | DN 150 | 369.000.16.0 | 150 | 0 | 0.333328 | S_Eaux_pluviales | Eaux pluviales (EP)
PE-HD tuyau | Rez de chaussŽe | DN 150 | 369.000.16.0 | 150 | 0 | 4.65531 | S_Eaux_pluviales | Eaux pluviales (EP)
PE-HD tuyau | Rez de chaussŽe | DN 150 | 369.000.16.0 | 150 | 0 | 2.25555 | S_Eaux_pluviales | Eaux pluviales (EP)
PE-HD tuyau | Rez de chaussŽe | DN 150 | 369.000.16.0 | 150 | 0 | 34.1599 | S_Eaux_pluviales | Eaux pluviales (EP)
PE-HD tuyau | Rez de chaussŽe | DN 150 | 369.000.16.0 | 150 | 0 | 18.8776 | S_Eaux_pluviales | Eaux pluviales (EP)
PE-HD tuyau | Rez de chaussŽe | DN 150 | 369.000.16.0 | 150 | 0 | 10.8142 | S_Eaux_pluviales | Eaux pluviales (EP)
PE-HD tuyau | Rez de chaussŽe | DN 150 | 369.000.16.0 | 150 | 0 | 72.0015 | S_Eaux_pluviales | Eaux pluviales (EP)
PE-HD tuyau | Rez de chaussŽe | DN 150 | 369.000.16.0 | 150 | 0 | 1.68506 | S_Eaux_pluviales | Eaux pluviales (EP)
PE-HD tuyau | Rez de chaussŽe | DN 150 | 369.000.16.0 | 150 | 0 | 2.55462 | S_Eaux_pluviales | Eaux pluviales (EP)
PE-HD tuyau | Rez de chaussŽe | DN 100 | 367.000.16.0 | 100 | 1.5 | 0.707214 | S_Eaux_usées | Eaux usées (EU)
PE-HD tuyau | Rez de chaussŽe | DN 100 | 367.000.16.0 | 100 | 1.50002 | 0.389913 | S_Eaux_usées | Eaux usées (EU)
PE-HD tuyau | Rez de chaussŽe | DN 100 | 367.000.16.0 | 100 | 1.47029 | 1.31648 | S_Eaux_usées | Eaux usées (EU)
PE-HD tuyau | Rez de chaussŽe | DN 100 | 367.000.16.0 | 100 | 1.74332 | 0.505035 | S_Eaux_usées | Eaux usées (EU)
PE-HD tuyau | Rez de chaussŽe | DN 100 | 367.000.16.0 | 100 | 1.5 | 4.1188 | S_Eaux_usées | Eaux usées (EU)
PE-HD tuyau | Rez de chaussŽe | DN 100 | 367.000.16.0 | 100 | 0 | 0.991036 | S_Eaux_usées | Eaux usées (EU)
PE-HD tuyau | Rez de chaussŽe | DN 100 | 367.000.16.0 | 100 | 0 | 0.908229 | S_Eaux_usées | Eaux usées (EU)
PE-HD tuyau | Rez de chaussŽe | DN 100 | 367.000.16.0 | 100 | 0 | 0.937348 | S_Eaux_usées | Eaux usées (EU)
PE-HD tuyau | Rez de chaussŽe | DN 100 | 367.000.16.0 | 100 | 1.5 | 9.6921 | S_Eaux_usées | Eaux usées (EU)
PE-HD tuyau | Rez de chaussŽe | DN 125 | 368.000.16.0 | 125 | 2 | 5.11385 | S_Eaux_pluviales | Eaux pluviales (EP)
PE-HD tuyau | Rez de chaussŽe | DN 125 | 368.000.16.0 | 125 | 2 | 0.994756 | S_Eaux_pluviales | Eaux pluviales (EP)
PE-HD tuyau | Rez de chaussŽe | DN 125 | 368.000.16.0 | 125 | 2 | 1.54588 | S_Eaux_pluviales | Eaux pluviales (EP)
PE-HD tuyau | Rez de chaussŽe | DN 125 | 368.000.16.0 | 125 | 2 | 0.902241 | S_Eaux_pluviales | Eaux pluviales (EP)
PE-HD tuyau | Rez de chaussŽe | DN 100 | 367.000.16.0 | 100 | 1.0606 | 8 | S_Eaux_usées | Eaux usées (EU)
PE-HD tuyau | Rez de chaussŽe | DN 100 | 367.000.16.0 | 100 | 0 | 4.8 | S_Eaux_usées | Eaux usées (EU)
PE-HD tuyau | Rez de chaussŽe | DN 125 | 368.000.16.0 | 125 | 2 | 1.95082 | S_Eaux_pluviales | Eaux pluviales (EP)
PE-HD tuyau | Rez de chaussŽe | DN 125 | 368.000.16.0 | 125 | 2 | 13.0581 | S_Eaux_pluviales | Eaux pluviales (EP)
PE-HD tuyau | Rez de chaussŽe | DN 125 | 368.000.16.0 | 125 | 1.41431 | 2.95792 | S_Eaux_pluviales | Eaux pluviales (EP)
PE-HD tuyau | Rez de chaussŽe | DN 125 | 368.000.16.0 | 125 | 2 | 1.51669 | S_Eaux_pluviales | Eaux pluviales (EP)
PE-HD tuyau | Rez de chaussŽe | DN 125 | 368.000.16.0 | 125 | 1.41431 | 2.45 | S_Eaux_pluviales | Eaux pluviales (EP)
PE-HD tuyau | Rez de chaussŽe | DN 100 | 367.000.16.0 | 100 | 1.49994 | 2.9739 | S_Eaux_usées | Eaux usées (EU)
PE-HD tuyau | Rez de chaussŽe | DN 100 | 367.000.16.0 | 100 | 1.5 | 1.84998 | S_Eaux_usées | Eaux usées (EU)
PE-HD tuyau | Rez de chaussŽe | DN 100 | 367.000.16.0 | 100 | 1.62514 | 0.589281 | S_Eaux_usées | Eaux usées (EU)
PE-HD tuyau | Rez de chaussŽe | DN 100 | 367.000.16.0 | 100 | 6641.51 | 0.426 | S_Eaux_usées | Eaux usées (EU)
PE-HD tuyau | Rez de chaussŽe | DN 100 | 367.000.16.0 | 100 | 103.044 | 0.109994 | S_Eaux_usées | Eaux usées (EU)
PE-HD tuyau | Rez de chaussŽe | DN 100 | 367.000.16.0 | 100 | 1.5 | 0.0455632 | S_Eaux_usées | Eaux usées (EU)
PE-HD tuyau | Rez de chaussŽe | DN 100 | 367.000.16.0 | 100 | 0.62146 | 0.00720262 | S_Eaux_usées | Eaux usées (EU)
PE-HD tuyau | Rez de chaussŽe | DN 100 | 367.000.16.0 | 100 | 1.54175 | 0.818481 | S_Eaux_usées | Eaux usées (EU)
PE-HD tuyau | Rez de chaussŽe | DN 100 | 367.000.16.0 | 100 | 1.74766 | 0.464721 | S_Eaux_usées | Eaux usées (EU)
PE-HD tuyau | Rez de chaussŽe | DN 100 | 367.000.16.0 | 100 | 1.7471 | 0.343023 | S_Eaux_usées | Eaux usées (EU)
PE-HD tuyau | Rez de chaussŽe | DN 100 | 367.000.16.0 | 100 | 0 | 3.40984 | S_Eaux_usées | Eaux usées (EU)
PE-HD tuyau | Rez de chaussŽe | DN 100 | 367.000.16.0 | 100 | 1.85202 | 0.739732 | S_Eaux_usées | Eaux usées (EU)
PE-HD tuyau | Rez de chaussŽe | DN 50 | 361.000.16.0 | 50 | 0 | 0.106287 | S_Eaux_usées | Eaux usées (EU)
PE-HD tuyau | Rez de chaussŽe | DN 50 | 361.000.16.0 | 50 | 0 | 0.066 | S_Eaux_usées | Eaux usées (EU)
PE-HD tuyau | Rez de chaussŽe | DN 60 | 364.000.16.0 | 60 | 1.5 | 0.801903 | S_Eaux_usées | Eaux usées (EU)
PE-HD tuyau | Rez de chaussŽe | DN 56 | 363.000.16.0 | 56 | 0 | 0.463054 | S_Eaux_usées | Eaux usées (EU)
PE-HD tuyau | Rez de chaussŽe | DN 60 | 364.000.16.0 | 60 | 1.55282 | 1.45495 | S_Eaux_usées | Eaux usées (EU)
PE-HD tuyau | Rez de chaussŽe | DN 60 | 364.000.16.0 | 60 | 0.0831973 | 0.174479 | S_Eaux_usées | Eaux usées (EU)
PE-HD tuyau | Rez de chaussŽe | DN 60 | 364.000.16.0 | 60 | 0 | 0.615122 | S_Eaux_usées | Eaux usées (EU)
PE-HD tuyau | Rez de chaussŽe | DN 60 | 364.000.16.0 | 60 | 0 | 0.596733 | S_Eaux_usées | Eaux usées (EU)
PE-HD tuyau | Rez de chaussŽe | DN 100 | 367.000.16.0 | 100 | 0 | 1.4136 | S_Eaux_usées | Eaux usées (EU)
PE-HD tuyau | Rez de chaussŽe | DN 125 | 368.000.16.0 | 125 | 0 | 5.1537 | S_Eaux_pluviales | Eaux pluviales (EP)
PE-HD tuyau | Rez de chaussŽe | DN 125 | 368.000.16.0 | 125 | 100.033 | 0.0511712 | S_Eaux_pluviales | Eaux pluviales (EP)
PE-HD tuyau | Rez de chaussŽe | DN 125 | 368.000.16.0 | 125 | 0 | 0.108145 | S_Eaux_pluviales | Eaux pluviales (EP)
PE-HD tuyau | Rez de chaussŽe | DN 125 | 368.000.16.0 | 125 | 0 | 0.934 | S_Eaux_pluviales | Eaux pluviales (EP)
PE-HD tuyau | Rez de chaussŽe | DN 56 | 363.000.16.0 | 56 | 0 | 0.459197 | S_Eaux_usées | Eaux usées (EU)
PE-HD tuyau | Rez de chaussŽe | DN 100 | 367.000.16.0 | 100 | 0 | 0.146099 | S_Eaux_usées | Eaux usées (EU)
PE-HD tuyau | Rez de chaussŽe | DN 100 | 367.000.16.0 | 100 | 0 | 0.156188 | S_Eaux_usées | Eaux usées (EU)
PE-HD tuyau | Rez de chaussŽe | DN 100 | 367.000.16.0 | 100 | 0 | 0.496 | S_Eaux_usées | Eaux usées (EU)
PE-HD tuyau | Rez de chaussŽe | DN 100 | 367.000.16.0 | 100 | 0 | 0.620405 | S_Eaux_usées | Eaux usées (EU)
PE-HD tuyau | Rez de chaussŽe | DN 100 | 367.000.16.0 | 100 | 0 | 0.416107 | S_Eaux_usées | Eaux usées (EU)
PE-HD tuyau | Rez de chaussŽe | DN 60 | 364.000.16.0 | 60 | 15501 | 0.233255 | S_Eaux_usées | Eaux usées (EU)
PE-HD tuyau | Rez de chaussŽe | DN 60 | 364.000.16.0 | 60 | 1.4942 | 0.12025 | S_Eaux_usées | Eaux usées (EU)
PE-HD tuyau | Rez de chaussŽe | DN 100 | 367.000.16.0 | 100 | 1497529 | 1.01817 | S_Eaux_usées | Eaux usées (EU)
PE-HD tuyau | Rez de chaussŽe | DN 100 | 367.000.16.0 | 100 | 0 | 1.07875 | S_Eaux_usées | Eaux usées (EU)

# IfcFlowSegment: Partie de gaine de ventilation (63)
Description: Partie de gaine de ventilation
Pset Plancal nova - MEP - Nom: Partie de gaine de ventilation; Abbreviation: LT; Tech-Materiel (ID): 1; Tech-Epaisseur isolant (m): 0 m
Name | In | Geom-Côte 1 (m) (m) | Geom-Côte 2 (m) (m) | Calc-Perte de charge (Pa) (Pa) | Tech-Poids (kg) (kg) | Geom-Longueur (m) (m) | Tech-Fluide | Geom-Surface (m2) (m2) | Calc-Debit vol (m3/s) (m3/s) | Calc-Vitesse (m/s) (m/s) | Group
Partie de gaine de ventilation | Toiture | 0.5 | 0.5 | 0.218143 | 5.28 | 0.55 | V_Air_soufflé | 1.1 | 1.05556 | 4.22222 | Air soufflé
Partie de gaine de ventilation | Toiture | 0.5 | 0.5 | 0.0705709 | 1.41713 | 0.147618 | V_Air_extrait | 1 | 1.16667 | 4.66667 | Air extrait
Partie de gaine de ventilation | Toiture | 0.5 | 0.8 | 0.287209 | 13.312 | 0.8 | V_Air_extrait | 2.08 | 1.83333 | 4.58333 | Air extrait
Partie de gaine de ventilation | Toiture | 0.5 | 0.8 | 0.277291 | 12.8523 | 0.772373 | V_Air_extrait | 2.00817 | 1.83333 | 4.58333 | Air extrait
Partie de gaine de ventilation | Toiture | 0.5 | 0.5 | 0.294014 | 7.11641 | 0.741293 | V_Air_soufflé | 1.48259 | 1.05556 | 4.22222 | Air soufflé
Partie de gaine de ventilation | Toiture | 0.8 | 0.5 | 0.146356 | 6.78351 | 0.407663 | V_Air_extrait | 1.05992 | 1.83333 | 4.58333 | Air extrait
Partie de gaine de ventilation | Toiture | 0.6 | 0.5 | 0.233196 | 7.75093 | 0.550493 | V_Air_soufflé | 1.21108 | 1.38889 | 4.62963 | Air soufflé
Partie de gaine de ventilation | Toiture | 0.5 | 0.5 | 0.17848 | 4.32 | 0.45 | V_Air_soufflé | 1 | 1.05556 | 4.22222 | Air soufflé
Partie de gaine de ventilation | Toiture | 0.6 | 0.9 | 0.114142 | 10.9896 | 0.572373 | V_Air_extrait | 1.71712 | 2 | 3.7037 | Air extrait
Partie de gaine de ventilation | Toiture | 0.9 | 0.6 | 0.153693 | 14.7975 | 0.770705 | V_Air_extrait | 2.31212 | 2 | 3.7037 | Air extrait
Partie de gaine de ventilation | Toiture | 0.5 | 0.8 | 0.233357 | 10.816 | 0.65 | V_Air_extrait | 1.69 | 1.83333 | 4.58333 | Air extrait
Partie de gaine de ventilation | Toiture | 0.5 | 0.6 | 0.193872 | 6.44389 | 0.457663 | V_Air_soufflé | 1.00686 | 1.38889 | 4.62963 | Air soufflé
Partie de gaine de ventilation | Toiture | 0.6 | 0.5 |  | 11.0669 | 0.786 | V_Air_soufflé | 1.7292 |  |  | Air soufflé
Partie de gaine de ventilation | Toiture | 0.45 | 0.45 |  | 3.76272 | 0.4355 | V_Air_soufflé | 1 |  |  | Air soufflé
Partie de gaine de ventilation | Toiture | 0.45 | 0.45 |  | 3.14496 | 0.364 | V_Air_soufflé | 1 |  |  | Air soufflé
Partie de gaine de ventilation | Toiture | 0.5 | 0.5 |  | 4.1856 | 0.436 | V_Air_soufflé | 1 |  |  | Air soufflé
Partie de gaine de ventilation | Toiture | 0.5 | 0.8 |  | 8.91904 | 0.536 | V_Air_extrait | 1.3936 |  |  | Air extrait
Partie de gaine de ventilation | R+2 | 0.5 | 0.5 | 0.176494 | 5.87961 | 0.612459 | V_Air_extrait | 1.22492 | 0.888889 | 3.55556 | Air extrait
Partie de gaine de ventilation | R+2 | 0.5 | 0.6 | 0.255139 | 8.4803 | 0.602294 | V_Air_soufflé | 1.32505 | 1.38889 | 4.62963 | Air soufflé
Partie de gaine de ventilation | R+2 | 0.5 | 0.5 | 0.215153 | 5.20764 | 0.542462 | V_Air_extrait | 1.08492 | 1.05556 | 4.22222 | Air extrait
Partie de gaine de ventilation | R+2 | 0.5 | 0.5 | 0.199501 | 4.8288 | 0.503 | V_Air_extrait | 1.006 | 1.05556 | 4.22222 | Air extrait
Partie de gaine de ventilation | R+2 | 0.5 | 0.5 | 0.323573 | 7.83189 | 0.815821 | V_Air_extrait | 1.63164 | 1.05556 | 4.22222 | Air extrait
Partie de gaine de ventilation | R+2 | 0.5 | 0.5 | 0.0793246 | 1.92 | 0.2 | V_Air_soufflé | 1 | 1.05556 | 4.22222 | Air soufflé
Partie de gaine de ventilation | R+2 | 0.45 | 0.45 | 0.109124 | 1.944 | 0.225 | V_Air_soufflé | 1 | 0.888889 | 4.38957 | Air soufflé
Partie de gaine de ventilation | R+2 | 0.8 | 0.5 | 0.0801586 | 3.328 | 0.2 | V_Air_extrait | 1 | 1.94444 | 4.86111 | Air extrait
Partie de gaine de ventilation | R+2 | 0.5 | 0.5 | 0.0239033 | 0.48 | 0.05 | V_Air_extrait | 1 | 1.16667 | 4.66667 | Air extrait
Partie de gaine de ventilation | R+2 | 0.6 | 0.5 | 0.0635419 | 2.112 | 0.15 | V_Air_soufflé | 1 | 1.38889 | 4.62963 | Air soufflé
Partie de gaine de ventilation | R+2 | 0.9 | 0.5 | 0.0642872 | 3.584 | 0.2 | V_Air_extrait | 1 | 2 | 4.44444 | Air extrait
Partie de gaine de ventilation | R+2 | 0.8 | 0.5 | 0.0538517 | 2.496 | 0.15 | V_Air_extrait | 1 | 1.83333 | 4.58333 | Air extrait
Partie de gaine de ventilation | R+2 | 0.5 | 0.6 | 0.0987747 | 11.0204 | 0.782699 | V_Air_soufflé | 1.72194 | 0.722222 | 2.40741 | Air soufflé
Partie de gaine de ventilation | R+2 | 0.5 | 0.5 | 0.0717098 | 1.44 | 0.15 | V_Air_extrait | 1 | 1.16667 | 4.66667 | Air extrait
Partie de gaine de ventilation | R+2 | 0.5 | 0.8 |  | 11.7003 | 0.703143 | V_Air_extrait | 1.82817 |  |  | Air extrait
Partie de gaine de ventilation | R+2 | 0.5 | 0.5 |  | 4.61253 | 0.480472 | V_Air_extrait | 1 |  |  | Air extrait
Partie de gaine de ventilation | R+2 | 0.45 | 0.45 |  | 4.72715 | 0.547123 | V_Air_soufflé | 1 |  |  | Air soufflé
Partie de gaine de ventilation | R+2 | 0.5 | 0.5 |  | 8.32594 | 0.867285 | V_Air_extrait | 1.73457 |  |  | Air extrait
Partie de gaine de ventilation | R+2 | 0.5 | 0.5 |  | 3.32814 | 0.346681 | V_Air_extrait | 1 |  |  | Air extrait
Partie de gaine de ventilation | R+2 | 0.5 | 0.8 |  | 7.22708 | 0.43432 | V_Air_extrait | 1.12923 |  |  | Air extrait
Partie de gaine de ventilation | R+2 | 0.45 | 0.45 |  | 6.92734 | 0.801776 | V_Air_soufflé | 1.4432 |  |  | Air soufflé
Partie de gaine de ventilation | R+2 | 0.45 | 0.45 |  | 6.58784 | 0.762482 | V_Air_soufflé | 1.37247 |  |  | Air soufflé
Partie de gaine de ventilation | R+2 | 0.45 | 0.45 |  | 4.69762 | 0.543706 | V_Air_soufflé | 1 |  |  | Air soufflé
Partie de gaine de ventilation | R+2 | 0.5 | 0.5 |  | 8.46977 | 0.882268 | V_Air_soufflé | 1.76454 |  |  | Air soufflé
Partie de gaine de ventilation | R+2 | 0.5 | 0.5 |  | 6.57246 | 0.684631 | V_Air_soufflé | 1.36926 |  |  | Air soufflé
Partie de gaine de ventilation | R+2 | 0.5 | 0.9 |  | 8.10624 | 0.452357 | V_Air_extrait | 1.2666 |  |  | Air extrait
Partie de gaine de ventilation | R+2 | 0.5 | 0.9 |  | 4.23889 | 0.236545 | V_Air_extrait | 1 |  |  | Air extrait
Partie de gaine de ventilation | Mezzannine | 0.45 | 0.45 | 0.418171 | 5.97845 | 0.69195 | V_Air_extrait | 1.24551 | 1 | 4.93827 | Air extrait
Partie de gaine de ventilation | Mezzannine | 0.5 | 0.5 | 0.208227 | 5.04 | 0.525 | V_Air_soufflé | 1.05 | 1.05556 | 4.22222 | Air soufflé
Partie de gaine de ventilation | Mezzannine | 0.45 | 0.45 | 0.254623 | 4.536 | 0.525 | V_Air_soufflé | 1 | 0.888889 | 4.38957 | Air soufflé
Partie de gaine de ventilation | Mezzannine | 0.8 | 0.5 | 0.210416 | 8.736 | 0.525 | V_Air_extrait | 1.365 | 1.94444 | 4.86111 | Air extrait
Partie de gaine de ventilation | Mezzannine | 0.5 | 0.5 | 0.24955 | 5.0112 | 0.522 | V_Air_extrait | 1.044 | 1.16667 | 4.66667 | Air extrait
Partie de gaine de ventilation | Mezzannine | 0.9 | 0.5 | 0.11411 | 6.3616 | 0.355 | V_Air_extrait | 1 | 2 | 4.44444 | Air extrait
Partie de gaine de ventilation | Mezzannine | 0.55 | 0.45 | 0.0398676 | 1.93501 | 0.151172 | V_Air_soufflé | 1 | 0.833333 | 3.367 | Air soufflé
Partie de gaine de ventilation | Mezzannine | 0.45 | 0.45 |  | 7.46032 | 0.863463 | V_Air_extrait | 1.55423 |  |  | Air extrait
Partie de gaine de ventilation | R+1 | 0.5 | 0.5 | 0.140187 | 5.26319 | 0.548249 | V_Air_extrait | 1.0965 | 0.833333 | 3.33333 | Air extrait
Partie de gaine de ventilation | R+1 | 0.45 | 0.45 | 0.424371 | 7.56 | 0.875 | V_Air_soufflé | 1.575 | 0.888889 | 4.38957 | Air soufflé
Partie de gaine de ventilation | R+1 | 0.65 | 0.35 | 0.428723 | 8.576 | 0.67 | V_Air_extrait | 1.34 | 1.16667 | 5.12821 | Air extrait
Partie de gaine de ventilation | R+1 | 0.65 | 0.35 | 0.549857 | 10.9991 | 0.859305 | V_Air_extrait | 1.71861 | 1.16667 | 5.12821 | Air extrait
Partie de gaine de ventilation | R+1 | 0.5 | 0.5 | 0.0524728 | 1.40458 | 0.146311 | V_Air_extrait | 1 | 1 | 4 | Air extrait
Partie de gaine de ventilation | R+1 | 0.35 | 0.65 |  | 7.77876 | 0.607716 | V_Air_extrait | 1.21543 |  |  | Air extrait
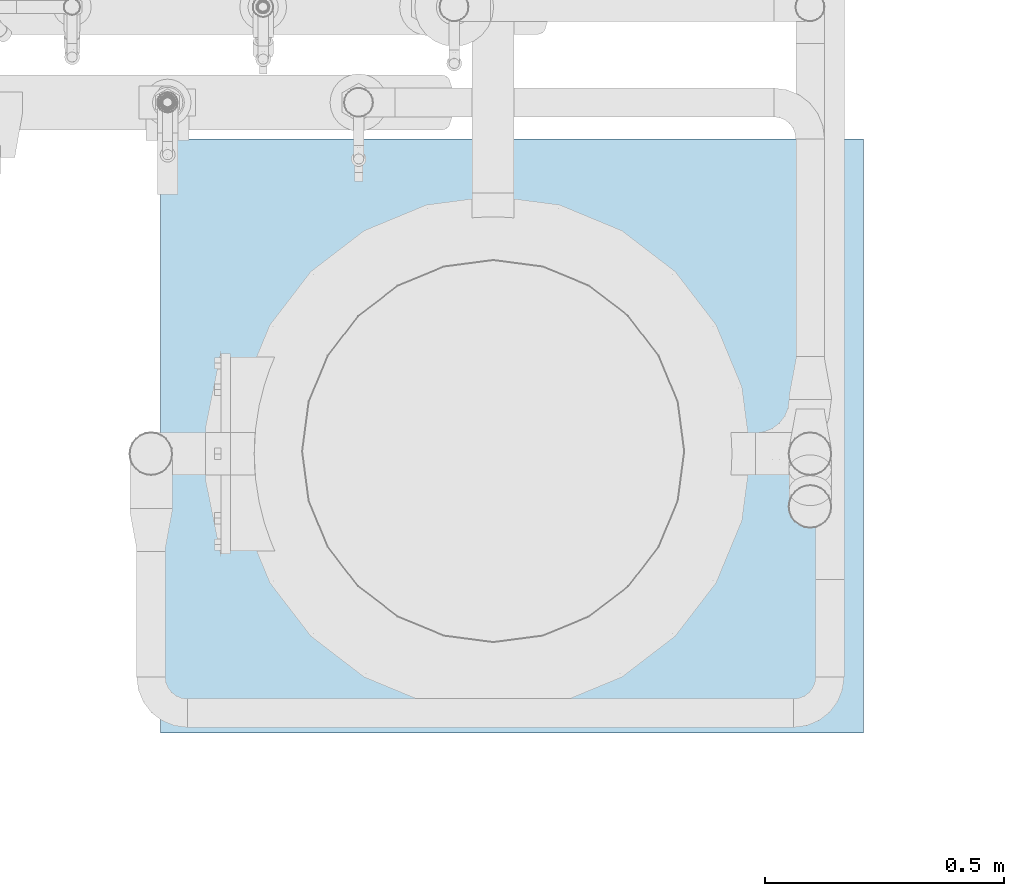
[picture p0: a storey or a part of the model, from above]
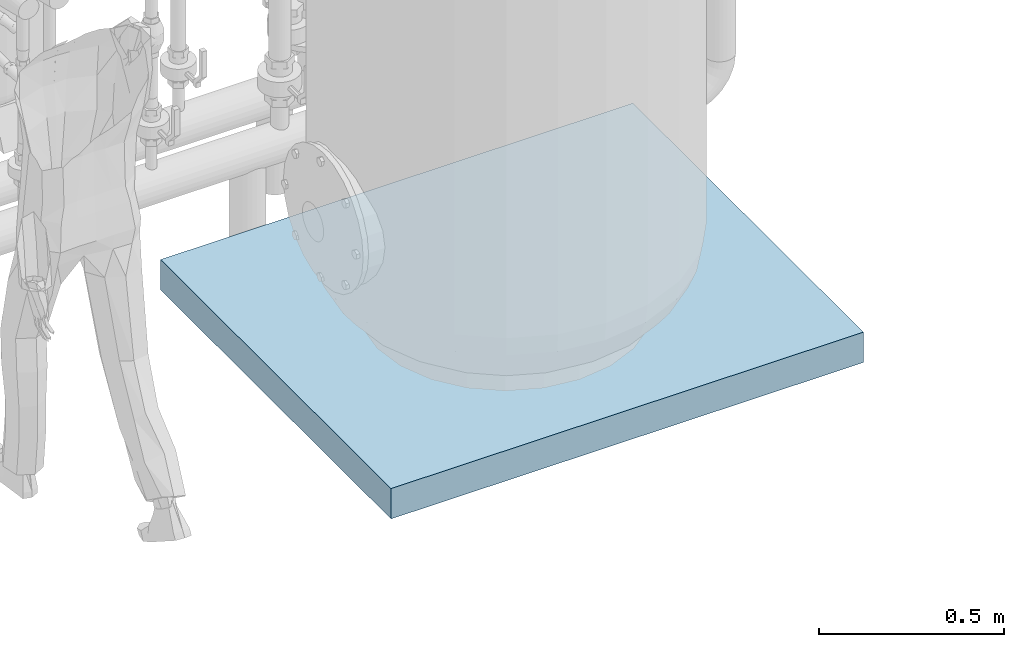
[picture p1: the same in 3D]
Properties of the parts of a building model (IFC2X3), part 3 of 4

# IfcFlowSegment: Partie de gaine de ventilation (63)
Name | In | Geom-Côte 1 (m) (m) | Geom-Côte 2 (m) (m) | Calc-Perte de charge (Pa) (Pa) | Tech-Poids (kg) (kg) | Geom-Longueur (m) (m) | Tech-Fluide | Geom-Surface (m2) (m2) | Calc-Debit vol (m3/s) (m3/s) | Calc-Vitesse (m/s) (m/s) | Group
Partie de gaine de ventilation | R+1 | 0.45 | 0.45 |  | 4.4064 | 0.51 | V_Air_soufflé | 1 |  |  | Air soufflé
Partie de gaine de ventilation | R+1 | 0.45 | 0.45 |  | 5.24184 | 0.606694 | V_Air_soufflé | 1.09205 |  |  | Air soufflé
Partie de gaine de ventilation | Rez de chaussŽe | 0.5 | 0.8 | 0.226687 | 9.41152 | 0.565596 | V_Air_extrait | 1.47055 | 1.94444 | 4.86111 | Air extrait
Partie de gaine de ventilation | Rez de chaussŽe | 0.5 | 0.5 |  | 2.90021 | 0.302105 | V_Air_soufflé | 1 |  |  | Air soufflé
Partie de gaine de ventilation | Rez de chaussŽe | 0.5 | 0.5 |  | 8.63591 | 0.899574 | V_Air_soufflé | 1.79915 |  |  | Air soufflé

# IfcFlowSegment: Piquage circ. oblique 45°
In: R+1
Description: Piquage circ. oblique 45°; Group: Air soufflé
Pset Plancal nova - MEP - Nom: Piquage circ. oblique 45°; Geom-Ø segment de ref (m): 0.315 m; Geom-Ø (m): 0.16 m; Abbreviation: STE; Geom-Longueur (m): 0.05 m; Tech-Fluide: V_Air_soufflé; Tech-Materiel (ID): 1; Geom-Angle (°): 45 rad; Tech-Epaisseur isolant (m): 0 m

# IfcFlowSegment: Piquage oblique sur plat (2)
Description: Piquage oblique sur plat
Pset Plancal nova - MEP - Nom: Piquage oblique sur plat; Abbreviation: POP; Geom-Longueur (m): 0.1 m; Tech-Materiel (ID): 1; Geom-Angle (°): 90 rad; Tech-Epaisseur isolant (m): 0 m
Name | In | Geom-Ø (m) (m) | Tech-Fluide | Group
Piquage oblique sur plat | R+2 | 0.45 | V_Air_soufflé | Air soufflé
Piquage oblique sur plat | Mezzannine | 0.25 | V_Air_extrait | Air extrait

# IfcFlowSegment: Piquage rectangulaire
In: Mezzannine
Description: Piquage rectangulaire; Group: Air extrait
Pset Plancal nova - MEP - Geom-Côte 1 (m): 0.45 m; Geom-Côte 2 (m): 0.45 m; Nom: Piquage rectangulaire; Tech-Poids (kg): 0.432 kg; Abbreviation: LT; Geom-Longueur (m): 0.05 m; Tech-Fluide: V_Air_extrait; Tech-Materiel (ID): 1; Geom-Surface (m2): 1 m2; Tech-Epaisseur isolant (m): 0 m

# IfcFlowSegment: Piquage sur circulaire 90° (27)
In: Rez de chaussŽe
Description: Piquage sur circulaire 90°
Pset Plancal nova - MEP - Nom: Piquage sur circulaire 90°; Tech-Material: Tube acier d'après DIN 2448; Geom-Angle (°): 90 rad
Name | Geom-Ø ext. tuyau de ref. (m) (m) | Geom-Ø exterieur (m) (m) | Geom-DN | Geom-Longueur (m) (m) | Tech-Epaisseur isolant (m) (m) | Group
Piquage sur circulaire 90° | 0.0603 | 0.0213 | 15 | 0.06 | 0.02 | Retour
2 x Piquage sur circulaire 90° | 0.0337 | 0.0213 | 15 | 0.06 | 0.02 | Aller
2 x Piquage sur circulaire 90° | 0.0337 | 0.0269 | 20 | 0.1 | 0.02 | Retour
2 x Piquage sur circulaire 90° | 0.0337 | 0.0213 | 15 | 0.06 | 0.02 | Retour
Piquage sur circulaire 90° | 0.0269 | 0.0213 | 15 | 0.06 | 0.02 | Aller
Piquage sur circulaire 90° | 0.0269 | 0.0213 | 15 | 0.06 | 0.02 | Retour
Piquage sur circulaire 90° | 0.0424 | 0.0213 | 15 | 0.06 | 0.02 | Aller
Piquage sur circulaire 90° | 0.0603 | 0.0213 | 15 | 0.06 | 0.02 | Aller
Piquage sur circulaire 90° | 0.0483 | 0.0213 | 15 | 0.06 | 0.02 | Aller
Piquage sur circulaire 90° | 0.0424 | 0.0213 | 15 | 0.06 | 0.02 | Retour
Piquage sur circulaire 90° | 0.0483 | 0.0213 | 15 | 0.06 | 0 | Retour
Piquage sur circulaire 90° | 0.0603 | 0.0603 | 50 | 0.05 | 0 | Retour
Piquage sur circulaire 90° | 0.0603 | 0.0603 | 50 | 0.05 | 0 | Medium
Piquage sur circulaire 90° | 0.0424 | 0.0337 | 25 | 0.025 | 0 | Aller
2 x Piquage sur circulaire 90° | 1 | 0.0889 | 80 | 0.05 | 0 | Medium
Piquage sur circulaire 90° | 1 | 0.4064 | 400 | 0.05 | 0 | Medium
Piquage sur circulaire 90° | 0.0603 | 0.0483 | 40 | 0.05 | 0 | Medium
Piquage sur circulaire 90° | 0.0761 | 0.0424 | 32 | 0.03 | 0 | Eau froide
Piquage sur circulaire 90° | 0.0761 | 0.0337 | 25 | 0.03 | 0 | Eau froide
2 x Piquage sur circulaire 90° | 1 | 0.0889 | 80 | 0.05 | 0 | Retour
Piquage sur circulaire 90° | 0.0603 | 0.0213 | 15 | 0.02 | 0.02 | Retour
Piquage sur circulaire 90° | 0.0603 | 0.0213 | 15 | 0.02 | 0 | Retour

# IfcFlowSegment: Piquage équerre circulaire (74)
Description: Piquage équerre circulaire
Pset Plancal nova - MEP - Nom: Piquage équerre circulaire; Tech-Materiel (ID): 1; Tech-Epaisseur isolant (m): 0 m
Name | In | Geom-Ø segment de ref (m) (m) | Geom-Ø (m) (m) | Abbreviation | Geom-Longueur (m) (m) | Tech-Fluide | Group
3 x Piquage équerre circulaire | R+2 | 0.5 | 0.16 | STE | 0.05 | V_Air_extrait | Air extrait
Piquage équerre circulaire | R+2 | 0.5 | 0.25 | STE | 0.065 | V_Air_extrait | Air extrait
2 x Piquage équerre circulaire | R+2 | 0.315 | 0.16 | STE | 0.05 | V_Air_extrait | Air extrait
2 x Piquage équerre circulaire | R+2 | 0.45 | 0.16 | STE | 0.05 | V_Air_soufflé | Air soufflé
4 x Piquage équerre circulaire | R+2 | 0.4 | 0.16 | STE | 0.05 | V_Air_soufflé | Air soufflé
4 x Piquage équerre circulaire | R+2 | 0.315 | 0.16 | STE | 0.05 | V_Air_soufflé | Air soufflé
2 x Piquage équerre circulaire | R+2 | 0.2 | 0.16 | STE | 0.045 | V_Air_soufflé | Air soufflé
6 x Piquage équerre circulaire | Mezzannine | 0.315 | 0.16 | STE | 0.05 | V_Air_soufflé | Air soufflé
Piquage équerre circulaire | Mezzannine | 0.16 | 0.16 | STE | 0.045 | V_Air_soufflé | Air soufflé
2 x Piquage équerre circulaire | Mezzannine | 0.16 | 0.16 | STE | 0.045 | V_Air_extrait | Air extrait
Piquage équerre circulaire | Mezzannine | 0.5 | 0.45 | STE | 0.045 | V_Air_extrait | Air extrait
Piquage équerre circulaire | Mezzannine | 0.5 | 0.25 | STE | 0.065 | V_Air_extrait | Air extrait
2 x Piquage équerre circulaire | R+1 | 0.16 | 0.16 | STE | 0.045 | V_Air_extrait | Air extrait
2 x Piquage équerre circulaire | R+1 | 0.315 | 0.315 | STE | 0.045 | V_Air_extrait | Air extrait
Piquage équerre circulaire | R+1 | 0.5 | 0.45 | STE | 0.045 | V_Air_extrait | Air extrait
Piquage équerre circulaire | R+1 | 0.5 | 0.16 | STE | 0.05 | V_Air_extrait | Air extrait
Piquage équerre circulaire | R+1 | 0.5 | 0.2 | STE | 0.065 | V_Air_extrait | Air extrait
2 x Piquage équerre circulaire | R+1 | 0.2 | 0.16 | STE | 0.045 | V_Air_soufflé | Air soufflé
9 x Piquage équerre circulaire | R+1 | 0.315 | 0.16 | STE | 0.05 | V_Air_soufflé | Air soufflé
Piquage équerre circulaire | R+1 | 0.315 | 0.2 | STE | 0.065 | V_Air_soufflé | Air soufflé
Piquage équerre circulaire | R+1 | 0.16 | 0.16 | STE | 0.045 | V_Air_soufflé | Air soufflé
Piquage équerre circulaire | R+1 | 0.315 | 0.16 | STE | 0.05 | V_Air_extrait | Air extrait
Piquage équerre circulaire | R+1 | 0.2 | 0.16 | STE | 0.05 | V_Air_extrait | Air extrait
6 x Piquage équerre circulaire | Rez de chaussŽe | 0.25 | 0.16 | STE | 0.05 | V_Air_extrait | Air extrait
4 x Piquage équerre circulaire | Rez de chaussŽe | 0.45 | 0.16 | STE | 0.05 | V_Air_extrait | Air extrait
4 x Piquage équerre circulaire | Rez de chaussŽe | 0.355 | 0.16 | STE | 0.05 | V_Air_extrait | Air extrait
7 x Piquage équerre circulaire | Rez de chaussŽe | 0.315 | 0.16 | STE | 0.05 | V_Air_extrait | Air extrait
Piquage équerre circulaire | Rez de chaussŽe | 0.25 | 0.25 | STE | 0.045 | V_Air_extrait | Air extrait
Piquage équerre circulaire | Rez de chaussŽe | 0.4 | 0.16 | PEC | 0.05 | V_Air_soufflé | Air soufflé

# IfcFlowSegment: Piquage équerre sur plat (12)
Description: Piquage équerre sur plat
Pset Plancal nova - MEP - Nom: Piquage équerre sur plat; Abbreviation: SR; Tech-Materiel (ID): 1; Tech-Epaisseur isolant (m): 0 m
Name | In | Geom-Ø (m) (m) | Tech-Poids (kg) (kg) | Geom-Longueur (m) (m) | Tech-Fluide | Geom-Surface (m2) (m2) | Group
3 x Piquage équerre sur plat | R+2 | 0.16 | 0.120637 | 0.05 | V_Air_extrait | 0.0251327 | Air extrait
Piquage équerre sur plat | R+1 | 0.25 | 0.188496 | 0.05 | V_Air_extrait | 0.0392699 | Air extrait
2 x Piquage équerre sur plat | R+1 | 0.16 | 0.120637 | 0.05 | V_Air_soufflé | 0.0251327 | Air soufflé
Piquage équerre sur plat | R+1 | 0.25 | 0.376991 | 0.1 | V_Air_extrait | 1 | Air extrait
Piquage équerre sur plat | R+1 | 0.315 | 0.237504 | 0.05 | V_Air_soufflé | 0.0494801 | Air soufflé
Piquage équerre sur plat | Rez de chaussŽe | 0.16 | 0.120637 | 0.05 | V_Air_soufflé | 0.0251327 | Air soufflé
Piquage équerre sur plat | Rez de chaussŽe | 0.355 | 0.267664 | 0.05 | V_Air_soufflé | 0.0557633 | Air soufflé
Piquage équerre sur plat | Rez de chaussŽe | 0.25 | 0.188496 | 0.05 | V_Air_extrait | 0.0392699 | Air extrait
Piquage équerre sur plat | Rez de chaussŽe | 0.5 | 0.376991 | 0.05 | V_Air_extrait | 0.0785398 | Air extrait

# IfcFlowSegment: Raccord (circ.) (29)
Description: Raccord (circ.)
Pset Plancal nova - MEP - Nom: Raccord (circ.); Abbreviation: R-STV; Tech-Materiel (ID): 1; Tech-Epaisseur isolant (m): 0 m
Name | In | Geom-Longueur add (m) (m) | Geom-Ø (m) (m) | Geom-Longueur milieu (m) (m) | Tech-Fluide | Group
6 x Raccord (circ.) | R+2 | 0.015 | 0.16 | 0.04 | V_Air_extrait | Air extrait
5 x Raccord (circ.) | R+2 | 0.015 | 0.355 | 0.06 | V_Air_extrait | Air extrait
2 x Raccord (circ.) | R+2 | 0.02 | 0.45 | 0.08 | V_Air_extrait | Air extrait
Raccord (circ.) | R+2 | 0.02 | 0.5 | 0.08 | V_Air_soufflé | Air soufflé
2 x Raccord (circ.) | R+2 | 0.015 | 0.25 | 0.06 | V_Air_extrait | Air extrait
3 x Raccord (circ.) | R+2 | 0.02 | 0.45 | 0.08 | V_Air_soufflé | Air soufflé
3 x Raccord (circ.) | R+2 | 0.015 | 0.16 | 0.04 | V_Air_soufflé | Air soufflé
Raccord (circ.) | Mezzannine | 0.02 | 0.5 | 0.08 | V_Air_soufflé | Air soufflé
Raccord (circ.) | Mezzannine | 0.015 | 0.25 | 0.06 | V_Air_extrait | Air extrait
Raccord (circ.) | Mezzannine | 0.015 | 0.16 | 0.04 | V_Air_extrait | Air extrait
2 x Raccord (circ.) | R+1 | 0.015 | 0.16 | 0.04 | V_Air_extrait | Air extrait
2 x Raccord (circ.) | R+1 | 0.015 | 0.25 | 0.06 | V_Air_extrait | Air extrait

# IfcFlowSegment: Tube (683)
Description: Tube
Pset Plancal nova - MEP - Nom: Tube; Abbreviation: R-R; Tech-Materiel (ID): 1; Tech-Epaisseur isolant (m): 0 m
Name | In | Geom-Ø (m) (m) | Geom-Longueur (m) (m) | Tech-Fluide | Group | Calc-Perte de charge (Pa) (Pa) | Calc-Debit vol (m3/s) (m3/s) | Calc-Vitesse (m/s) (m/s)
Tube | Toiture | 0.5 | 1.1855 | V_Air_soufflé | Air soufflé
Tube | R+2 | 0.16 | 0.0940547 | V_Air_extrait | Air extrait | 0.06983 | 0.0555556 | 2.76311
Tube | R+2 | 0.16 | 0.597116 | V_Air_extrait | Air extrait | 0.443323 | 0.0555556 | 2.76311
Tube | R+2 | 0.16 | 1.12403 | V_Air_extrait | Air extrait | 0.834524 | 0.0555556 | 2.76311
Tube | R+2 | 0.2 | 0.893766 | V_Air_extrait | Air extrait | 0.789746 | 0.111111 | 3.53678
Tube | R+2 | 0.16 | 0.9425 | V_Air_extrait | Air extrait | 0.69975 | 0.0555556 | 2.76311
Tube | R+2 | 0.16 | 1.65094 | V_Air_extrait | Air extrait | 1.22572 | 0.0555556 | 2.76311
Tube | R+2 | 0.16 | 2.17785 | V_Air_extrait | Air extrait | 1.61692 | 0.0555556 | 2.76311
Tube | R+2 | 0.5 | 3 | V_Air_extrait | Air extrait | 1.3551 | 0.888889 | 4.52707
Tube | R+2 | 0.5 | 3 | V_Air_extrait | Air extrait | 1.2014 | 0.833333 | 4.24413
Tube | R+2 | 0.5 | 3 | V_Air_extrait | Air extrait | 0.675734 | 0.611111 | 3.11236
Tube | R+2 | 0.5 | 2.32628 | V_Air_extrait | Air extrait | 0.523983 | 0.611111 | 3.11236
6 x Tube | R+2 | 0.4 | 3 | V_Air_extrait | Air extrait | 1.70309 | 0.555556 | 4.42097
Tube | R+2 | 0.4 | 1.84351 | V_Air_extrait | Air extrait | 1.04656 | 0.555556 | 4.42097
Tube | R+2 | 0.16 | 0.969516 | V_Air_extrait | Air extrait | 0.719808 | 0.0555556 | 2.76311
Tube | R+2 | 0.16 | 1.40134 | V_Air_extrait | Air extrait | 1.04041 | 0.0555556 | 2.76311
Tube | R+2 | 0.4 | 0.741345 | V_Air_extrait | Air extrait | 0.345927 | 0.5 | 3.97887
5 x Tube | R+2 | 0.355 | 3 | V_Air_extrait | Air extrait | 2.0296 | 0.444444 | 4.49025
Tube | R+2 | 0.355 | 0.463 | V_Air_extrait | Air extrait | 0.313236 | 0.444444 | 4.49025
2 x Tube | R+2 | 0.315 | 3 | V_Air_extrait | Air extrait | 2.86267 | 0.388889 | 4.99016
2 x Tube | R+2 | 0.315 | 0.52 | V_Air_extrait | Air extrait | 0.496196 | 0.388889 | 4.99016
2 x Tube | R+2 | 0.315 | 3 | V_Air_extrait | Air extrait | 2.14771 | 0.333333 | 4.27728
2 x Tube | R+2 | 0.315 | 0.74 | V_Air_extrait | Air extrait | 0.529768 | 0.333333 | 4.27728
2 x Tube | R+2 | 0.16 | 0.08 | V_Air_extrait | Air extrait | 0.0593952 | 0.0555556 | 2.76311
Tube | R+2 | 0.16 | 1.33805 | V_Air_extrait | Air extrait | 0.99342 | 0.0555556 | 2.76311
2 x Tube | R+2 | 0.315 | 3 | V_Air_extrait | Air extrait | 1.5315 | 0.277778 | 3.5644
Tube | R+2 | 0.315 | 1.68651 | V_Air_extrait | Air extrait | 0.860967 | 0.277778 | 3.5644
Tube | R+2 | 0.16 | 0.114999 | V_Air_extrait | Air extrait | 0.0853802 | 0.0555556 | 2.76311
2 x Tube | R+2 | 0.2 | 3 | V_Air_extrait | Air extrait | 2.65085 | 0.111111 | 3.53678
2 x Tube | R+2 | 0.2 | 0.506 | V_Air_extrait | Air extrait | 0.44711 | 0.111111 | 3.53678
2 x Tube | R+2 | 0.16 | 3 | V_Air_extrait | Air extrait | 2.22732 | 0.0555556 | 2.76311
Tube | R+2 | 0.16 | 0.53 | V_Air_extrait | Air extrait | 0.393494 | 0.0555556 | 2.76311
Tube | R+2 | 0.16 | 0.129999 | V_Air_extrait | Air extrait | 0.0965168 | 0.0555556 | 2.76311
Tube | R+2 | 0.16 | 0.139999 | V_Air_extrait | Air extrait | 0.103941 | 0.0555556 | 2.76311
Tube | R+2 | 0.45 | 3 | V_Air_extrait | Air extrait | 1.55004 | 0.722222 | 4.54105
Tube | R+2 | 0.45 | 0.74 | V_Air_extrait | Air extrait | 0.382344 | 0.722222 | 4.54105
Tube | R+2 | 0.45 | 3 | V_Air_extrait | Air extrait | 1.33518 | 0.666667 | 4.19174
Tube | R+2 | 0.45 | 0.74 | V_Air_extrait | Air extrait | 0.329345 | 0.666667 | 4.19174
Tube | R+2 | 0.4 | 3 | V_Air_extrait | Air extrait | 2.0347 | 0.611111 | 4.86307
Tube | R+2 | 0.4 | 0.451 | V_Air_extrait | Air extrait | 0.305883 | 0.611111 | 4.86307
Tube | R+2 | 0.4 | 0.74 | V_Air_extrait | Air extrait | 0.420097 | 0.555556 | 4.42097
Tube | R+2 | 0.4 | 3 | V_Air_extrait | Air extrait | 1.39986 | 0.5 | 3.97887
Tube | R+2 | 0.4 | 1.63468 | V_Air_extrait | Air extrait | 0.762773 | 0.5 | 3.97887
Tube | R+2 | 0.355 | 0.51506 | V_Air_extrait | Air extrait | 0.348456 | 0.444444 | 4.49025
Tube | R+2 | 0.315 | 0.74 | V_Air_extrait | Air extrait | 0.377771 | 0.277778 | 3.5644
Tube | R+2 | 0.25 | 3 | V_Air_extrait | Air extrait | 3.17494 | 0.222222 | 4.52707
Tube | R+2 | 0.25 | 0.486 | V_Air_extrait | Air extrait | 0.51434 | 0.222222 | 4.52707
2 x Tube | R+2 | 0.16 | 0.114906 | V_Air_extrait | Air extrait | 0.085311 | 0.0555556 | 2.76311
3 x Tube | R+2 | 0.25 | 3 | V_Air_extrait | Air extrait | 1.86312 | 0.166667 | 3.39531
Tube | R+2 | 0.25 | 0.74 | V_Air_extrait | Air extrait | 0.459568 | 0.166667 | 3.39531
Tube | R+2 | 0.16 | 0.53 | V_Air_extrait | Air extrait | 0.393493 | 0.0555556 | 2.76311
Tube | R+2 | 0.16 | 0.129906 | V_Air_extrait | Air extrait | 0.0964477 | 0.0555556 | 2.76311
Tube | R+2 | 0.16 | 0.139906 | V_Air_extrait | Air extrait | 0.103872 | 0.0555556 | 2.76311
Tube | R+2 | 0.16 | 2.01228 | V_Air_soufflé | Air soufflé | 1.494 | 0.0555556 | 2.76311
Tube | R+2 | 0.16 | 2.01772 | V_Air_soufflé | Air soufflé | 1.49804 | 0.0555556 | 2.76311
Tube | R+2 | 0.45 | 1.13981 | V_Air_soufflé | Air soufflé | 0.507283 | 0.666667 | 4.19174
2 x Tube | R+2 | 0.16 | 2.04272 | V_Air_soufflé | Air soufflé | 1.5166 | 0.0555556 | 2.76311
2 x Tube | R+2 | 0.16 | 2.03728 | V_Air_soufflé | Air soufflé | 1.51256 | 0.0555556 | 2.76311
3 x Tube | R+2 | 0.4 | 3 | V_Air_soufflé | Air soufflé | 1.70309 | 0.555556 | 4.42097
Tube | R+2 | 0.4 | 2.04276 | V_Air_soufflé | Air soufflé | 0.766132 | 0.444444 | 3.53678
2 x Tube | R+2 | 0.16 | 2.08522 | V_Air_soufflé | Air soufflé | 1.54815 | 0.0555556 | 2.76311
2 x Tube | R+2 | 0.16 | 2.07978 | V_Air_soufflé | Air soufflé | 1.54411 | 0.0555556 | 2.76311
3 x Tube | R+2 | 0.315 | 3 | V_Air_soufflé | Air soufflé | 2.14771 | 0.333333 | 4.27728
Tube | R+2 | 0.315 | 1.82631 | V_Air_soufflé | Air soufflé | 0.617891 | 0.222222 | 2.85152
Tube | R+2 | 0.16 | 2.14772 | V_Air_soufflé | Air soufflé | 1.59456 | 0.0555556 | 2.76311
Tube | R+2 | 0.16 | 2.14228 | V_Air_soufflé | Air soufflé | 1.59051 | 0.0555556 | 2.76311
Tube | R+2 | 0.2 | 3 | V_Air_soufflé | Air soufflé | 2.65085 | 0.111111 | 3.53678
Tube | R+2 | 0.2 | 0.747412 | V_Air_soufflé | Air soufflé | 0.660425 | 0.111111 | 3.53678
Tube | R+2 | 0.16 | 2.941 | V_Air_soufflé | Air soufflé | 2.18352 | 0.0555556 | 2.76311
2 x Tube | R+2 | 0.45 | 3 | V_Air_soufflé | Air soufflé | 1.33518 | 0.666667 | 4.19174
Tube | R+2 | 0.45 | 1.346 | V_Air_soufflé | Air soufflé | 0.59905 | 0.666667 | 4.19174
Tube | R+2 | 0.4 | 3 | V_Air_soufflé | Air soufflé | 2.0347 | 0.611111 | 4.86307
Tube | R+2 | 0.4 | 0.451 | V_Air_soufflé | Air soufflé | 0.305883 | 0.611111 | 4.86307
Tube | R+2 | 0.4 | 0.74 | V_Air_soufflé | Air soufflé | 0.420097 | 0.555556 | 4.42097
Tube | R+2 | 0.4 | 3 | V_Air_soufflé | Air soufflé | 1.39986 | 0.5 | 3.97887
Tube | R+2 | 0.4 | 0.737299 | V_Air_soufflé | Air soufflé | 0.344039 | 0.5 | 3.97887
Tube | R+2 | 0.355 | 3 | V_Air_soufflé | Air soufflé | 2.0296 | 0.444444 | 4.49025
Tube | R+2 | 0.355 | 0.463003 | V_Air_soufflé | Air soufflé | 0.313238 | 0.444444 | 4.49025
Tube | R+2 | 0.315 | 3 | V_Air_soufflé | Air soufflé | 2.86267 | 0.388889 | 4.99016
Tube | R+2 | 0.315 | 0.52 | V_Air_soufflé | Air soufflé | 0.496196 | 0.388889 | 4.99016
Tube | R+2 | 0.315 | 0.74 | V_Air_soufflé | Air soufflé | 0.529768 | 0.333333 | 4.27728
Tube | R+2 | 0.315 | 1.55535 | V_Air_soufflé | Air soufflé | 0.794011 | 0.277778 | 3.5644
Tube | R+2 | 0.25 | 2.68783 | V_Air_soufflé | Air soufflé | 2.84457 | 0.222222 | 4.52707
Tube | R+2 | 0.16 | 1.66465 | V_Air_soufflé | Air soufflé | 1.2359 | 0.0555556 | 2.76311
Tube | R+2 | 0.16 | 2.88873 | V_Air_soufflé | Air soufflé | 2.14471 | 0.0555556 | 2.76311
Tube | R+2 | 0.25 | 1.37873 | V_Air_soufflé | Air soufflé | 0.856245 | 0.166667 | 3.39531
Tube | R+2 | 0.25 | 1.62035 | V_Air_soufflé | Air soufflé | 1.0063 | 0.166667 | 3.39531
Tube | R+2 | 0.2 | 2.10483 | V_Air_soufflé | Air soufflé | 1.85986 | 0.111111 | 3.53678
Tube | R+2 | 0.2 | 1.67 | V_Air_soufflé | Air soufflé | 1.47564 | 0.111111 | 3.53678
Tube | R+2 | 0.16 | 0.471172 | V_Air_soufflé | Air soufflé | 0.349817 | 0.0555556 | 2.76311
Tube | R+2 | 0.16 | 2.29595 | V_Air_soufflé | Air soufflé | 1.7046 | 0.0555556 | 2.76311
Tube | R+2 | 0.16 | 1.01117 | V_Air_soufflé | Air soufflé | 0.750735 | 0.0555556 | 2.76311
Tube | R+2 | 0.16 | 0.364052 | V_Air_soufflé | Air soufflé | 0.270287 | 0.0555556 | 2.76311
Tube | R+2 | 0.16 | 1.115 | V_Air_soufflé | Air soufflé | 0.827822 | 0.0555556 | 2.76311
Tube | R+2 | 0.16 | 1.62965 | V_Air_soufflé | Air soufflé | 1.20992 | 0.0555556 | 2.76311
Tube | R+2 | 0.16 | 2.16943 | V_Air_soufflé | Air soufflé | 1.61068 | 0.0555556 | 2.76311
3 x Tube | R+2 | 0.16 | 2.20572 | V_Air_extrait | Air extrait | 1.63762 | 0.0555556 | 2.76311
Tube | R+2 | 0.16 | 2.23072 | V_Air_extrait | Air extrait | 1.65618 | 0.0555556 | 2.76311
Tube | R+2 | 0.16 | 2.27419 | V_Air_extrait | Air extrait | 1.68845 | 0.0555556 | 2.76311
Tube | R+2 | 0.355 | 0.787416 | V_Air_extrait | Air extrait | 0.532714 | 0.444444 | 4.49025
Tube | R+2 | 0.45 | 2.11644 | V_Air_extrait | Air extrait | 1.25592 | 0.777778 | 4.89036
Tube | R+2 | 0.45 | 3 | V_Air_extrait | Air extrait | 1.78024 | 0.777778 | 4.89036
Tube | R+2 | 0.45 | 1.40922 | V_Air_extrait | Air extrait | 0.836252 | 0.777778 | 4.89036
Tube | R+2 | 0.5 | 2.35 | V_Air_soufflé | Air soufflé | 0.941097 | 0.833333 | 4.24413
Tube | R+2 | 0.5 | 3 | V_Air_soufflé | Air soufflé | 1.2014 | 0.833333 | 4.24413
Tube | R+2 | 0.5 | 0.6 | V_Air_soufflé | Air soufflé | 0.24028 | 0.833333 | 4.24413
Tube | R+2 | 0.25 | 0.453335 | V_Air_extrait | Air extrait | 0.281538 | 0.166667 | 3.39531
Tube | R+2 | 0.25 | 1.28402 | V_Air_extrait | Air extrait | 0.797429 | 0.166667 | 3.39531
Tube | R+2 | 0.45 | 0.55759 | V_Air_soufflé | Air soufflé | 0.288096 | 0.722222 | 4.54105
Tube | R+2 | 0.45 | 2.91 | V_Air_soufflé | Air soufflé | 1.29513 | 0.666667 | 4.19174
Tube | R+2 | 0.25 | 2.22502 | V_Air_extrait | Air extrait
2 x Tube | R+2 | 0.16 | 1.5884 | V_Air_soufflé | Air soufflé
Tube | R+2 | 0.16 | 1.5634 | V_Air_soufflé | Air soufflé
Tube | R+2 | 0.315 | 1.15783 | V_Air_soufflé | Air soufflé
Tube | R+2 | 0.45 | 1.9834 | V_Air_soufflé | Air soufflé
Tube | R+2 | 0.16 | 1.0688 | V_Air_extrait | Air extrait
Tube | R+2 | 0.5 | 0.220611 | V_Air_soufflé | Air soufflé
Tube | R+2 | 0.16 | 1.17985 | V_Air_extrait | Air extrait
Tube | R+2 | 0.16 | 2.8 | V_Air_extrait | Air extrait
Tube | R+2 | 0.355 | 3.08628 | V_Air_extrait | Air extrait
Tube | R+2 | 0.355 | 2.49838 | V_Air_extrait | Air extrait
Tube | R+2 | 0.355 | 2.21872 | V_Air_extrait | Air extrait
Tube | R+2 | 0.16 | 0.611241 | V_Air_extrait | Air extrait
4 x Tube | R+2 | 0.5 | 3 | V_Air_soufflé | Air soufflé
Tube | R+2 | 0.16 | 0.47889 | V_Air_extrait | Air extrait | 0.355547 | 0.0555556 | 2.76311
Tube | R+2 | 0.16 | 1.18023 | V_Air_extrait | Air extrait | 0.876253 | 0.0555556 | 2.76311
Tube | R+2 | 0.5 | 1.90752 | V_Air_soufflé | Air soufflé
Tube | R+2 | 0.5 | 3.10121 | V_Air_soufflé | Air soufflé
Tube | R+2 | 0.5 | 0.444234 | V_Air_soufflé | Air soufflé
Tube | R+2 | 0.5 | 3.32059 | V_Air_soufflé | Air soufflé
Tube | R+2 | 0.25 | 0.298636 | V_Air_extrait | Air extrait
Tube | R+2 | 0.25 | 2.77085 | V_Air_extrait | Air extrait
Tube | R+2 | 0.4 | 1.12303 | V_Air_extrait | Air extrait
Tube | R+2 | 0.4 | 1.93325 | V_Air_extrait | Air extrait
Tube | Mezzannine | 0.45 | 1.40075 | V_Air_soufflé | Air soufflé | 0.72374 | 0.722222 | 4.54105
Tube | Mezzannine | 0.315 | 0.410721 | V_Air_soufflé | Air soufflé | 0.294036 | 0.333333 | 4.27728
2 x Tube | Mezzannine | 0.16 | 2.00087 | V_Air_soufflé | Air soufflé | 1.48552 | 0.0555556 | 2.76311
2 x Tube | Mezzannine | 0.16 | 1.91413 | V_Air_soufflé | Air soufflé | 1.42113 | 0.0555556 | 2.76311
Tube | Mezzannine | 0.16 | 2.67587 | V_Air_soufflé | Air soufflé | 1.98667 | 0.0555556 | 2.76311
Tube | Mezzannine | 0.16 | 0.134688 | V_Air_soufflé | Air soufflé | 0.0999977 | 0.0555556 | 2.76311
Tube | Mezzannine | 0.16 | 2.58913 | V_Air_soufflé | Air soufflé | 1.92228 | 0.0555556 | 2.76311
Tube | Mezzannine | 0.16 | 0.134688 | V_Air_soufflé | Air soufflé | 0.0999978 | 0.0555556 | 2.76311
Tube | Mezzannine | 0.315 | 3 | V_Air_soufflé | Air soufflé | 1.01498 | 0.222222 | 2.85152
Tube | Mezzannine | 0.315 | 3 | V_Air_soufflé | Air soufflé | 0.287667 | 0.111111 | 1.42576
Tube | Mezzannine | 0.315 | 1.31554 | V_Air_soufflé | Air soufflé | 1.25532 | 0.388889 | 4.99016
Tube | Mezzannine | 0.315 | 3 | V_Air_soufflé | Air soufflé | 2.14771 | 0.333333 | 4.27728
Tube | Mezzannine | 0.315 | 0.740003 | V_Air_soufflé | Air soufflé | 0.529771 | 0.333333 | 4.27728
Tube | Mezzannine | 0.315 | 3 | V_Air_soufflé | Air soufflé | 1.5315 | 0.277778 | 3.5644
Tube | Mezzannine | 0.315 | 0.74 | V_Air_soufflé | Air soufflé | 0.377771 | 0.277778 | 3.5644
Tube | Mezzannine | 0.25 | 3 | V_Air_soufflé | Air soufflé | 3.17494 | 0.222222 | 4.52707
Tube | Mezzannine | 0.25 | 0.486 | V_Air_soufflé | Air soufflé | 0.51434 | 0.222222 | 4.52707
Tube | Mezzannine | 0.16 | 0.760001 | V_Air_soufflé | Air soufflé | 0.564256 | 0.0555556 | 2.76311
Tube | Mezzannine | 0.25 | 1.70763 | V_Air_soufflé | Air soufflé | 1.0605 | 0.166667 | 3.39531
2 x Tube | Mezzannine | 0.2 | 3 | V_Air_soufflé | Air soufflé | 2.65085 | 0.111111 | 3.53678
Tube | Mezzannine | 0.2 | 2.84 | V_Air_soufflé | Air soufflé | 2.50947 | 0.111111 | 3.53678
Tube | Mezzannine | 0.2 | 1.67339 | V_Air_soufflé | Air soufflé | 1.47864 | 0.111111 | 3.53678
Tube | Mezzannine | 0.16 | 3 | V_Air_soufflé | Air soufflé | 2.22732 | 0.0555556 | 2.76311
Tube | Mezzannine | 0.16 | 1.03117 | V_Air_soufflé | Air soufflé | 0.765584 | 0.0555556 | 2.76311
3 x Tube | Mezzannine | 0.16 | 0.725001 | V_Air_soufflé | Air soufflé | 0.53827 | 0.0555556 | 2.76311
Tube | Mezzannine | 0.16 | 0.0988467 | V_Air_extrait | Air extrait | 0.0733878 | 0.0555556 | 2.76311
Tube | Mezzannine | 0.5 | 0.693274 | V_Air_extrait | Air extrait | 0.350718 | 0.944444 | 4.81002
Tube | Mezzannine | 0.5 | 3 | V_Air_extrait | Air extrait | 1.3551 | 0.888889 | 4.52707
Tube | Mezzannine | 0.5 | 0.74 | V_Air_extrait | Air extrait | 0.334258 | 0.888889 | 4.52707
Tube | Mezzannine | 0.5 | 3 | V_Air_extrait | Air extrait | 1.2014 | 0.833333 | 4.24413
Tube | Mezzannine | 0.5 | 0.74 | V_Air_extrait | Air extrait | 0.296345 | 0.833333 | 4.24413
Tube | Mezzannine | 0.45 | 3 | V_Air_extrait | Air extrait | 1.78024 | 0.777778 | 4.89036
Tube | Mezzannine | 0.45 | 0.451 | V_Air_extrait | Air extrait | 0.26763 | 0.777778 | 4.89036
Tube | Mezzannine | 0.45 | 3 | V_Air_extrait | Air extrait | 1.55004 | 0.722222 | 4.54105
Tube | Mezzannine | 0.45 | 0.74 | V_Air_extrait | Air extrait | 0.382344 | 0.722222 | 4.54105
Tube | Mezzannine | 0.45 | 0.204936 | V_Air_extrait | Air extrait | 0.0912088 | 0.666667 | 4.19174
Tube | Mezzannine | 0.4 | 2.98606 | V_Air_extrait | Air extrait | 2.02525 | 0.611111 | 4.86307
Tube | Mezzannine | 0.4 | 3 | V_Air_extrait | Air extrait | 1.70309 | 0.555556 | 4.42097
Tube | Mezzannine | 0.4 | 0.74 | V_Air_extrait | Air extrait | 0.420097 | 0.555556 | 4.42097
2 x Tube | Mezzannine | 0.4 | 3 | V_Air_extrait | Air extrait | 1.39986 | 0.5 | 3.97887
2 x Tube | Mezzannine | 0.4 | 0.74 | V_Air_extrait | Air extrait | 0.345299 | 0.5 | 3.97887
Tube | Mezzannine | 0.355 | 3 | V_Air_extrait | Air extrait | 2.0296 | 0.444444 | 4.49025
Tube | Mezzannine | 0.355 | 0.463 | V_Air_extrait | Air extrait | 0.313236 | 0.444444 | 4.49025
Tube | Mezzannine | 0.315 | 3 | V_Air_extrait | Air extrait | 2.86267 | 0.388889 | 4.99016
Tube | Mezzannine | 0.315 | 0.52 | V_Air_extrait | Air extrait | 0.496196 | 0.388889 | 4.99016
2 x Tube | Mezzannine | 0.315 | 3 | V_Air_extrait | Air extrait | 2.14771 | 0.333333 | 4.27728
2 x Tube | Mezzannine | 0.315 | 0.74 | V_Air_extrait | Air extrait | 0.529768 | 0.333333 | 4.27728
2 x Tube | Mezzannine | 0.315 | 3 | V_Air_extrait | Air extrait | 1.5315 | 0.277778 | 3.5644
2 x Tube | Mezzannine | 0.315 | 0.74 | V_Air_extrait | Air extrait | 0.377771 | 0.277778 | 3.5644
2 x Tube | Mezzannine | 0.25 | 3 | V_Air_extrait | Air extrait | 3.17494 | 0.222222 | 4.52707
2 x Tube | Mezzannine | 0.25 | 0.486 | V_Air_extrait | Air extrait | 0.51434 | 0.222222 | 4.52707
2 x Tube | Mezzannine | 0.25 | 3 | V_Air_extrait | Air extrait | 1.86312 | 0.166667 | 3.39531
2 x Tube | Mezzannine | 0.25 | 0.74 | V_Air_extrait | Air extrait | 0.459568 | 0.166667 | 3.39531
2 x Tube | Mezzannine | 0.2 | 3 | V_Air_extrait | Air extrait | 2.65085 | 0.111111 | 3.53678
2 x Tube | Mezzannine | 0.2 | 0.506 | V_Air_extrait | Air extrait | 0.44711 | 0.111111 | 3.53678
2 x Tube | Mezzannine | 0.16 | 3 | V_Air_extrait | Air extrait | 2.22732 | 0.0555556 | 2.76311
Tube | Mezzannine | 0.16 | 0.56 | V_Air_extrait | Air extrait | 0.415767 | 0.0555556 | 2.76311
Tube | Mezzannine | 0.25 | 0.97365 | V_Air_extrait | Air extrait | 0.287585 | 0.111111 | 2.26354
Tube | Mezzannine | 0.2 | 0.893766 | V_Air_extrait | Air extrait | 0.789746 | 0.111111 | 3.53678
Tube | Mezzannine | 0.16 | 1.37619 | V_Air_extrait | Air extrait | 1.02174 | 0.0555556 | 2.76311
Tube | Mezzannine | 0.45 | 1.16938 | V_Air_extrait | Air extrait | 0.604194 | 0.722222 | 4.54105
Tube | Mezzannine | 0.16 | 0.767711 | V_Air_extrait | Air extrait | 0.56998 | 0.0555556 | 2.76311
Tube | Mezzannine | 0.4 | 2.94789 | V_Air_extrait | Air extrait | 1.67351 | 0.555556 | 4.42097
2 x Tube | Mezzannine | 0.16 | 0.217644 | V_Air_extrait | Air extrait | 0.161588 | 0.0555556 | 2.76311
Tube | Mezzannine | 0.355 | 2.30635 | V_Air_extrait | Air extrait | 1.56033 | 0.444444 | 4.49025
Tube | Mezzannine | 0.16 | 0.912644 | V_Air_extrait | Air extrait | 0.677584 | 0.0555556 | 2.76311
Tube | Mezzannine | 0.16 | 0.161648 | V_Air_extrait | Air extrait | 0.120014 | 0.0555556 | 2.76311
Tube | Mezzannine | 0.315 | 1.17679 | V_Air_extrait | Air extrait | 1.12293 | 0.388889 | 4.99016
Tube | Mezzannine | 0.315 | 2.59233 | V_Air_extrait | Air extrait | 2.47366 | 0.388889 | 4.99016
Tube | Mezzannine | 0.315 | 1.22461 | V_Air_extrait | Air extrait | 1.16855 | 0.388889 | 4.99016
3 x Tube | Mezzannine | 0.16 | 2.24007 | V_Air_extrait | Air extrait | 1.66312 | 0.0555556 | 2.76311
Tube | Mezzannine | 0.16 | 0.425693 | V_Air_extrait | Air extrait | 0.316052 | 0.0555556 | 2.76311
Tube | Mezzannine | 0.16 | 2.30007 | V_Air_extrait | Air extrait | 1.70766 | 0.0555556 | 2.76311
Tube | Mezzannine | 0.16 | 2.27507 | V_Air_extrait | Air extrait | 1.6891 | 0.0555556 | 2.76311
Tube | Mezzannine | 0.16 | 0.266562 | V_Air_extrait | Air extrait | 0.197906 | 0.0555556 | 2.76311
Tube | Mezzannine | 0.16 | 1.29462 | V_Air_extrait | Air extrait | 0.961181 | 0.0555556 | 2.76311
Tube | Mezzannine | 0.16 | 0.597008 | V_Air_extrait | Air extrait | 0.443243 | 0.0555556 | 2.76311
Tube | Mezzannine | 0.16 | 0.638709 | V_Air_extrait | Air extrait | 0.474204 | 0.0555556 | 2.76311
Tube | Mezzannine | 0.2 | 1.83744 | V_Air_extrait | Air extrait | 1.62359 | 0.111111 | 3.53678
Tube | Mezzannine | 0.16 | 1.86445 | V_Air_extrait | Air extrait | 1.38425 | 0.0555556 | 2.76311
Tube | Mezzannine | 0.16 | 0.473919 | V_Air_extrait | Air extrait | 0.351856 | 0.0555556 | 2.76311
Tube | Mezzannine | 0.5 | 2.97341 | V_Air_extrait | Air extrait | 1.34309 | 0.888889 | 4.52707
Tube | Mezzannine | 0.5 | 0.223828 | V_Air_soufflé | Air soufflé | 0.0896355 | 0.833333 | 4.24413
Tube | Mezzannine | 0.25 | 0.466818 | V_Air_extrait | Air extrait | 0.137883 | 0.111111 | 2.26354
Tube | Mezzannine | 0.45 | 3 | V_Air_extrait | Air extrait
Tube | Mezzannine | 0.45 | 0.51 | V_Air_extrait | Air extrait
Tube | Mezzannine | 0.5 | 1.10518 | V_Air_soufflé | Air soufflé
Tube | Mezzannine | 0.5 | 1.06266 | V_Air_soufflé | Air soufflé
Tube | Mezzannine | 0.45 | 1.55046 | V_Air_soufflé | Air soufflé
Tube | Mezzannine | 0.315 | 2.3495 | V_Air_soufflé | Air soufflé
Tube | Mezzannine | 0.315 | 1.44996 | V_Air_soufflé | Air soufflé
Tube | Mezzannine | 0.315 | 3 | V_Air_soufflé | Air soufflé
Tube | Mezzannine | 0.315 | 2.78142 | V_Air_soufflé | Air soufflé
Tube | Mezzannine | 0.16 | 1.37088 | V_Air_soufflé | Air soufflé
Tube | Mezzannine | 0.16 | 0.72088 | V_Air_soufflé | Air soufflé
Tube | Mezzannine | 0.5 | 0.853549 | V_Air_extrait | Air extrait
Tube | Mezzannine | 0.16 | 1.57287 | V_Air_extrait | Air extrait
Tube | Mezzannine | 0.16 | 1.51646 | V_Air_extrait | Air extrait
2 x Tube | Mezzannine | 0.16 | 0.440479 | V_Air_soufflé | Air soufflé
Tube | Mezzannine | 0.16 | 0.274724 | V_Air_soufflé | Air soufflé
Tube | Mezzannine | 0.16 | 0.428376 | V_Air_soufflé | Air soufflé
Tube | Mezzannine | 0.16 | 1.45 | V_Air_soufflé | Air soufflé
Tube | Mezzannine | 0.16 | 2.63496 | V_Air_extrait | Air extrait
2 x Tube | Mezzannine | 0.16 | 0.14549 | V_Air_extrait | Air extrait
Tube | Mezzannine | 0.16 | 0.78288 | V_Air_extrait | Air extrait
Tube | Mezzannine | 0.4 | 2.89936 | V_Air_extrait | Air extrait
Tube | Mezzannine | 0.45 | 4.22117 | V_Air_extrait | Air extrait
Tube | Mezzannine | 0.16 | 0.498919 | V_Air_extrait | Air extrait
Tube | Mezzannine | 0.16 | 0.334029 | V_Air_extrait | Air extrait
Tube | Mezzannine | 0.16 | 0.224387 | V_Air_extrait | Air extrait
Tube | Mezzannine | 0.16 | 1.09933 | V_Air_extrait | Air extrait | 0.816191 | 0.0555556 | 2.76311
Tube | Mezzannine | 0.16 | 0.226709 | V_Air_extrait | Air extrait | 0.168318 | 0.0555556 | 2.76311
Tube | Mezzannine | 0.16 | 0.302322 | V_Air_extrait | Air extrait | 0.224456 | 0.0555556 | 2.76311
Tube | Mezzannine | 0.16 | 0.425612 | V_Air_extrait | Air extrait | 0.315991 | 0.0555556 | 2.76311
Tube | Mezzannine | 0.16 | 0.208597 | V_Air_extrait | Air extrait | 0.154871 | 0.0555556 | 2.76311
Tube | Mezzannine | 0.16 | 1.92386 | V_Air_extrait | Air extrait
Tube | Mezzannine | 0.25 | 1.93846 | V_Air_extrait | Air extrait
Tube | R+1 | 0.25 | 0.159302 | V_Air_extrait | Air extrait | 0.0989324 | 0.166667 | 3.39531
7 x Tube | R+1 | 0.25 | 3 | V_Air_extrait | Air extrait | 1.86312 | 0.166667 | 3.39531
Tube | R+1 | 0.25 | 0.787995 | V_Air_extrait | Air extrait | 0.489375 | 0.166667 | 3.39531
Tube | R+1 | 0.25 | 1.17296 | V_Air_extrait | Air extrait | 0.728452 | 0.166667 | 3.39531
Tube | R+1 | 0.16 | 0.664994 | V_Air_extrait | Air extrait | 0.493719 | 0.0555556 | 2.76311
Tube | R+1 | 0.16 | 0.911325 | V_Air_extrait | Air extrait | 0.676605 | 0.0555556 | 2.76311
Tube | R+1 | 0.2 | 0.371028 | V_Air_extrait | Air extrait | 0.327846 | 0.111111 | 3.53678
Tube | R+1 | 0.2 | 2.67001 | V_Air_extrait | Air extrait | 2.35926 | 0.111111 | 3.53678
3 x Tube | R+1 | 0.16 | 3 | V_Air_extrait | Air extrait | 2.22732 | 0.0555556 | 2.76311
Tube | R+1 | 0.16 | 0.53 | V_Air_extrait | Air extrait | 0.393494 | 0.0555556 | 2.76311
Tube | R+1 | 0.25 | 1.09047 | V_Air_extrait | Air extrait | 0.677223 | 0.166667 | 3.39531
Tube | R+1 | 0.45 | 0.182337 | V_Air_extrait | Air extrait | 0.0811509 | 0.666667 | 4.19174
Tube | R+1 | 0.45 | 3 | V_Air_extrait | Air extrait | 1.33518 | 0.666667 | 4.19174
Tube | R+1 | 0.45 | 0.754662 | V_Air_extrait | Air extrait | 0.33587 | 0.666667 | 4.19174
Tube | R+1 | 0.4 | 2.98009 | V_Air_extrait | Air extrait | 2.0212 | 0.611111 | 4.86307
Tube | R+1 | 0.4 | 0.865865 | V_Air_extrait | Air extrait | 0.49155 | 0.555556 | 4.42097
Tube | R+1 | 0.4 | 1 | V_Air_extrait | Air extrait | 0.46662 | 0.5 | 3.97887
Tube | R+1 | 0.4 | 2.01457 | V_Air_extrait | Air extrait | 0.940038 | 0.5 | 3.97887
Tube | R+1 | 0.355 | 2.67089 | V_Air_extrait | Air extrait | 1.80695 | 0.444444 | 4.49025
Tube | R+1 | 0.315 | 3 | V_Air_extrait | Air extrait | 2.86267 | 0.388889 | 4.99016
Tube | R+1 | 0.315 | 0.52 | V_Air_extrait | Air extrait | 0.496196 | 0.388889 | 4.99016
Tube | R+1 | 0.315 | 3 | V_Air_extrait | Air extrait | 2.14771 | 0.333333 | 4.27728
Tube | R+1 | 0.315 | 0.74 | V_Air_extrait | Air extrait | 0.529768 | 0.333333 | 4.27728
Tube | R+1 | 0.315 | 1.43595 | V_Air_extrait | Air extrait | 0.733056 | 0.277778 | 3.5644
Tube | R+1 | 0.16 | 0.211359 | V_Air_extrait | Air extrait | 0.156922 | 0.0555556 | 2.76311
Tube | R+1 | 0.16 | 1.18634 | V_Air_extrait | Air extrait | 0.88079 | 0.0555556 | 2.76311
6 x Tube | R+1 | 0.315 | 3 | V_Air_extrait | Air extrait | 1.5315 | 0.277778 | 3.5644
Tube | R+1 | 0.315 | 1.27718 | V_Air_extrait | Air extrait | 0.652004 | 0.277778 | 3.5644
Tube | R+1 | 0.315 | 2.43176 | V_Air_extrait | Air extrait | 1.24142 | 0.277778 | 3.5644
Tube | R+1 | 0.16 | 0.436859 | V_Air_extrait | Air extrait | 0.324342 | 0.0555556 | 2.76311
Tube | R+1 | 0.16 | 0.441839 | V_Air_extrait | Air extrait | 0.328039 | 0.0555556 | 2.76311
Tube | R+1 | 0.2 | 0.32454 | V_Air_extrait | Air extrait | 0.286769 | 0.111111 | 3.53678
Tube | R+1 | 0.2 | 1.79875 | V_Air_extrait | Air extrait | 1.5894 | 0.111111 | 3.53678
Tube | R+1 | 0.16 | 0.495143 | V_Air_extrait | Air extrait | 0.367614 | 0.0555556 | 2.76311
Tube | R+1 | 0.16 | 0.532898 | V_Air_extrait | Air extrait | 0.395645 | 0.0555556 | 2.76311
Tube | R+1 | 0.5 | 3 | V_Air_extrait | Air extrait | 1.2014 | 0.833333 | 4.24413
Tube | R+1 | 0.5 | 0.805864 | V_Air_extrait | Air extrait | 0.00833937 | 0.111111 | 0.565884
Tube | R+1 | 0.16 | 1.4598 | V_Air_soufflé | Air soufflé | 1.08381 | 0.0555556 | 2.76311
3 x Tube | R+1 | 0.315 | 3 | V_Air_soufflé | Air soufflé | 2.86267 | 0.388889 | 4.99016
Tube | R+1 | 0.315 | 2.53767 | V_Air_soufflé | Air soufflé | 2.42151 | 0.388889 | 4.99016
Tube | R+1 | 0.2 | 0.708534 | V_Air_soufflé | Air soufflé | 0.626072 | 0.111111 | 3.53678
3 x Tube | R+1 | 0.2 | 3 | V_Air_soufflé | Air soufflé | 2.65085 | 0.111111 | 3.53678
Tube | R+1 | 0.2 | 2.59626 | V_Air_soufflé | Air soufflé | 2.2941 | 0.111111 | 3.53678
Tube | R+1 | 0.2 | 1 | V_Air_soufflé | Air soufflé | 0.249554 | 0.0555556 | 1.76839
Tube | R+1 | 0.2 | 2.09964 | V_Air_soufflé | Air soufflé | 0.523973 | 0.0555556 | 1.76839
2 x Tube | R+1 | 0.315 | 3 | V_Air_soufflé | Air soufflé | 2.14771 | 0.333333 | 4.27728
3 x Tube | R+1 | 0.315 | 3 | V_Air_soufflé | Air soufflé | 1.5315 | 0.277778 | 3.5644
10 x Tube | R+1 | 0.315 | 3 | V_Air_soufflé | Air soufflé | 1.01498 | 0.222222 | 2.85152
Tube | R+1 | 0.315 | 2.80466 | V_Air_soufflé | Air soufflé | 0.560583 | 0.166667 | 2.13864
Tube | R+1 | 0.16 | 0.635202 | V_Air_soufflé | Air soufflé | 0.4716 | 0.0555556 | 2.76311
Tube | R+1 | 0.315 | 1.92027 | V_Air_soufflé | Air soufflé | 0.980302 | 0.277778 | 3.5644
Tube | R+1 | 0.315 | 2.69434 | V_Air_soufflé | Air soufflé | 0.911566 | 0.222222 | 2.85152
Tube | R+1 | 0.315 | 2.87599 | V_Air_soufflé | Air soufflé | 0.973024 | 0.222222 | 2.85152
Tube | R+1 | 0.315 | 0.720515 | V_Air_soufflé | Air soufflé | 0.24377 | 0.222222 | 2.85152
Tube | R+1 | 0.315 | 0.441336 | V_Air_soufflé | Air soufflé | 0.149316 | 0.222222 | 2.85152
Tube | R+1 | 0.315 | 0.596559 | V_Air_soufflé | Air soufflé | 0.201832 | 0.222222 | 2.85152
Tube | R+1 | 0.315 | 0.966976 | V_Air_soufflé | Air soufflé | 0.327154 | 0.222222 | 2.85152
Tube | R+1 | 0.16 | 1.10585 | V_Air_soufflé | Air soufflé | 0.821026 | 0.0555556 | 2.76311
Tube | R+1 | 0.16 | 0.530525 | V_Air_soufflé | Air soufflé | 0.393883 | 0.0555556 | 2.76311
2 x Tube | R+1 | 0.16 | 0.278954 | V_Air_soufflé | Air soufflé | 0.207107 | 0.0555556 | 2.76311
Tube | R+1 | 0.315 | 2.56391 | V_Air_soufflé | Air soufflé | 0.867439 | 0.222222 | 2.85152
Tube | R+1 | 0.2 | 1.50811 | V_Air_soufflé | Air soufflé | 1.33259 | 0.111111 | 3.53678
Tube | R+1 | 0.16 | 1.18835 | V_Air_soufflé | Air soufflé | 0.882277 | 0.0555556 | 2.76311
Tube | R+1 | 0.16 | 0.671089 | V_Air_soufflé | Air soufflé | 0.498244 | 0.0555556 | 2.76311
Tube | R+1 | 0.16 | 0.578263 | V_Air_soufflé | Air soufflé | 0.429326 | 0.0555556 | 2.76311
Tube | R+1 | 0.25 | 0.376015 | V_Air_extrait | Air extrait | 0.23352 | 0.166667 | 3.39531
Tube | R+1 | 0.25 | 0.156554 | V_Air_extrait | Air extrait | 0.097226 | 0.166667 | 3.39531
Tube | R+1 | 0.16 | 1.28246 | V_Air_extrait | Air extrait
Tube | R+1 | 0.16 | 0.402921 | V_Air_extrait | Air extrait
Tube | R+1 | 0.16 | 1.10242 | V_Air_extrait | Air extrait
Tube | R+1 | 0.16 | 0.931965 | V_Air_extrait | Air extrait
Tube | R+1 | 0.16 | 0.402956 | V_Air_extrait | Air extrait
Tube | R+1 | 0.16 | 0.193647 | V_Air_soufflé | Air soufflé
Tube | R+1 | 0.315 | 0.371656 | V_Air_soufflé | Air soufflé
Tube | R+1 | 0.315 | 0.532121 | V_Air_soufflé | Air soufflé
Tube | R+1 | 0.315 | 2.52562 | V_Air_extrait | Air extrait
Tube | R+1 | 0.16 | 3.40258 | V_Air_extrait | Air extrait
Tube | R+1 | 0.16 | 1.5176 | V_Air_extrait | Air extrait
Tube | R+1 | 0.16 | 0.489537 | V_Air_extrait | Air extrait
Tube | R+1 | 0.16 | 0.460619 | V_Air_extrait | Air extrait
2 x Tube | R+1 | 0.16 | 0.480619 | V_Air_extrait | Air extrait
Tube | R+1 | 0.16 | 2.2176 | V_Air_extrait | Air extrait
Tube | R+1 | 0.315 | 2.25446 | V_Air_soufflé | Air soufflé
Tube | R+1 | 0.315 | 2.14235 | V_Air_soufflé | Air soufflé
Tube | R+1 | 0.315 | 6 | V_Air_soufflé | Air soufflé
Tube | R+1 | 0.315 | 0.691149 | V_Air_soufflé | Air soufflé
Tube | R+1 | 0.315 | 0.415547 | V_Air_extrait | Air extrait
2 x Tube | R+1 | 0.315 | 6 | V_Air_extrait | Air extrait
Tube | R+1 | 0.315 | 1.94942 | V_Air_extrait | Air extrait
Tube | R+1 | 0.315 | 1.73644 | V_Air_extrait | Air extrait
Tube | R+1 | 0.315 | 1.14069 | V_Air_extrait | Air extrait
Tube | R+1 | 0.315 | 2.93497 | V_Air_extrait | Air extrait
Tube | R+1 | 0.315 | 5 | V_Air_extrait | Air extrait | 0.867439 | 0.222222 | 2.85152
2 x Tube | R+1 | 0.16 | 1.10585 | V_Air_extrait | Air extrait | 0.821026 | 0.0555556 | 2.76311
Tube | R+1 | 0.2 | 4.94401 | V_Air_extrait | Air extrait
Tube | R+1 | 0.16 | 0.52714 | V_Air_soufflé | Air soufflé
Tube | R+1 | 0.16 | 1 | V_Air_extrait | Air extrait | 0.742441 | 0.0555556 | 2.76311
Tube | R+1 | 0.16 | 0.162908 | V_Air_extrait | Air extrait | 0.120949 | 0.0555556 | 2.76311
Tube | R+1 | 0.16 | 0.344749 | V_Air_extrait | Air extrait | 0.255955 | 0.0555556 | 2.76311
Tube | R+1 | 0.16 | 0.352861 | V_Air_extrait | Air extrait | 0.261978 | 0.0555556 | 2.76311
Tube | R+1 | 0.16 | 0.251023 | V_Air_extrait | Air extrait | 0.18637 | 0.0555556 | 2.76311
Tube | R+1 | 0.16 | 2.23437 | V_Air_extrait | Air extrait | 1.65889 | 0.0555556 | 2.76311
Tube | R+1 | 0.2 | 0.188425 | V_Air_extrait | Air extrait
Tube | R+1 | 0.2 | 0.894075 | V_Air_extrait | Air extrait
Tube | R+1 | 0.25 | 1.70982 | V_Air_extrait | Air extrait
2 x Tube | Rez de chaussŽe | 0.355 | 3 | V_Air_soufflé | Air soufflé | 2.0296 | 0.444444 | 4.49025
Tube | Rez de chaussŽe | 0.355 | 1.35518 | V_Air_soufflé | Air soufflé | 0.916829 | 0.444444 | 4.49025
Tube | Rez de chaussŽe | 0.355 | 1.86878 | V_Air_soufflé | Air soufflé | 1.2643 | 0.444444 | 4.49025
Tube | Rez de chaussŽe | 0.16 | 0.800001 | V_Air_soufflé | Air soufflé | 0.593953 | 0.0555556 | 2.76311
19 x Tube | Rez de chaussŽe | 0.16 | 0.16 | V_Air_soufflé | Air soufflé | 0.11879 | 0.0555556 | 2.76311
2 x Tube | Rez de chaussŽe | 0.315 | 3 | V_Air_soufflé | Air soufflé | 2.86267 | 0.388889 | 4.99016
Tube | Rez de chaussŽe | 0.315 | 0.520003 | V_Air_soufflé | Air soufflé | 0.496199 | 0.388889 | 4.99016
3 x Tube | Rez de chaussŽe | 0.16 | 0.820001 | V_Air_soufflé | Air soufflé | 0.608802 | 0.0555556 | 2.76311
2 x Tube | Rez de chaussŽe | 0.315 | 3 | V_Air_soufflé | Air soufflé | 2.14771 | 0.333333 | 4.27728
2 x Tube | Rez de chaussŽe | 0.315 | 0.74 | V_Air_soufflé | Air soufflé | 0.529768 | 0.333333 | 4.27728
2 x Tube | Rez de chaussŽe | 0.315 | 3 | V_Air_soufflé | Air soufflé | 1.5315 | 0.277778 | 3.5644
2 x Tube | Rez de chaussŽe | 0.315 | 0.74 | V_Air_soufflé | Air soufflé | 0.377771 | 0.277778 | 3.5644
Tube | Rez de chaussŽe | 0.25 | 0.425484 | V_Air_soufflé | Air soufflé | 0.450294 | 0.222222 | 4.52707
Tube | Rez de chaussŽe | 0.16 | 2.36152 | V_Air_soufflé | Air soufflé | 1.75329 | 0.0555556 | 2.76311
Tube | Rez de chaussŽe | 0.16 | 0.870001 | V_Air_soufflé | Air soufflé | 0.645924 | 0.0555556 | 2.76311
3 x Tube | Rez de chaussŽe | 0.25 | 3 | V_Air_soufflé | Air soufflé | 1.86312 | 0.166667 | 3.39531
Tube | Rez de chaussŽe | 0.25 | 1.29 | V_Air_soufflé | Air soufflé | 0.801139 | 0.166667 | 3.39531
Tube | Rez de chaussŽe | 0.25 | 0.620247 | V_Air_soufflé | Air soufflé | 0.385197 | 0.166667 | 3.39531
Tube | Rez de chaussŽe | 0.16 | 0.585001 | V_Air_soufflé | Air soufflé | 0.434328 | 0.0555556 | 2.76311
2 x Tube | Rez de chaussŽe | 0.2 | 3 | V_Air_soufflé | Air soufflé | 2.65085 | 0.111111 | 3.53678
2 x Tube | Rez de chaussŽe | 0.2 | 0.506 | V_Air_soufflé | Air soufflé | 0.44711 | 0.111111 | 3.53678
10 x Tube | Rez de chaussŽe | 0.16 | 3 | V_Air_soufflé | Air soufflé | 2.22732 | 0.0555556 | 2.76311
Tube | Rez de chaussŽe | 0.16 | 0.597297 | V_Air_soufflé | Air soufflé | 0.443457 | 0.0555556 | 2.76311
Tube | Rez de chaussŽe | 0.16 | 0.610001 | V_Air_soufflé | Air soufflé | 0.452889 | 0.0555556 | 2.76311
Tube | Rez de chaussŽe | 0.16 | 0.134094 | V_Air_soufflé | Air soufflé | 0.0995565 | 0.0555556 | 2.76311
Tube | Rez de chaussŽe | 0.16 | 0.40653 | V_Air_soufflé | Air soufflé | 0.301824 | 0.0555556 | 2.76311
Tube | Rez de chaussŽe | 0.4 | 2.30637 | V_Air_soufflé | Air soufflé | 1.0762 | 0.5 | 3.97887
Tube | Rez de chaussŽe | 0.4 | 1 | V_Air_soufflé | Air soufflé | 0.46662 | 0.5 | 3.97887
Tube | Rez de chaussŽe | 0.4 | 2.10539 | V_Air_soufflé | Air soufflé | 0.982418 | 0.5 | 3.97887
Tube | Rez de chaussŽe | 0.355 | 0.474371 | V_Air_soufflé | Air soufflé | 0.320928 | 0.444444 | 4.49025
Tube | Rez de chaussŽe | 0.315 | 0.504572 | V_Air_soufflé | Air soufflé | 0.481474 | 0.388889 | 4.99016
3 x Tube | Rez de chaussŽe | 0.16 | 2.5861 | V_Air_soufflé | Air soufflé | 1.92003 | 0.0555556 | 2.76311
Tube | Rez de chaussŽe | 0.25 | 3 | V_Air_soufflé | Air soufflé | 3.17494 | 0.222222 | 4.52707
Tube | Rez de chaussŽe | 0.25 | 0.486 | V_Air_soufflé | Air soufflé | 0.51434 | 0.222222 | 4.52707
2 x Tube | Rez de chaussŽe | 0.16 | 2.6211 | V_Air_soufflé | Air soufflé | 1.94601 | 0.0555556 | 2.76311
Tube | Rez de chaussŽe | 0.25 | 0.74 | V_Air_soufflé | Air soufflé | 0.459569 | 0.166667 | 3.39531
Tube | Rez de chaussŽe | 0.16 | 2.6461 | V_Air_soufflé | Air soufflé | 1.96457 | 0.0555556 | 2.76311
Tube | Rez de chaussŽe | 0.16 | 0.53 | V_Air_soufflé | Air soufflé | 0.393494 | 0.0555556 | 2.76311
Tube | Rez de chaussŽe | 0.16 | 2.6361 | V_Air_soufflé | Air soufflé | 1.95715 | 0.0555556 | 2.76311
Tube | Rez de chaussŽe | 0.16 | 2.54758 | V_Air_soufflé | Air soufflé | 1.89143 | 0.0555556 | 2.76311
Tube | Rez de chaussŽe | 0.16 | 1.59915 | V_Air_soufflé | Air soufflé | 1.18728 | 0.0555556 | 2.76311
Tube | Rez de chaussŽe | 0.25 | 1 | V_Air_extrait | Air extrait | 0.621039 | 0.166667 | 3.39531
Tube | Rez de chaussŽe | 0.25 | 2.26106 | V_Air_extrait | Air extrait | 1.4042 | 0.166667 | 3.39531
2 x Tube | Rez de chaussŽe | 0.16 | 0.575949 | V_Air_extrait | Air extrait | 0.427608 | 0.0555556 | 2.76311
Tube | Rez de chaussŽe | 0.16 | 0.653949 | V_Air_extrait | Air extrait | 0.485518 | 0.0555556 | 2.76311
Tube | Rez de chaussŽe | 0.16 | 0.0972662 | V_Air_extrait | Air extrait | 0.0722144 | 0.0555556 | 2.76311
4 x Tube | Rez de chaussŽe | 0.25 | 3 | V_Air_extrait | Air extrait | 1.86312 | 0.166667 | 3.39531
Tube | Rez de chaussŽe | 0.25 | 1.3226 | V_Air_extrait | Air extrait | 0.111939 | 0.0555556 | 1.13177
Tube | Rez de chaussŽe | 0.5 | 0.55 | V_Air_extrait | Air extrait | 0.248435 | 0.888889 | 4.52707
6 x Tube | Rez de chaussŽe | 0.5 | 3 | V_Air_extrait | Air extrait | 1.3551 | 0.888889 | 4.52707
Tube | Rez de chaussŽe | 0.5 | 2.86501 | V_Air_extrait | Air extrait | 1.29413 | 0.888889 | 4.52707
Tube | Rez de chaussŽe | 0.5 | 1.86297 | V_Air_extrait | Air extrait | 0.841503 | 0.888889 | 4.52707
Tube | Rez de chaussŽe | 0.5 | 2.37001 | V_Air_extrait | Air extrait | 1.07053 | 0.888889 | 4.52707
2 x Tube | Rez de chaussŽe | 0.16 | 0.431298 | V_Air_extrait | Air extrait | 0.320213 | 0.0555556 | 2.76311
32 x Tube | Rez de chaussŽe | 0.16 | 0.16 | V_Air_extrait | Air extrait | 0.11879 | 0.0555556 | 2.76311
Tube | Rez de chaussŽe | 0.5 | 3 | V_Air_extrait | Air extrait | 1.2014 | 0.833333 | 4.24413
Tube | Rez de chaussŽe | 0.5 | 0.74 | V_Air_extrait | Air extrait | 0.296345 | 0.833333 | 4.24413
3 x Tube | Rez de chaussŽe | 0.16 | 0.456298 | V_Air_extrait | Air extrait | 0.338774 | 0.0555556 | 2.76311
2 x Tube | Rez de chaussŽe | 0.45 | 3 | V_Air_extrait | Air extrait | 1.78024 | 0.777778 | 4.89036
Tube | Rez de chaussŽe | 0.45 | 3 | V_Air_extrait | Air extrait | 1.55004 | 0.722222 | 4.54105
2 x Tube | Rez de chaussŽe | 0.45 | 3 | V_Air_extrait | Air extrait | 1.33518 | 0.666667 | 4.19174
Tube | Rez de chaussŽe | 0.45 | 0.490801 | V_Air_extrait | Air extrait | 0.185802 | 0.611111 | 3.84242
Tube | Rez de chaussŽe | 0.4 | 2.4112 | V_Air_extrait | Air extrait | 1.36883 | 0.555556 | 4.42097
2 x Tube | Rez de chaussŽe | 0.4 | 3 | V_Air_extrait | Air extrait | 1.39986 | 0.5 | 3.97887
2 x Tube | Rez de chaussŽe | 0.4 | 0.74 | V_Air_extrait | Air extrait | 0.345299 | 0.5 | 3.97887
3 x Tube | Rez de chaussŽe | 0.16 | 0.503798 | V_Air_extrait | Air extrait | 0.37404 | 0.0555556 | 2.76311
2 x Tube | Rez de chaussŽe | 0.355 | 3 | V_Air_extrait | Air extrait | 2.0296 | 0.444444 | 4.49025
Tube | Rez de chaussŽe | 0.355 | 3 | V_Air_extrait | Air extrait | 1.58325 | 0.388889 | 3.92897
Tube | Rez de chaussŽe | 0.355 | 3 | V_Air_extrait | Air extrait | 1.19006 | 0.333333 | 3.36769
Tube | Rez de chaussŽe | 0.355 | 3 | V_Air_extrait | Air extrait | 0.850442 | 0.277778 | 2.80641
Tube | Rez de chaussŽe | 0.355 | 0.463 | V_Air_extrait | Air extrait | 0.131252 | 0.277778 | 2.80641
4 x Tube | Rez de chaussŽe | 0.16 | 0.523798 | V_Air_extrait | Air extrait | 0.388889 | 0.0555556 | 2.76311
2 x Tube | Rez de chaussŽe | 0.315 | 3 | V_Air_extrait | Air extrait | 1.01498 | 0.222222 | 2.85152
Tube | Rez de chaussŽe | 0.315 | 3 | V_Air_extrait | Air extrait | 0.599625 | 0.166667 | 2.13864
Tube | Rez de chaussŽe | 0.315 | 3 | V_Air_extrait | Air extrait | 0.287667 | 0.111111 | 1.42576
Tube | Rez de chaussŽe | 0.315 | 3 | V_Air_extrait | Air extrait | 0.0834794 | 0.0555556 | 0.71288
Tube | Rez de chaussŽe | 0.315 | 1.28428 | V_Air_extrait | Air extrait | 0.0357371 | 0.0555556 | 0.71288
Tube | Rez de chaussŽe | 0.16 | 0.501298 | V_Air_extrait | Air extrait | 0.372184 | 0.0555556 | 2.76311
2 x Tube | Rez de chaussŽe | 0.16 | 0.481298 | V_Air_extrait | Air extrait | 0.357335 | 0.0555556 | 2.76311
Tube | Rez de chaussŽe | 0.16 | 0.586011 | V_Air_extrait | Air extrait | 0.435079 | 0.0555556 | 2.76311
Tube | Rez de chaussŽe | 0.25 | 1.30601 | V_Air_extrait | Air extrait | 0.385752 | 0.111111 | 2.26354
Tube | Rez de chaussŽe | 0.16 | 1.11292 | V_Air_extrait | Air extrait | 0.826278 | 0.0555556 | 2.76311
Tube | Rez de chaussŽe | 0.16 | 3 | V_Air_extrait | Air extrait | 2.22732 | 0.0555556 | 2.76311
Tube | Rez de chaussŽe | 0.16 | 0.416143 | V_Air_extrait | Air extrait | 0.308961 | 0.0555556 | 2.76311
Tube | Rez de chaussŽe | 0.25 | 1.87 | V_Air_extrait | Air extrait | 1.16134 | 0.166667 | 3.39531
Tube | Rez de chaussŽe | 0.45 | 0.564284 | V_Air_extrait | Air extrait | 0.291555 | 0.722222 | 4.54105
Tube | Rez de chaussŽe | 0.4 | 2.94789 | V_Air_extrait | Air extrait | 1.67351 | 0.555556 | 4.42097
Tube | Rez de chaussŽe | 0.315 | 1.45277 | V_Air_extrait | Air extrait | 1.38626 | 0.388889 | 4.99016
Tube | Rez de chaussŽe | 0.315 | 2.87583 | V_Air_extrait | Air extrait | 2.74418 | 0.388889 | 4.99016
3 x Tube | Rez de chaussŽe | 0.16 | 2.83757 | V_Air_extrait | Air extrait | 2.10673 | 0.0555556 | 2.76311
Tube | Rez de chaussŽe | 0.315 | 3 | V_Air_extrait | Air extrait | 2.86267 | 0.388889 | 4.99016
Tube | Rez de chaussŽe | 0.315 | 3 | V_Air_extrait | Air extrait | 2.14771 | 0.333333 | 4.27728
2 x Tube | Rez de chaussŽe | 0.315 | 3 | V_Air_extrait | Air extrait | 1.5315 | 0.277778 | 3.5644
Tube | Rez de chaussŽe | 0.315 | 1.03314 | V_Air_extrait | Air extrait | 0.34954 | 0.222222 | 2.85152
Tube | Rez de chaussŽe | 0.16 | 2.87007 | V_Air_extrait | Air extrait | 2.13086 | 0.0555556 | 2.76311
Tube | Rez de chaussŽe | 0.25 | 3 | V_Air_extrait | Air extrait | 0.886105 | 0.111111 | 2.26354
Tube | Rez de chaussŽe | 0.16 | 0.380693 | V_Air_extrait | Air extrait | 0.282642 | 0.0555556 | 2.76311
Tube | Rez de chaussŽe | 0.16 | 2.83507 | V_Air_extrait | Air extrait | 2.10487 | 0.0555556 | 2.76311
Tube | Rez de chaussŽe | 0.16 | 1.06203 | V_Air_extrait | Air extrait | 0.788491 | 0.0555556 | 2.76311
Tube | Rez de chaussŽe | 0.16 | 0.553476 | V_Air_extrait | Air extrait | 0 | 0
Tube | Rez de chaussŽe | 0.16 | 1.4054 | V_Air_extrait | Air extrait
Tube | Rez de chaussŽe | 0.16 | 0.303338 | V_Air_soufflé | Air soufflé
Tube | Rez de chaussŽe | 0.4 | 1 | V_Air_soufflé | Air soufflé
Tube | Rez de chaussŽe | 0.4 | 2.29401 | V_Air_soufflé | Air soufflé
Tube | Rez de chaussŽe | 0.4 | 2.27673 | V_Air_soufflé | Air soufflé
Tube | Rez de chaussŽe | 0.16 | 0.444132 | V_Air_soufflé | Air soufflé
Tube | Rez de chaussŽe | 0.16 | 0.330046 | V_Air_soufflé | Air soufflé
Tube | Rez de chaussŽe | 0.16 | 0.1238 | V_Air_soufflé | Air soufflé
Tube | Rez de chaussŽe | 0.5 | 2.49 | V_Air_extrait | Air extrait
Tube | Rez de chaussŽe | 0.45 | 0.975 | V_Air_extrait | Air extrait
Tube | Rez de chaussŽe | 0.25 | 0.32 | V_Air_extrait | Air extrait
Tube | Rez de chaussŽe | 0.355 | 1.37839 | V_Air_soufflé | Air soufflé
Tube | Rez de chaussŽe | 0.5 | 1.77021 | V_Air_extrait | Air extrait
Tube | Rez de chaussŽe | 0.16 | 0.503919 | V_Désenfumage | Désenfumage
Tube | Rez de chaussŽe | 0.16 | 3 | V_Désenfumage | Désenfumage
Tube | Rez de chaussŽe | 0.16 | 1.20941 | V_Désenfumage | Désenfumage
Tube | Rez de chaussŽe | 0.16 | 0.835368 | V_Air_extrait | Air extrait
Tube | Rez de chaussŽe | 0.16 | 1.10831 | V_Air_extrait | Air extrait
Tube | Rez de chaussŽe | 0.16 | 1.03703 | V_Air_extrait | Air extrait
Tube | Rez de chaussŽe | 0.4 | 2.09237 | V_Air_extrait | Air extrait
Tube | Rez de chaussŽe | 0.45 | 2.46816 | V_Air_extrait | Air extrait
Tube | Rez de chaussŽe | 0.4 | 0.423783 | V_Air_extrait | Air extrait
Tube | Rez de chaussŽe | 0.16 | 0.891433 | V_Air_extrait | Air extrait
Tube | Rez de chaussŽe | 0.355 | 2.1726 | V_Air_extrait | Air extrait
Tube | Rez de chaussŽe | 0.16 | 1.11561 | V_Air_extrait | Air extrait
Tube | Rez de chaussŽe | 0.16 | 0.239169 | V_Air_extrait | Air extrait
2 x Tube | Rez de chaussŽe | 0.16 | 0.85 | V_Air_extrait | Air extrait
Tube | Rez de chaussŽe | 0.16 | 0.846744 | V_Air_extrait | Air extrait
Tube | Rez de chaussŽe | 0.16 | 6 | V_Air_extrait | Air extrait
Tube | Rez de chaussŽe | 0.16 | 1.2734 | V_Air_extrait | Air extrait
Tube | Rez de chaussŽe | 0.16 | 0.302369 | V_Air_extrait | Air extrait | 0.224491 | 0.0555556 | 2.76311
Tube | Rez de chaussŽe | 0.16 | 0.56372 | V_Air_extrait | Air extrait | 0.418529 | 0.0555556 | 2.76311
Tube | Rez de chaussŽe | 0.16 | 1.09933 | V_Air_extrait | Air extrait
Tube | Rez de chaussŽe | 0.16 | 0.208597 | V_Air_extrait | Air extrait | 0.154871 | 0.0555556 | 2.76311

# IfcFlowSegment: Tube acier d'après DIN 2448 (185)
In: Rez de chaussŽe
Description: Tube acier d'après DIN 2448
Pset Plancal nova - MEP - Nom: Tube acier d'après DIN 2448
Name | Geom-Ø exterieur (m) (m) | Geom-DN | Geom-Longueur (m) (m) | Tech-Material | Tech-Epaisseur isolant (m) (m) | Group
Tube acier d'après DIN 2448 | 0.0761 | 65 | 0.171747 | Tube acier d'après DIN 2448 | 0 | Eau froide
Tube acier d'après DIN 2448 | 0.0761 | 65 | 0.143072 | Tube acier d'après DIN 2448 | 0 | Eau froide
Tube acier d'après DIN 2448 | 0.0761 | 65 | 0.0702641 | Tube acier d'après DIN 2448 | 0 | Eau froide
Tube acier d'après DIN 2448 | 0.0761 | 65 | 0.307948 | Tube acier d'après DIN 2448 | 0 | Eau froide
Tube acier d'après DIN 2448 | 0.0603 | 50 | 1.2 | Acier | 0.02 | Retour
Tube acier d'après DIN 2448 | 0.0337 | 25 | 0.366742 | Acier | 0.02 | Aller
Tube acier d'après DIN 2448 | 0.0269 | 20 | 0.112789 | Acier | 0.02 | Retour
Tube acier d'après DIN 2448 | 0.0424 | 32 | 0.102901 | Acier | 0.02 | Aller
Tube acier d'après DIN 2448 | 0.0483 | 40 | 0.301639 | Acier | 0.02 | Aller
Tube acier d'après DIN 2448 | 0.0424 | 32 | 0.0520055 | Acier | 0.02 | Retour
Tube acier d'après DIN 2448 | 0.0269 | 20 | 0.0806475 | Acier | 0.02 | Aller
Tube acier d'après DIN 2448 | 0.0337 | 25 | 0.287755 | Acier | 0.02 | Retour
Tube acier d'après DIN 2448 | 0.0337 | 25 | 1.13723 | Acier | 0.02 | Retour
2 x Tube acier d'après DIN 2448 | 0.0337 | 25 | 0.0929475 | Acier | 0.02 | Aller
Tube acier d'après DIN 2448 | 0.0483 | 40 | 0.19953 | Acier | 0.02 | Retour
Tube acier d'après DIN 2448 | 0.0424 | 32 | 0.168547 | Acier | 0 | Retour
Tube acier d'après DIN 2448 | 0.0424 | 32 | 0.0748475 | Acier | 0.02 | Aller
Tube acier d'après DIN 2448 | 0.0269 | 20 | 0.1 | Acier | 0 | Aller
Tube acier d'après DIN 2448 | 0.0603 | 50 | 0.128909 | Acier | 0.02 | Aller
2 x Tube acier d'après DIN 2448 | 0.0269 | 20 | 0.137301 | Acier | 0.02 | Aller
2 x Tube acier d'après DIN 2448 | 0.0337 | 25 | 0.149949 | Acier | 0.02 | Aller
Tube acier d'après DIN 2448 | 0.0337 | 25 | 0.303839 | Acier | 0.02 | Aller
Tube acier d'après DIN 2448 | 0.0269 | 20 | 0.0677055 | Acier | 0.02 | Retour
Tube acier d'après DIN 2448 | 0.0424 | 32 | 0.201449 | Acier | 0.02 | Aller
Tube acier d'après DIN 2448 | 0.0483 | 40 | 0.0212475 | Acier | 0.02 | Aller
2 x Tube acier d'après DIN 2448 | 0.0269 | 20 | 0.219313 | Acier | 0.02 | Aller
Tube acier d'après DIN 2448 | 0.0269 | 20 | 0.366842 | Acier | 0.02 | Aller
Tube acier d'après DIN 2448 | 0.0337 | 25 | 0.350742 | Acier | 0.02 | Aller
Tube acier d'après DIN 2448 | 0.0269 | 20 | 1.19262 | Acier | 0.02 | Retour
Tube acier d'après DIN 2448 | 0.0269 | 20 | 0.1105 | Acier | 0.02 | Retour
Tube acier d'après DIN 2448 | 0.0337 | 25 | 0.153513 | Acier | 0.02 | Aller
Tube acier d'après DIN 2448 | 0.0269 | 20 | 0.1 | Acier | 0 | Retour
Tube acier d'après DIN 2448 | 0.0424 | 32 | 0.337542 | Acier | 0.02 | Aller
Tube acier d'après DIN 2448 | 0.0337 | 25 | 0.237755 | Acier | 0.02 | Retour
Tube acier d'après DIN 2448 | 0.0213 | 15 | 0.0572712 | Acier | 0 | Aller
Tube acier d'après DIN 2448 | 0.0603 | 50 | 1.2 | Acier | 0.02 | Aller
Tube acier d'après DIN 2448 | 0.0269 | 20 | 0.0528155 | Acier | 0.02 | Retour
Tube acier d'après DIN 2448 | 0.0483 | 40 | 0.328142 | Acier | 0.02 | Aller
Tube acier d'après DIN 2448 | 0.0424 | 32 | 0.0961 | Acier | 0.02 | Retour
Tube acier d'après DIN 2448 | 0.0269 | 20 | 0.181037 | Acier | 0.02 | Aller
Tube acier d'après DIN 2448 | 0.0269 | 20 | 0.314539 | Acier | 0.02 | Aller
Tube acier d'après DIN 2448 | 0.0337 | 25 | 0.237039 | Acier | 0.02 | Retour
Tube acier d'après DIN 2448 | 0.0337 | 25 | 0.319839 | Acier | 0.02 | Aller
Tube acier d'après DIN 2448 | 0.0424 | 32 | 1.16102 | Acier | 0.02 | Retour
Tube acier d'après DIN 2448 | 0.0269 | 20 | 0.038535 | Acier | 0.02 | Retour
Tube acier d'après DIN 2448 | 0.0337 | 25 | 1.18182 | Acier | 0.02 | Retour
Tube acier d'après DIN 2448 | 0.0213 | 15 | 0.0572712 | Acier | 0 | Retour
Tube acier d'après DIN 2448 | 0.0337 | 25 | 0.190237 | Acier | 0.02 | Aller
Tube acier d'après DIN 2448 | 0.0424 | 32 | 0.203431 | Acier | 0 | Aller
Tube acier d'après DIN 2448 | 0.0269 | 20 | 0.0541653 | Tube acier d'après DIN 2448 | 0.02 | Retour
Tube acier d'après DIN 2448 | 0.0424 | 32 | 0.02785 | Tube acier d'après DIN 2448 | 0.02 | Retour
Tube acier d'après DIN 2448 | 0.0483 | 40 | 1.15452 | Tube acier d'après DIN 2448 | 0 | Retour
Tube acier d'après DIN 2448 | 0.0483 | 40 | 0.0747298 | Tube acier d'après DIN 2448 | 0 | Retour
Tube acier d'après DIN 2448 | 0.0269 | 20 | 0.0626705 | Tube acier d'après DIN 2448 | 0.02 | Retour
Tube acier d'après DIN 2448 | 0.0269 | 20 | 0.05415 | Tube acier d'après DIN 2448 | 0.02 | Retour
Tube acier d'après DIN 2448 | 0.0269 | 20 | 0.066 | Tube acier d'après DIN 2448 | 0.02 | Aller
Tube acier d'après DIN 2448 | 0.0424 | 32 | 0.12859 | Tube acier d'après DIN 2448 | 0 | Aller
Tube acier d'après DIN 2448 | 0.0269 | 20 | 1.00101 | Tube acier d'après DIN 2448 | 0 | Aller
2 x Tube acier d'après DIN 2448 | 0.0337 | 25 | 1.28067 | Tube acier d'après DIN 2448 | 0.02 | Aller
Tube acier d'après DIN 2448 | 0.0483 | 40 | 1.28067 | Tube acier d'après DIN 2448 | 0.02 | Aller
Tube acier d'après DIN 2448 | 0.0269 | 20 | 1.28067 | Tube acier d'après DIN 2448 | 0.02 | Aller
3 x Tube acier d'après DIN 2448 | 0.0337 | 25 | 1.54757 | Tube acier d'après DIN 2448 | 0.02 | Retour
Tube acier d'après DIN 2448 | 0.0483 | 40 | 1.53047 | Tube acier d'après DIN 2448 | 0.02 | Retour
Tube acier d'après DIN 2448 | 0.0269 | 20 | 1.26791 | Tube acier d'après DIN 2448 | 0 | Retour
Tube acier d'après DIN 2448 | 0.0424 | 32 | 0.356834 | Tube acier d'après DIN 2448 | 0 | Retour
Tube acier d'après DIN 2448 | 0.0424 | 32 | 0.0752 | Acier | 0 | Aller
Tube acier d'après DIN 2448 | 0.0603 | 50 | 0.05 | Tube acier d'après DIN 2448 | 0 | Retour
Tube acier d'après DIN 2448 | 0.0603 | 50 | 0.05 | Tube acier d'après DIN 2448 | 0 | Medium
Tube acier d'après DIN 2448 | 0.0603 | 50 | 1 | Tube acier d'après DIN 2448 | 0 | Retour
Tube acier d'après DIN 2448 | 0.0603 | 50 | 1 | Tube acier d'après DIN 2448 | 0 | Medium
Tube acier d'après DIN 2448 | 0.0603 | 50 | 0.102738 | Tube acier d'après DIN 2448 | 0 | Medium
Tube acier d'après DIN 2448 | 0.0603 | 50 | 0.372942 | Tube acier d'après DIN 2448 | 0 | Retour
Tube acier d'après DIN 2448 | 0.0424 | 32 | 0.649 | Tube acier d'après DIN 2448 | 0 | Aller
Tube acier d'après DIN 2448 | 0.0424 | 32 | 0.658637 | Tube acier d'après DIN 2448 | 0 | Retour
Tube acier d'après DIN 2448 | 0.0337 | 25 | 0.366403 | Tube acier d'après DIN 2448 | 0 | Aller
Tube acier d'après DIN 2448 | 0.0337 | 25 | 0.0152352 | Tube acier d'après DIN 2448 | 0 | Aller
Tube acier d'après DIN 2448 | 0.0424 | 32 | 0.0383715 | Tube acier d'après DIN 2448 | 0 | Retour
Tube acier d'après DIN 2448 | 0.8 | 600 | 0.1 | Tube acier d'après DIN 2448 | 0 | Medium
Tube acier d'après DIN 2448 | 0.0603 | 50 | 1.5 | Tube acier d'après DIN 2448 | 0 | Medium
Tube acier d'après DIN 2448 | 0.0603 | 50 | 0.223292 | Tube acier d'après DIN 2448 | 0.02 | Retour
Tube acier d'après DIN 2448 | 0.0483 | 40 | 0.0368 | Tube acier d'après DIN 2448 | 0 | Eau chaude
Tube acier d'après DIN 2448 | 0.0483 | 40 | 0.332353 | Tube acier d'après DIN 2448 | 0 | Eau chaude
Tube acier d'après DIN 2448 | 0.0761 | 65 | 0.416517 | Tube acier d'après DIN 2448 | 0 | Eau froide
Tube acier d'après DIN 2448 | 0.0424 | 32 | 0.238864 | Tube acier d'après DIN 2448 | 0 | Eau froide
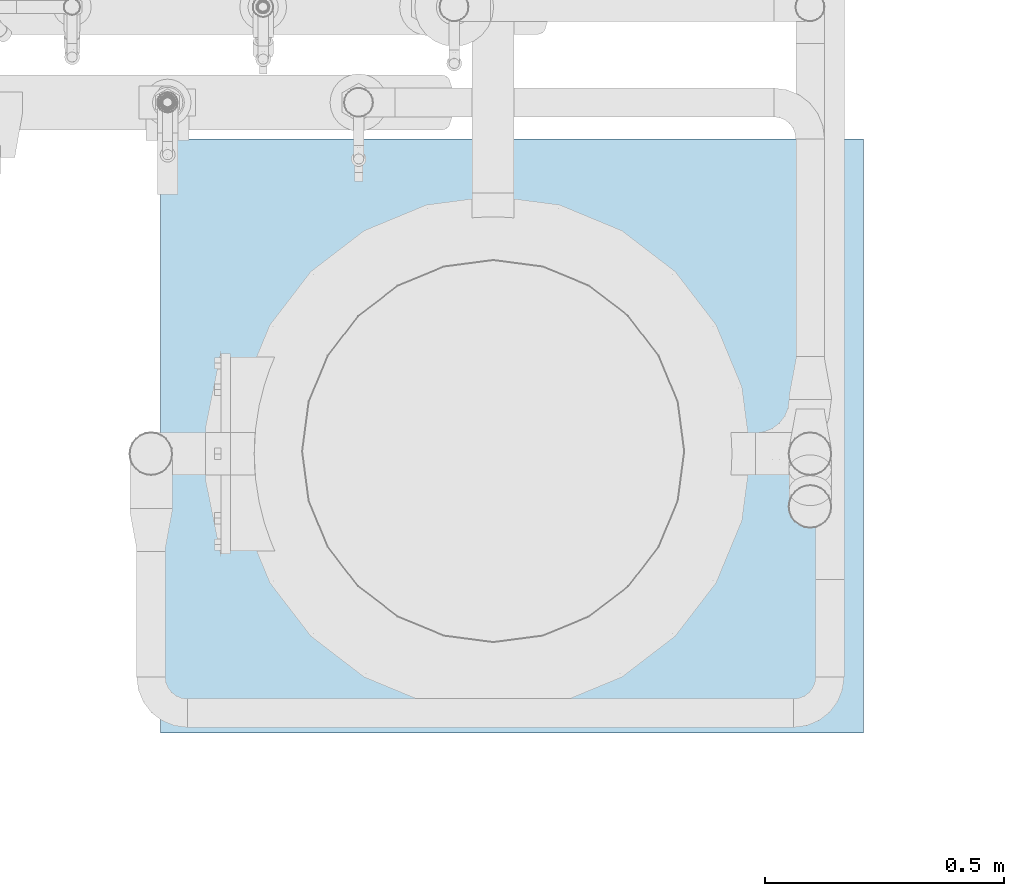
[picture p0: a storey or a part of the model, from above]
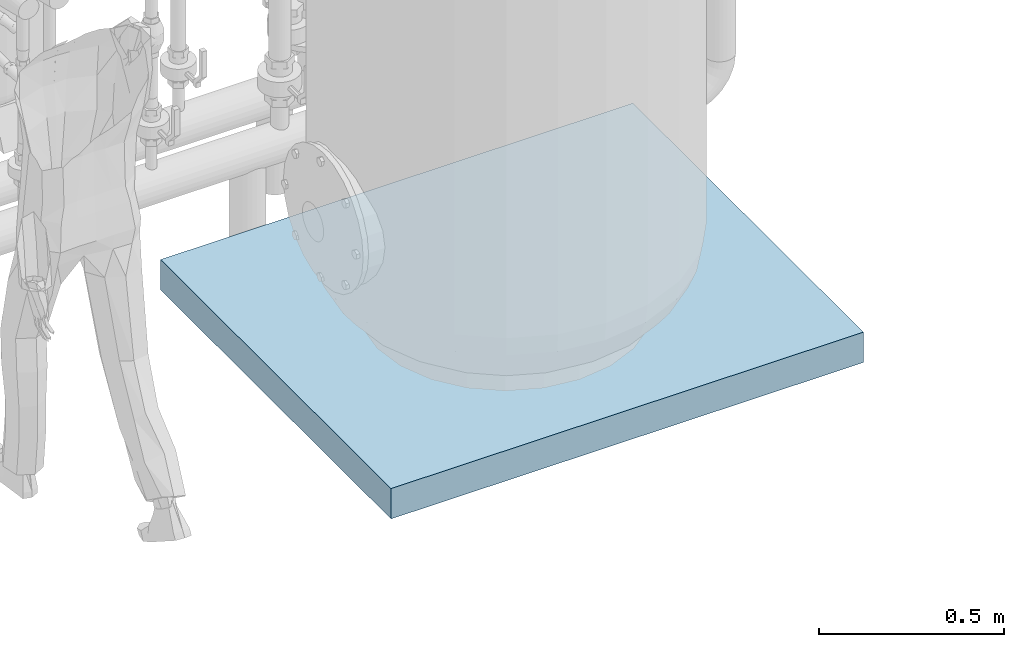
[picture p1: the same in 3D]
Properties of the parts of a building model (IFC2X3), part 4 of 4

# IfcFlowSegment: Tube acier d'après DIN 2448 (185)
Name | Geom-Ø exterieur (m) (m) | Geom-DN | Geom-Longueur (m) (m) | Tech-Material | Tech-Epaisseur isolant (m) (m) | Group
Tube acier d'après DIN 2448 | 0.0424 | 32 | 2.86799 | Tube acier d'après DIN 2448 | 0 | Eau froide
Tube acier d'après DIN 2448 | 0.0424 | 32 | 2.04472 | Tube acier d'après DIN 2448 | 0 | Eau froide
Tube acier d'après DIN 2448 | 0.0424 | 32 | 0.0559995 | Tube acier d'après DIN 2448 | 0 | Eau froide
Tube acier d'après DIN 2448 | 0.0424 | 32 | 0.314821 | Tube acier d'après DIN 2448 | 0 | Eau froide
Tube acier d'après DIN 2448 | 0.0424 | 32 | 0.367073 | Tube acier d'après DIN 2448 | 0 | Eau froide
Tube acier d'après DIN 2448 | 0.0424 | 32 | 6.64563 | Tube acier d'après DIN 2448 | 0 | Eau froide
Tube acier d'après DIN 2448 | 0.0424 | 32 | 3.83068 | Tube acier d'après DIN 2448 | 0 | Eau froide
Tube acier d'après DIN 2448 | 0.0424 | 32 | 1.23561 | Tube acier d'après DIN 2448 | 0 | Eau froide
Tube acier d'après DIN 2448 | 0.0337 | 25 | 0.249264 | Tube acier d'après DIN 2448 | 0 | Eau froide
Tube acier d'après DIN 2448 | 0.0337 | 25 | 2.87799 | Tube acier d'après DIN 2448 | 0 | Eau froide
Tube acier d'après DIN 2448 | 0.0337 | 25 | 0.014226 | Tube acier d'après DIN 2448 | 0 | Eau froide
Tube acier d'après DIN 2448 | 0.0337 | 25 | 2.13004 | Tube acier d'après DIN 2448 | 0 | Eau froide
Tube acier d'après DIN 2448 | 0.0337 | 25 | 0.0449734 | Tube acier d'après DIN 2448 | 0 | Eau froide
Tube acier d'après DIN 2448 | 0.0337 | 25 | 0.484802 | Tube acier d'après DIN 2448 | 0 | Eau froide
Tube acier d'après DIN 2448 | 0.0337 | 25 | 0.380838 | Tube acier d'après DIN 2448 | 0 | Eau froide
Tube acier d'après DIN 2448 | 0.0337 | 25 | 6.59173 | Tube acier d'après DIN 2448 | 0 | Eau froide
Tube acier d'après DIN 2448 | 0.0337 | 25 | 3.89682 | Tube acier d'après DIN 2448 | 0 | Eau froide
Tube acier d'après DIN 2448 | 0.0889 | 80 | 0.052 | Tube acier d'après DIN 2448 | 0 | Medium
Tube acier d'après DIN 2448 | 0.0603 | 50 | 0.127694 | Tube acier d'après DIN 2448 | 0 | Retour
Tube acier d'après DIN 2448 | 0.0889 | 80 | 0.405683 | Tube acier d'après DIN 2448 | 0 | Retour
Tube acier d'après DIN 2448 | 0.0603 | 50 | 0.215857 | Tube acier d'après DIN 2448 | 0.02 | Retour
Tube acier d'après DIN 2448 | 0.0603 | 50 | 0.655722 | Tube acier d'après DIN 2448 | 0.02 | Retour
Tube acier d'après DIN 2448 | 0.0603 | 50 | 1.75317 | Tube acier d'après DIN 2448 | 0.02 | Retour
Tube acier d'après DIN 2448 | 0.0603 | 50 | 0.377445 | Tube acier d'après DIN 2448 | 0 | Retour
Tube acier d'après DIN 2448 | 0.0603 | 50 | 0.62444 | Tube acier d'après DIN 2448 | 0.02 | Retour
Tube acier d'après DIN 2448 | 0.0603 | 50 | 0.0582589 | Tube acier d'après DIN 2448 | 0.02 | Retour
Tube acier d'après DIN 2448 | 0.0603 | 50 | 0.0452941 | Tube acier d'après DIN 2448 | 0 | Retour
Tube acier d'après DIN 2448 | 0.0603 | 50 | 0.199173 | Tube acier d'après DIN 2448 | 0 | Retour
2 x Tube acier d'après DIN 2448 | 0.0213 | 15 | 0.170622 | Tube acier d'après DIN 2448 | 0 | Retour
Tube acier d'après DIN 2448 | 0.0213 | 15 | 0.047222 | Tube acier d'après DIN 2448 | 0 | Retour
Tube acier d'après DIN 2448 | 0.0213 | 15 | 0.479122 | Tube acier d'après DIN 2448 | 0 | Retour
Tube acier d'après DIN 2448 | 0.0269 | 20 | 1.3829 | Tube acier d'après DIN 2448 | 0 | Retour
Tube acier d'après DIN 2448 | 0.0269 | 20 | 1.6498 | Tube acier d'après DIN 2448 | 0 | Aller
3 x Tube acier d'après DIN 2448 | 0.0337 | 25 | 1.3829 | Tube acier d'après DIN 2448 | 0.02 | Retour
2 x Tube acier d'après DIN 2448 | 0.0337 | 25 | 1.6498 | Tube acier d'après DIN 2448 | 0.02 | Aller
Tube acier d'après DIN 2448 | 0.0269 | 20 | 1.6498 | Tube acier d'après DIN 2448 | 0.02 | Aller
Tube acier d'après DIN 2448 | 0.0483 | 40 | 1.4 | Tube acier d'après DIN 2448 | 0.02 | Retour
Tube acier d'après DIN 2448 | 0.0483 | 40 | 1.6498 | Tube acier d'après DIN 2448 | 0.02 | Aller
Tube acier d'après DIN 2448 | 0.0483 | 40 | 3.56885 | Tube acier d'après DIN 2448 | 0 | Eau chaude
Tube acier d'après DIN 2448 | 0.0337 | 25 | 0.810274 | Tube acier d'après DIN 2448 | 0 | Eau froide
Tube acier d'après DIN 2448 | 0.0337 | 25 | 0.412186 | Tube acier d'après DIN 2448 | 0 | Eau froide
Tube acier d'après DIN 2448 | 0.0337 | 25 | 0.576251 | Tube acier d'après DIN 2448 | 0 | Eau froide
Tube acier d'après DIN 2448 | 0.0424 | 32 | 0.717881 | Tube acier d'après DIN 2448 | 0 | Eau froide
2 x Tube acier d'après DIN 2448 | 0.0424 | 32 | 0.397081 | Tube acier d'après DIN 2448 | 0 | Eau froide
Tube acier d'après DIN 2448 | 0.0424 | 32 | 0.564921 | Tube acier d'après DIN 2448 | 0 | Eau froide
Tube acier d'après DIN 2448 | 0.0424 | 32 | 3.12372 | Tube acier d'après DIN 2448 | 0 | Eau froide
Tube acier d'après DIN 2448 | 0.0889 | 80 | 0.722805 | Tube acier d'après DIN 2448 | 0 | Medium
Tube acier d'après DIN 2448 | 0.0889 | 80 | 0.0615702 | Tube acier d'après DIN 2448 | 0 | Medium
Tube acier d'après DIN 2448 | 0.0889 | 80 | 0.218245 | Tube acier d'après DIN 2448 | 0 | Medium
Tube acier d'après DIN 2448 | 0.0603 | 50 | 0.566038 | Tube acier d'après DIN 2448 | 0 | Medium
Tube acier d'après DIN 2448 | 0.0889 | 80 | 0.268216 | Tube acier d'après DIN 2448 | 0 | Medium
Tube acier d'après DIN 2448 | 0.0603 | 50 | 1.30929 | Tube acier d'après DIN 2448 | 0 | Medium
Tube acier d'après DIN 2448 | 0.0603 | 50 | 1.1883 | Tube acier d'après DIN 2448 | 0 | Retour
Tube acier d'après DIN 2448 | 0.0603 | 50 | 0.148938 | Tube acier d'après DIN 2448 | 0 | Retour
Tube acier d'après DIN 2448 | 0.0603 | 50 | 0.262758 | Tube acier d'après DIN 2448 | 0 | Medium
Tube acier d'après DIN 2448 | 0.0761 | 65 | 0.117433 | Tube acier d'après DIN 2448 | 0 | Eau froide
Tube acier d'après DIN 2448 | 0.0761 | 65 | 1.31857 | Tube acier d'après DIN 2448 | 0 | Eau froide
Tube acier d'après DIN 2448 | 0.0761 | 65 | 0.156416 | Tube acier d'après DIN 2448 | 0 | Eau froide
Tube acier d'après DIN 2448 | 0.0761 | 65 | 1.95031 | Tube acier d'après DIN 2448 | 0 | Eau froide
Tube acier d'après DIN 2448 | 0.0761 | 65 | 1.19848 | Tube acier d'après DIN 2448 | 0 | Eau froide
Tube acier d'après DIN 2448 | 0.0761 | 65 | 0.3 | Tube acier d'après DIN 2448 | 0 | Eau froide
Tube acier d'après DIN 2448 | 0.0603 | 50 | 0.335833 | Tube acier d'après DIN 2448 | 0 | Medium
Tube acier d'après DIN 2448 | 0.0603 | 50 | 0.203529 | Tube acier d'après DIN 2448 | 0 | Medium
Tube acier d'après DIN 2448 | 0.0603 | 50 | 1.26926 | Tube acier d'après DIN 2448 | 0 | Medium
Tube acier d'après DIN 2448 | 0.0483 | 40 | 0.808074 | Tube acier d'après DIN 2448 | 0 | Aller
Tube acier d'après DIN 2448 | 0.0603 | 50 | 0.93023 | Tube acier d'après DIN 2448 | 0 | Retour
Tube acier d'après DIN 2448 | 0.0603 | 50 | 0.508183 | Tube acier d'après DIN 2448 | 0 | Retour
Tube acier d'après DIN 2448 | 0.0603 | 50 | 0.793269 | Tube acier d'après DIN 2448 | 0.02 | Aller
Tube acier d'après DIN 2448 | 0.0603 | 50 | 0.593269 | Tube acier d'après DIN 2448 | 0.02 | Retour
Tube acier d'après DIN 2448 | 0.0603 | 50 | 1.48149 | Tube acier d'après DIN 2448 | 0.02 | Retour
Tube acier d'après DIN 2448 | 0.0424 | 32 | 1.47627 | Tube acier d'après DIN 2448 | 0 | Eau froide
Tube acier d'après DIN 2448 | 0.0424 | 32 | 0.0800144 | Tube acier d'après DIN 2448 | 0 | Eau froide
Tube acier d'après DIN 2448 | 0.0424 | 32 | 0.732347 | Tube acier d'après DIN 2448 | 0 | Eau froide
Tube acier d'après DIN 2448 | 0.0424 | 32 | 2.20338 | Tube acier d'après DIN 2448 | 0 | Eau froide
Tube acier d'après DIN 2448 | 0.0424 | 32 | 0.124 | Tube acier d'après DIN 2448 | 0 | Eau froide
Tube acier d'après DIN 2448 | 0.0483 | 40 | 0.463265 | Tube acier d'après DIN 2448 | 0 | Eau chaude
Tube acier d'après DIN 2448 | 0.0337 | 25 | 0.481356 | Tube acier d'après DIN 2448 | 0 | Eau froide
Tube acier d'après DIN 2448 | 0.0337 | 25 | 4.60437 | Tube acier d'après DIN 2448 | 0 | Eau froide
Tube acier d'après DIN 2448 | 0.0337 | 25 | 0.0964854 | Tube acier d'après DIN 2448 | 0 | Eau froide
Tube acier d'après DIN 2448 | 0.0337 | 25 | 1.5437 | Tube acier d'après DIN 2448 | 0 | Eau froide
Tube acier d'après DIN 2448 | 0.0337 | 25 | 0.0223708 | Tube acier d'après DIN 2448 | 0 | Eau froide
Tube acier d'après DIN 2448 | 0.0337 | 25 | 0.88769 | Tube acier d'après DIN 2448 | 0 | Eau froide
Tube acier d'après DIN 2448 | 0.0337 | 25 | 0.107078 | Tube acier d'après DIN 2448 | 0 | Eau froide
Tube acier d'après DIN 2448 | 0.0603 | 50 | 0.167084 | Tube acier d'après DIN 2448 | 0.02 | Retour
Tube acier d'après DIN 2448 | 0.0603 | 50 | 0.149592 | Tube acier d'après DIN 2448 | 0.02 | Retour
Tube acier d'après DIN 2448 | 0.0424 | 32 | 0.135577 | Tube acier d'après DIN 2448 | 0 | Retour
Tube acier d'après DIN 2448 | 0.0424 | 32 | 0.0868806 | Tube acier d'après DIN 2448 | 0.02 | Retour
Tube acier d'après DIN 2448 | 0.0424 | 32 | 1.12254 | Tube acier d'après DIN 2448 | 0.02 | Retour
Tube acier d'après DIN 2448 | 0.0424 | 32 | 0.247877 | Tube acier d'après DIN 2448 | 0.02 | Retour

# IfcFlowSegment: Tube coudé (95)
In: Rez de chaussŽe
Description: Tube coudé
Pset Plancal nova - MEP - Nom: Tube coudé; Tech-Material: Selon DIN 2605
Name | Geom-Ø ext 1 (m) (m) = Geom-Ø ext 2 (m) (m) | Geom-DN1 = Geom-DN2 | Tech-Epaisseur isolant (m) (m) | Geom-Angle (°) (rad) | Group
2 x Tube coudé | 0.0603 | 50 | 0.02 | 90 | Aller
3 x Tube coudé | 0.0269 | 20 | 0.02 | 90 | Retour
Tube coudé | 0.0269 | 20 | 0.02 | 90 | Aller
6 x Tube coudé | 0.0213 | 15 | 0.02 | 90 | Aller
6 x Tube coudé | 0.0213 | 15 | 0.02 | 90 | Retour
4 x Tube coudé | 0.0424 | 32 | 0.02 | 90 | Retour
Tube coudé | 0.0424 | 32 | 0 | 90 | Aller
2 x Tube coudé | 0.0424 | 32 | 0 | 90 | Retour
2 x Tube coudé | 0.0603 | 50 | 0 | 45 | Medium
6 x Tube coudé | 0.0603 | 50 | 0 | 90 | Retour
Tube coudé | 0.0483 | 40 | 0 | 90 | Aller
2 x Tube coudé | 0.0337 | 25 | 0 | 90 | Aller
4 x Tube coudé | 0.0889 | 80 | 0 | 90 | Medium
7 x Tube coudé | 0.0603 | 50 | 0.02 | 90 | Retour
Tube coudé | 0.0483 | 40 | 0 | 90 | Eau chaude
2 x Tube coudé | 0.0483 | 40 | 0 | 45 | Eau chaude
15 x Tube coudé | 0.0424 | 32 | 0 | 90 | Eau froide
Tube coudé | 0.0424 | 32 | 0 | 8 | Eau froide
12 x Tube coudé | 0.0337 | 25 | 0 | 90 | Eau froide
Tube coudé | 0.0337 | 25 | 0 | 8 | Eau froide
Tube coudé | 0.0889 | 80 | 0 | 90 | Retour
2 x Tube coudé | 0.0213 | 15 | 0 | 90 | Retour
2 x Tube coudé | 0.0889 | 80 | 0 | 45 | Medium
2 x Tube coudé | 0.0603 | 50 | 0 | 90 | Medium
5 x Tube coudé | 0.0761 | 65 | 0 | 90 | Eau froide
2 x Tube coudé | 0.0424 | 32 | 0 | 45 | Eau froide
2 x Tube coudé | 0.0337 | 25 | 0 | 45 | Eau froide

# IfcFlowSegment: Tube flexible (200)
Pset Plancal nova - MEP - Nom: Tube flexible; Tech-Epaisseur isolant (m): 0 m
Name | In | Description | Geom-Ø principal (m) (m) | Calc-Perte de charge (Pa) (Pa) | Geom-Longueur (m) (m) | Tech-Fluide | Calc-Debit vol (m3/s) (m3/s) | Calc-Vitesse (m/s) (m/s) | Group
Tube flexible | R+2 | Tube flexible | 0.16 | 1.11982 | 0.802072 | V_Air_extrait | 0.0555556 | 2.76311 | Air extrait
Tube flexible | R+2 | Tube flexible | 0.16 | 1.14687 | 0.821449 | V_Air_extrait | 0.0555556 | 2.76311 | Air extrait
16 x Tube flexible | R+2 | Tube flexible | 0.16 | 1.11677 | 0.799891 | V_Air_extrait | 0.0555556 | 2.76311 | Air extrait
Tube flexible | R+2 | Tube flexible | 0.16 | 1.11677 | 0.556161 | V_Air_extrait | 0.0555556 | 2.76311 | Air extrait
Tube flexible | R+2 | Tube flexible | 0.16 | 1.1716 | 0.839166 | V_Air_extrait | 0.0555556 | 2.76311 | Air extrait
Tube flexible | R+2 | Tube flexible | 0.16 | 1.19918 | 0.858915 | V_Air_extrait | 0.0555556 | 2.76311 | Air extrait
2 x Tube flexible | R+2 | Tube flexible | 0.16 | 1.22684 | 0.878732 | V_Air_extrait | 0.0555556 | 2.76311 | Air extrait
Tube flexible | R+2 | Tube flexible | 0.16 | 1.23031 | 0.881213 | V_Air_extrait | 0.0555556 | 2.76311 | Air extrait
Tube flexible | R+2 | Tube flexible | 0.16 | 1.11677 | 1.2922 | V_Air_extrait | 0.0555556 | 2.76311 | Air extrait
3 x Tube flexible | R+2 | Tube flexible | 0.16 | 1.22671 | 0.878639 | V_Air_extrait | 0.0555556 | 2.76311 | Air extrait
Tube flexible | R+2 | Tube flexible | 0.16 | 1.19905 | 0.858823 | V_Air_extrait | 0.0555556 | 2.76311 | Air extrait
Tube flexible | R+2 | Tube flexible | 0.16 | 1.11677 | 0.50558 | V_Air_extrait | 0.0555556 | 2.76311 | Air extrait
21 x Tube flexible | R+2 | Tube flexible | 0.16 | 1.11677 | 0.799891 | V_Air_soufflé | 0.0555556 | 2.76311 | Air soufflé
Tube flexible | R+2 | Tube flexible | 0.16 | 1.1716 | 1.3492 | V_Air_soufflé | 0.0555556 | 2.76311 | Air soufflé
Tube flexible | R+2 | Tube flexible | 0.16 | 1.22684 | 1.33733 | V_Air_soufflé | 0.0555556 | 2.76311 | Air soufflé
Tube flexible | R+2 | Tube flexible | 0.16 | 1.22684 | 1.34172 | V_Air_soufflé | 0.0555556 | 2.76311 | Air soufflé
Tube flexible | R+2 | Tube flexible | 0.16 | 1.19918 | 1.31992 | V_Air_soufflé | 0.0555556 | 2.76311 | Air soufflé
Tube flexible | R+2 | Flexrohr | 0.125 |  | 0.308295 | V_Air_extrait |  |  | Air extrait | Pset Plancal nova - MEP - Tech-Materiel (ID): 1
Tube flexible | R+2 | Flexrohr | 0.125 |  | 0.267271 | V_Air_extrait |  |  | Air extrait | Pset Plancal nova - MEP - Tech-Materiel (ID): 1
Tube flexible | R+2 | Flexrohr | 0.125 |  | 0.247359 | V_Air_extrait |  |  | Air extrait | Pset Plancal nova - MEP - Tech-Materiel (ID): 1
Tube flexible | Mezzannine | Tube flexible | 0.16 | 1.28172 | 0.918034 | V_Air_soufflé | 0.0555556 | 2.76311 | Air soufflé
11 x Tube flexible | Mezzannine | Tube flexible | 0.16 | 1.24847 | 0.894224 | V_Air_soufflé | 0.0555556 | 2.76311 | Air soufflé
Tube flexible | Mezzannine | Tube flexible | 0.16 | 1.27025 | 0.909824 | V_Air_soufflé | 0.0555556 | 2.76311 | Air soufflé
Tube flexible | Mezzannine | Tube flexible | 0.16 | 1.3066 | 0.935861 | V_Air_soufflé | 0.0555556 | 2.76311 | Air soufflé
17 x Tube flexible | Mezzannine | Tube flexible | 0.16 | 1.24847 | 0.894224 | V_Air_extrait | 0.0555556 | 2.76311 | Air extrait
3 x Tube flexible | Mezzannine | Tube flexible | 0.16 | 1.012 | 0.724847 | V_Air_extrait | 0.0555556 | 2.76311 | Air extrait
3 x Tube flexible | Mezzannine | Tube flexible | 0.16 | 1.08395 | 0.776384 | V_Air_extrait | 0.0555556 | 2.76311 | Air extrait
3 x Tube flexible | Mezzannine | Tube flexible | 0.16 | 1.14171 | 0.817752 | V_Air_extrait | 0.0555556 | 2.76311 | Air extrait
2 x Tube flexible | Mezzannine | Tube flexible | 0.16 | 1.19235 | 0.854025 | V_Air_extrait | 0.0555556 | 2.76311 | Air extrait
Tube flexible | Mezzannine | Tube flexible | 0.16 | 1.25762 | 0.900773 | V_Air_extrait | 0.0555556 | 2.76311 | Air extrait
Tube flexible | Mezzannine | Tube flexible | 0.16 | 1.22859 | 0.879983 | V_Air_extrait | 0.0555556 | 2.76311 | Air extrait
Tube flexible | Mezzannine | Tube flexible | 0.16 | 1.11281 | 0.797054 | V_Air_extrait | 0.0555556 | 2.76311 | Air extrait
2 x Tube flexible | Mezzannine | Tube flexible | 0.16 | 1.04794 | 0.75059 | V_Air_extrait | 0.0555556 | 2.76311 | Air extrait
Tube flexible | Mezzannine | Tube flexible | 0.16 | 1.15885 | 0.830032 | V_Air_extrait | 0.0555556 | 2.76311 | Air extrait
Tube flexible | Mezzannine | Tube flexible | 0.16 | 1.24847 | 0.424837 | V_Air_soufflé | 0.0555556 | 2.76311 | Air soufflé
Tube flexible | Mezzannine | Tube flexible | 0.125 |  | 0.26127 | V_Air_extrait |  |  | Air extrait
Tube flexible | Mezzannine | Tube flexible | 0.125 |  | 0.332574 | V_Air_extrait |  |  | Air extrait
Tube flexible | Mezzannine | Tube flexible | 0.125 |  | 0.437514 | V_Air_extrait |  |  | Air extrait
9 x Tube flexible | R+1 | Tube flexible | 0.16 | 1.24847 | 0.894224 | V_Air_extrait | 0.0555556 | 2.76311 | Air extrait
Tube flexible | R+1 | Tube flexible | 0.16 | 1.22859 | 0.879983 | V_Air_extrait | 0.0555556 | 2.76311 | Air extrait
Tube flexible | R+1 | Tube flexible | 0.16 | 1.21409 | 0.869596 | V_Air_extrait | 0.0555556 | 2.76311 | Air extrait
Tube flexible | R+1 | Tube flexible | 0.16 | 1.28677 | 0.921657 | V_Air_extrait | 0.0555556 | 2.76311 | Air extrait
Tube flexible | R+1 | Tube flexible | 0.16 | 0.810417 | 0.580465 | V_Air_extrait | 0.0555556 | 2.76311 | Air extrait
Tube flexible | R+1 | Tube flexible | 0.16 | 1.71307 | 1.20874 | V_Air_extrait | 0.0555556 | 2.76311 | Air extrait
Tube flexible | R+1 | Tube flexible | 0.16 | 1.27169 | 0.91085 | V_Air_extrait | 0.0555556 | 2.76311 | Air extrait
5 x Tube flexible | R+1 | Tube flexible | 0.16 | 1.24847 | 0.894224 | V_Air_soufflé | 0.0555556 | 2.76311 | Air soufflé
4 x Tube flexible | R+1 | Tube flexible | 0.16 | 0.856653 | 0.613581 | V_Air_soufflé | 0.0555556 | 2.76311 | Air soufflé
Tube flexible | R+1 | Tube flexible | 0.16 | 0.856653 | 0.701376 | V_Air_soufflé | 0.0555556 | 2.76311 | Air soufflé
2 x Tube flexible | R+1 | Tube flexible | 0.16 | 1.28145 | 0.917841 | V_Air_soufflé | 0.0555556 | 2.76311 | Air soufflé
Tube flexible | R+1 | Tube flexible | 0.16 | 1.45 | 1.03857 | V_Air_soufflé | 0.0555556 | 2.76311 | Air soufflé
Tube flexible | R+1 | Tube flexible | 0.16 | 0.58779 | 0.421007 | V_Air_soufflé | 0.0555556 | 2.76311 | Air soufflé
2 x Tube flexible | R+1 | Tube flexible | 0.16 | 1.19076 | 0.852888 | V_Air_soufflé | 0.0555556 | 2.76311 | Air soufflé
Tube flexible | R+1 | Tube flexible | 0.125 | 2.71369 | 0.416547 | V_Air_extrait | 0.0555556 | 4.52707 | Air extrait | Pset Plancal nova - MEP - Abbreviation: TF
Tube flexible | R+1 | Tube flexible | 0.16 | 1.24847 | 0.794435 | V_Air_extrait | 0.0555556 | 2.76311 | Air extrait
Tube flexible | R+1 | Tube flexible | 0.16 | 1.24847 | 0.833755 | V_Air_extrait | 0.0555556 | 2.76311 | Air extrait
Tube flexible | R+1 | Tube flexible | 0.125 |  | 0.295694 | V_Air_extrait |  |  | Air extrait
Tube flexible | R+1 | Tube flexible | 0.125 |  | 0.301994 | V_Air_extrait |  |  | Air extrait
18 x Tube flexible | Rez de chaussŽe | Tube flexible | 0.16 | 1.22078 | 0.874389 | V_Air_soufflé | 0.0555556 | 2.76311 | Air soufflé
2 x Tube flexible | Rez de chaussŽe | Tube flexible | 0.125 | 5.79395 | 1.12867 | V_Air_extrait | 0.0555556 | 4.52707 | Air extrait
30 x Tube flexible | Rez de chaussŽe | Tube flexible | 0.16 | 1.22078 | 0.874389 | V_Air_extrait | 0.0555556 | 2.76311 | Air extrait
Tube flexible | Rez de chaussŽe | Tube flexible | 0.16 | 1.22078 | 0.938879 | V_Air_extrait | 0.0555556 | 2.76311 | Air extrait
Tube flexible | Rez de chaussŽe | Tube flexible | 0.16 | 1.22078 | 0.904197 | V_Air_extrait | 0.0555556 | 2.76311 | Air extrait
Tube flexible | Rez de chaussŽe | Tube flexible | 0.125 |  | 1.1959 | V_Air_extrait |  |  | Air extrait
Tube flexible | Rez de chaussŽe | Tube flexible | 0.16 |  | 0.942181 | V_Air_soufflé |  |  | Air soufflé

# IfcFlowStorageDevice: Bouteille casse pression
In: Rez de chaussŽe
Description: Bouteille casse pression; Group: Aller
Pset Plancal nova - MEP - Nom: Bouteille casse pression; Geom-Ø (m): 0.5 m; Geom-Longueur (m): 1.57 m; Tech-Epaisseur isolant (m): 0 m

# IfcFlowStorageDevice: Réservoir
In: Rez de chaussŽe
Description: Réservoir; Group: Medium
Pset Plancal nova - MEP - Nom: Réservoir; Geom-Ø (m): 1 m; Tech-Type d'isolant: Laine minérale laminée Alu avec tôle; Geom-Longueur (m): 2 m; Tech-Epaisseur isolant (m): 0.04 m

# IfcFlowTerminal: Air diffuseur - bouche (200)
Description: Air diffuseur - bouche; Group: Terminal
Pset Plancal nova - MEP - Nom: Air diffuseur - bouche; Calc-Perte de charge (Pa): 30 Pa; Geom-Panel côte 2 (m): 0.25 m; Calc-Debit vol (m3/s): 0.0555556 m3/s
Name | In | Geom-côte 1 (m) (m) | Geom-Ø raccordement (m) (m) | Calc-Valeur d'equilibrage (Pa) (Pa) | Tech-Fluide
Air diffuseur - bouche | R+2 | 0.3 | 0.16 | 143.975 | V_Air_extrait
Air diffuseur - bouche | R+2 | 0.3 | 0.16 | 141.277 | V_Air_extrait
Air diffuseur - bouche | R+2 | 0.3 | 0.16 | 141.079 | V_Air_extrait
Air diffuseur - bouche | R+2 | 0.3 | 0.16 | 140.98 | V_Air_extrait
Air diffuseur - bouche | R+2 | 0.2 | 0.125 | 114.03 | V_Air_extrait
Air diffuseur - bouche | R+2 | 0.2 | 0.125 | 112.623 | V_Air_extrait
Air diffuseur - bouche | R+2 | 0.2 | 0.125 | 116.625 | V_Air_extrait
Air diffuseur - bouche | R+2 | 0.3 | 0.16 | 138.641 | V_Air_extrait
Air diffuseur - bouche | R+2 | 0.3 | 0.16 | 134.978 | V_Air_extrait
Air diffuseur - bouche | R+2 | 0.3 | 0.16 | 120.07 | V_Air_extrait
Air diffuseur - bouche | R+2 | 0.3 | 0.16 | 115.612 | V_Air_extrait
Air diffuseur - bouche | R+2 | 0.3 | 0.16 | 111.883 | V_Air_extrait
Air diffuseur - bouche | R+2 | 0.3 | 0.16 | 97.7143 | V_Air_extrait
Air diffuseur - bouche | R+2 | 0.3 | 0.16 | 90.7285 | V_Air_extrait
Air diffuseur - bouche | R+2 | 0.3 | 0.16 | 87.5459 | V_Air_extrait
Air diffuseur - bouche | R+2 | 0.3 | 0.16 | 80.7047 | V_Air_extrait
Air diffuseur - bouche | R+2 | 0.3 | 0.16 | 81.2122 | V_Air_extrait
Air diffuseur - bouche | R+2 | 0.3 | 0.16 | 105.889 | V_Air_extrait
Air diffuseur - bouche | R+2 | 0.3 | 0.16 | 84.0622 | V_Air_extrait
Air diffuseur - bouche | R+2 | 0.3 | 0.16 | 79.5223 | V_Air_extrait
Air diffuseur - bouche | R+2 | 0.3 | 0.16 | 76.1591 | V_Air_extrait
Air diffuseur - bouche | R+2 | 0.3 | 0.16 | 70.4071 | V_Air_extrait
Air diffuseur - bouche | R+2 | 0.3 | 0.16 | 64.66 | V_Air_extrait
Air diffuseur - bouche | R+2 | 0.3 | 0.16 | 27.9193 | V_Air_extrait
Air diffuseur - bouche | R+2 | 0.3 | 0.16 | 21.4202 | V_Air_extrait
Air diffuseur - bouche | R+2 | 0.3 | 0.16 | 15.5862 | V_Air_extrait
Air diffuseur - bouche | R+2 | 0.3 | 0.16 | 0 | V_Air_extrait
Air diffuseur - bouche | R+2 | 0.3 | 0.16 | 0.507466 | V_Air_extrait
Air diffuseur - bouche | R+2 | 0.3 | 0.16 | 6.84117 | V_Air_extrait
Air diffuseur - bouche | R+2 | 0.3 | 0.16 | 36.0938 | V_Air_extrait
Air diffuseur - bouche | R+2 | 0.3 | 0.16 | 42.0875 | V_Air_extrait
Air diffuseur - bouche | R+2 | 0.3 | 0.16 | 88.944 | V_Air_extrait
Air diffuseur - bouche | R+2 | 0.3 | 0.16 | 72.3225 | V_Air_soufflé
Air diffuseur - bouche | R+2 | 0.3 | 0.16 | 72.3185 | V_Air_soufflé
Air diffuseur - bouche | R+2 | 0.3 | 0.16 | 67.4568 | V_Air_soufflé
Air diffuseur - bouche | R+2 | 0.3 | 0.16 | 67.4608 | V_Air_soufflé
Air diffuseur - bouche | R+2 | 0.3 | 0.16 | 70.9124 | V_Air_soufflé
Air diffuseur - bouche | R+2 | 0.3 | 0.16 | 70.9164 | V_Air_soufflé
Air diffuseur - bouche | R+2 | 0.3 | 0.16 | 62.4944 | V_Air_soufflé
Air diffuseur - bouche | R+2 | 0.3 | 0.16 | 62.4984 | V_Air_soufflé
Air diffuseur - bouche | R+2 | 0.3 | 0.16 | 67.9789 | V_Air_soufflé
Air diffuseur - bouche | R+2 | 0.3 | 0.16 | 67.9749 | V_Air_soufflé
Air diffuseur - bouche | R+2 | 0.3 | 0.16 | 61.3973 | V_Air_soufflé
Air diffuseur - bouche | R+2 | 0.3 | 0.16 | 61.4014 | V_Air_soufflé
Air diffuseur - bouche | R+2 | 0.3 | 0.16 | 88.4751 | V_Air_soufflé
Air diffuseur - bouche | R+2 | 0.3 | 0.16 | 80.6627 | V_Air_soufflé
Air diffuseur - bouche | R+2 | 0.3 | 0.16 | 72.6408 | V_Air_soufflé
Air diffuseur - bouche | R+2 | 0.3 | 0.16 | 57.9598 | V_Air_soufflé
Air diffuseur - bouche | R+2 | 0.3 | 0.16 | 56.9724 | V_Air_soufflé
Air diffuseur - bouche | R+2 | 0.3 | 0.16 | 39.9944 | V_Air_soufflé
Air diffuseur - bouche | R+2 | 0.3 | 0.16 | 35.1176 | V_Air_soufflé
Air diffuseur - bouche | R+2 | 0.3 | 0.16 | 37.8314 | V_Air_soufflé
Air diffuseur - bouche | R+2 | 0.3 | 0.16 | 42.938 | V_Air_soufflé
Air diffuseur - bouche | R+2 | 0.3 | 0.16 | 50.1573 | V_Air_soufflé
Air diffuseur - bouche | R+2 | 0.3 | 0.16 | 66.1973 | V_Air_soufflé
Air diffuseur - bouche | R+2 | 0.3 | 0.16 | 72.0742 | V_Air_soufflé
Air diffuseur - bouche | R+2 | 0.3 | 0.16 | 73.2806 | V_Air_soufflé
Air diffuseur - bouche | R+2 | 0.3 | 0.16 | 77.5209 | V_Air_extrait
Air diffuseur - bouche | Mezzannine | 0.3 | 0.16 | 71.0162 | V_Air_soufflé
Air diffuseur - bouche | Mezzannine | 0.3 | 0.16 | 60.5208 | V_Air_soufflé
Air diffuseur - bouche | Mezzannine | 0.3 | 0.16 | 60.5852 | V_Air_soufflé
Air diffuseur - bouche | Mezzannine | 0.3 | 0.16 | 53.2318 | V_Air_soufflé
Air diffuseur - bouche | Mezzannine | 0.3 | 0.16 | 53.2962 | V_Air_soufflé
Air diffuseur - bouche | Mezzannine | 0.3 | 0.16 | 63.8921 | V_Air_soufflé
Air diffuseur - bouche | Mezzannine | 0.3 | 0.16 | 63.9565 | V_Air_soufflé
Air diffuseur - bouche | Mezzannine | 0.3 | 0.16 | 22.2971 | V_Air_soufflé
Air diffuseur - bouche | Mezzannine | 0.3 | 0.16 | 24.029 | V_Air_soufflé
Air diffuseur - bouche | Mezzannine | 0.3 | 0.16 | 1.60196 | V_Air_soufflé
Air diffuseur - bouche | Mezzannine | 0.3 | 0.16 | 0 | V_Air_soufflé
Air diffuseur - bouche | Mezzannine | 0.3 | 0.16 | 32.7706 | V_Air_soufflé
Air diffuseur - bouche | Mezzannine | 0.3 | 0.16 | 33.168 | V_Air_soufflé
Air diffuseur - bouche | Mezzannine | 0.3 | 0.16 | 34.1554 | V_Air_soufflé
Air diffuseur - bouche | Mezzannine | 0.3 | 0.16 | 66.9789 | V_Air_soufflé
Air diffuseur - bouche | Mezzannine | 0.3 | 0.16 | 94.5131 | V_Air_extrait
Air diffuseur - bouche | Mezzannine | 0.3 | 0.16 | 84.1428 | V_Air_extrait
Air diffuseur - bouche | Mezzannine | 0.3 | 0.16 | 76.1717 | V_Air_extrait
Air diffuseur - bouche | Mezzannine | 0.3 | 0.16 | 62.471 | V_Air_extrait
Air diffuseur - bouche | Mezzannine | 0.3 | 0.16 | 51.4216 | V_Air_extrait
Air diffuseur - bouche | Mezzannine | 0.3 | 0.16 | 41.6955 | V_Air_extrait
Air diffuseur - bouche | Mezzannine | 0.3 | 0.16 | 27.0219 | V_Air_extrait
Air diffuseur - bouche | Mezzannine | 0.3 | 0.16 | 21.1127 | V_Air_extrait
Air diffuseur - bouche | Mezzannine | 0.3 | 0.16 | 0 | V_Air_extrait
Air diffuseur - bouche | Mezzannine | 0.3 | 0.16 | 6.01624 | V_Air_extrait
Air diffuseur - bouche | Mezzannine | 0.3 | 0.16 | 12.3676 | V_Air_extrait
Air diffuseur - bouche | Mezzannine | 0.3 | 0.16 | 33.521 | V_Air_extrait
Air diffuseur - bouche | Mezzannine | 0.3 | 0.16 | 47.6905 | V_Air_extrait
Air diffuseur - bouche | Mezzannine | 0.3 | 0.16 | 56.719 | V_Air_extrait
Air diffuseur - bouche | Mezzannine | 0.3 | 0.16 | 68.5029 | V_Air_extrait
Air diffuseur - bouche | Mezzannine | 0.3 | 0.16 | 73.3847 | V_Air_extrait
Air diffuseur - bouche | Mezzannine | 0.3 | 0.16 | 80.0361 | V_Air_extrait
Air diffuseur - bouche | Mezzannine | 0.2 | 0.125 | 124.562 | V_Air_extrait
Air diffuseur - bouche | Mezzannine | 0.2 | 0.125 | 127.615 | V_Air_extrait
Air diffuseur - bouche | Mezzannine | 0.2 | 0.125 | 0 | V_Air_extrait
Air diffuseur - bouche | Mezzannine | 0.3 | 0.16 | 107.34 | V_Air_extrait
Air diffuseur - bouche | Mezzannine | 0.3 | 0.16 | 99.1261 | V_Air_extrait
Air diffuseur - bouche | Mezzannine | 0.3 | 0.16 | 93.8287 | V_Air_extrait
Air diffuseur - bouche | Mezzannine | 0.3 | 0.16 | 88.6685 | V_Air_extrait
Air diffuseur - bouche | Mezzannine | 0.3 | 0.16 | 64.4366 | V_Air_extrait
Air diffuseur - bouche | Mezzannine | 0.3 | 0.16 | 43.3078 | V_Air_extrait
Air diffuseur - bouche | Mezzannine | 0.3 | 0.16 | 31.5565 | V_Air_extrait
Air diffuseur - bouche | Mezzannine | 0.3 | 0.16 | 36.9741 | V_Air_extrait
Air diffuseur - bouche | Mezzannine | 0.3 | 0.16 | 52.0529 | V_Air_extrait
Air diffuseur - bouche | Mezzannine | 0.3 | 0.16 | 57.9375 | V_Air_extrait
Air diffuseur - bouche | Mezzannine | 0.3 | 0.16 | 72.611 | V_Air_extrait
Air diffuseur - bouche | Mezzannine | 0.3 | 0.16 | 104.392 | V_Air_extrait
Air diffuseur - bouche | Mezzannine | 0.3 | 0.16 | 111.474 | V_Air_extrait
Air diffuseur - bouche | Mezzannine | 0.3 | 0.16 | 119.102 | V_Air_extrait
Air diffuseur - bouche | Mezzannine | 0.3 | 0.16 | 109.066 | V_Air_extrait
Air diffuseur - bouche | Mezzannine | 0.3 | 0.16 | 116.432 | V_Air_extrait
Air diffuseur - bouche | Mezzannine | 0.3 | 0.16 | 52.7834 | V_Air_extrait
Air diffuseur - bouche | R+1 | 0.3 | 0.16 | 6.14642 | V_Air_extrait
Air diffuseur - bouche | R+1 | 0.3 | 0.16 | 0.500388 | V_Air_extrait
3 x Air diffuseur - bouche | R+1 | 0.3 | 0.16 | 0 | V_Air_extrait
Air diffuseur - bouche | R+1 | 0.2 | 0.125 | 4.51898 | V_Air_extrait
Air diffuseur - bouche | R+1 | 0.2 | 0.125 | 0 | V_Air_extrait
Air diffuseur - bouche | R+1 | 0.2 | 0.125 | 8.58369 | V_Air_extrait
Air diffuseur - bouche | R+1 | 0.3 | 0.16 | 112.066 | V_Air_extrait
Air diffuseur - bouche | R+1 | 0.3 | 0.16 | 108.921 | V_Air_extrait
Air diffuseur - bouche | R+1 | 0.3 | 0.16 | 13.9916 | V_Air_extrait
Air diffuseur - bouche | R+1 | 0.3 | 0.16 | 94.7655 | V_Air_extrait
Air diffuseur - bouche | R+1 | 0.3 | 0.16 | 102.94 | V_Air_extrait
Air diffuseur - bouche | R+1 | 0.3 | 0.16 | 114.966 | V_Air_extrait
Air diffuseur - bouche | R+1 | 0.3 | 0.16 | 123.407 | V_Air_extrait
Air diffuseur - bouche | R+1 | 0.3 | 0.16 | 141.267 | V_Air_extrait
Air diffuseur - bouche | R+1 | 0.3 | 0.16 | 1.32604 | V_Air_extrait
2 x Air diffuseur - bouche | R+1 | 0.3 | 0.16 | 0 | V_Air_soufflé
Air diffuseur - bouche | R+1 | 0.3 | 0.16 | 21.2424 | V_Air_soufflé
Air diffuseur - bouche | R+1 | 0.3 | 0.16 | 22.8162 | V_Air_soufflé
Air diffuseur - bouche | R+1 | 0.3 | 0.16 | 17.4058 | V_Air_soufflé
Air diffuseur - bouche | R+1 | 0.3 | 0.16 | 19.222 | V_Air_soufflé
Air diffuseur - bouche | R+1 | 0.3 | 0.16 | 19.5131 | V_Air_soufflé
Air diffuseur - bouche | R+1 | 0.3 | 0.16 | 4.85543 | V_Air_soufflé
Air diffuseur - bouche | R+1 | 0.3 | 0.16 | 66.8407 | V_Air_soufflé
Air diffuseur - bouche | R+1 | 0.3 | 0.16 | 59.0008 | V_Air_soufflé
Air diffuseur - bouche | R+1 | 0.3 | 0.16 | 57.8154 | V_Air_soufflé
Air diffuseur - bouche | R+1 | 0.3 | 0.16 | 59.6316 | V_Air_soufflé
3 x Air diffuseur - bouche | R+1 | 0.3 | 0.16 | 33.6314 | V_Air_soufflé
Air diffuseur - bouche | R+1 | 0.3 | 0.16 | 35.5727 | V_Air_soufflé
Air diffuseur - bouche | R+1 | 0.3 | 0.16 | 27.2959 | V_Air_soufflé
Air diffuseur - bouche | R+1 | 0.3 | 0.16 | 29.3846 | V_Air_soufflé
Air diffuseur - bouche | R+1 | 0.3 | 0.16 | 99.1116 | V_Air_extrait
Air diffuseur - bouche | Rez de chaussŽe | 0.3 | 0.16 | 39.7325 | V_Air_soufflé
Air diffuseur - bouche | Rez de chaussŽe | 0.3 | 0.16 | 31.5078 | V_Air_soufflé
Air diffuseur - bouche | Rez de chaussŽe | 0.3 | 0.16 | 30.5205 | V_Air_soufflé
Air diffuseur - bouche | Rez de chaussŽe | 0.3 | 0.16 | 30.1231 | V_Air_soufflé
Air diffuseur - bouche | Rez de chaussŽe | 0.3 | 0.16 | 33.048 | V_Air_soufflé
Air diffuseur - bouche | Rez de chaussŽe | 0.3 | 0.16 | 5.54298 | V_Air_soufflé
Air diffuseur - bouche | Rez de chaussŽe | 0.3 | 0.16 | 4.08531 | V_Air_soufflé
3 x Air diffuseur - bouche | Rez de chaussŽe | 0.3 | 0.16 | 0 | V_Air_soufflé
Air diffuseur - bouche | Rez de chaussŽe | 0.3 | 0.16 | 36.2321 | V_Air_soufflé
Air diffuseur - bouche | Rez de chaussŽe | 0.3 | 0.16 | 35.2447 | V_Air_soufflé
Air diffuseur - bouche | Rez de chaussŽe | 0.3 | 0.16 | 24.3738 | V_Air_soufflé
Air diffuseur - bouche | Rez de chaussŽe | 0.3 | 0.16 | 19.4152 | V_Air_soufflé
Air diffuseur - bouche | Rez de chaussŽe | 0.3 | 0.16 | 23.4959 | V_Air_soufflé
Air diffuseur - bouche | Rez de chaussŽe | 0.3 | 0.16 | 24.9581 | V_Air_soufflé
Air diffuseur - bouche | Rez de chaussŽe | 0.3 | 0.16 | 34.8473 | V_Air_soufflé
Air diffuseur - bouche | Rez de chaussŽe | 0.3 | 0.16 | 46.6831 | V_Air_soufflé
Air diffuseur - bouche | Rez de chaussŽe | 0.3 | 0.16 | 51.5837 | V_Air_soufflé
Air diffuseur - bouche | Rez de chaussŽe | 0.2 | 0.125 | 1.00507 | V_Air_extrait
Air diffuseur - bouche | Rez de chaussŽe | 0.2 | 0.125 | 1.73459 | V_Air_extrait
Air diffuseur - bouche | Rez de chaussŽe | 0.2 | 0.125 | 0 | V_Air_extrait
Air diffuseur - bouche | Rez de chaussŽe | 0.3 | 0.16 | 38.3897 | V_Air_extrait
Air diffuseur - bouche | Rez de chaussŽe | 0.3 | 0.16 | 27.8646 | V_Air_extrait
Air diffuseur - bouche | Rez de chaussŽe | 0.3 | 0.16 | 30.2431 | V_Air_extrait
Air diffuseur - bouche | Rez de chaussŽe | 0.3 | 0.16 | 25.6003 | V_Air_extrait
Air diffuseur - bouche | Rez de chaussŽe | 0.3 | 0.16 | 6.39537 | V_Air_extrait
Air diffuseur - bouche | Rez de chaussŽe | 0.3 | 0.16 | 11.5557 | V_Air_extrait
Air diffuseur - bouche | Rez de chaussŽe | 0.3 | 0.16 | 8.39762 | V_Air_extrait
Air diffuseur - bouche | Rez de chaussŽe | 0.3 | 0.16 | 0.119216 | V_Air_extrait
Air diffuseur - bouche | Rez de chaussŽe | 0.3 | 0.16 | 1.12653 | V_Air_extrait
Air diffuseur - bouche | Rez de chaussŽe | 0.3 | 0.16 | 0.406884 | V_Air_extrait
3 x Air diffuseur - bouche | Rez de chaussŽe | 0.3 | 0.16 | 0 | V_Air_extrait
Air diffuseur - bouche | Rez de chaussŽe | 0.3 | 0.16 | 4.93734 | V_Air_extrait
Air diffuseur - bouche | Rez de chaussŽe | 0.3 | 0.16 | 16.9911 | V_Air_extrait
Air diffuseur - bouche | Rez de chaussŽe | 0.3 | 0.16 | 22.2885 | V_Air_extrait
Air diffuseur - bouche | Rez de chaussŽe | 0.3 | 0.16 | 34.5253 | V_Air_extrait
Air diffuseur - bouche | Rez de chaussŽe | 0.3 | 0.16 | 6.89241 | V_Air_extrait
Air diffuseur - bouche | Rez de chaussŽe | 0.3 | 0.16 | 5.49788 | V_Air_extrait
Air diffuseur - bouche | Rez de chaussŽe | 0.3 | 0.16 | 58.089 | V_Air_extrait
Air diffuseur - bouche | Rez de chaussŽe | 0.3 | 0.16 | 45.7414 | V_Air_extrait
Air diffuseur - bouche | Rez de chaussŽe | 0.3 | 0.16 | 40.4441 | V_Air_extrait
Air diffuseur - bouche | Rez de chaussŽe | 0.3 | 0.16 | 35.265 | V_Air_extrait
Air diffuseur - bouche | Rez de chaussŽe | 0.3 | 0.16 | 13.4571 | V_Air_extrait
Air diffuseur - bouche | Rez de chaussŽe | 0.3 | 0.16 | 8.85342 | V_Air_extrait
Air diffuseur - bouche | Rez de chaussŽe | 0.3 | 0.16 | 17.3382 | V_Air_extrait
Air diffuseur - bouche | Rez de chaussŽe | 0.3 | 0.16 | 1.7872 | V_Air_extrait
Air diffuseur - bouche | Rez de chaussŽe | 0.3 | 0.16 | 0.283511 | V_Air_extrait
Air diffuseur - bouche | Rez de chaussŽe | 0.3 | 0.16 | 7.75683 | V_Air_extrait
Air diffuseur - bouche | Rez de chaussŽe | 0.3 | 0.16 | 51.0075 | V_Air_extrait
Air diffuseur - bouche | Rez de chaussŽe | 0.3 | 0.16 | 53.9558 | V_Air_extrait
Air diffuseur - bouche | Rez de chaussŽe | 0.3 | 0.16 | 11.4333 | V_Air_extrait

# IfcFlowTerminal: Grille de sol (4)
In: Toiture
Description: Grille de sol; Group: Terminal
Pset Plancal nova - MEP - Nom: Grille de sol; Calc-Perte de charge (Pa): 0 Pa; Calc-Valeur d'equilibrage (Pa): 0 Pa; Geom-Longueur (m): 0.001 m; Calc-Debit vol (m3/s): 0.0555556 m3/s
Name | Geom-côte 1 (m) (m) | Geom-Côte 2 (m) (m) | Tech-Fluide
2 x Grille de sol | 1.2 | 1.39284 | V_Air_rejeté
2 x Grille de sol | 1.4 | 1.4 | V_Air_neuf

# IfcFlowTerminal: Lavabo (8)
Description: Lavabo; Group: Equipements sanitaires
Pset Plancal nova - MEP - Nom: Lavabo; Geom-Hauteur (m): 0.2 m; Calc-Coefficient: 1.5; Geom-Hauteur d'installation (m): 0.75 m; Geom-Largeur (m): 0.3 m; Geom-Longueur (m): 0.5 m; Calc-debit continu? (oui/non): no; Calc-Prise en compte pour les calculs?(oui/non): yes; Calc-Consommation (l/s): 0.0001 m3/s
Name | In
2 x Lavabo | R+2
2 x Lavabo | Mezzannine
2 x Lavabo | R+1
2 x Lavabo | Rez de chaussŽe

# IfcFlowTerminal: WC réservoir chasse ein saillie (8)
Description: WC réservoir chasse ein saillie; Group: Equipements sanitaires
Pset Plancal nova - MEP - Geom-Largeur (m): 0.52 m; Nom: WC réservoir chasse ein saillie; Calc-Robinet de chasse (oui/non): 0; Geom-Hauteur (m): 0.34 m; Calc-Coefficient: 0.5; Geom-Longueur (m): 0.36 m; Geom-Largeur côte mur (m): 0.3 m; Geom-Hauteur d'installation (m): 0.34 m; Calc-debit continu? (oui/non): no; Calc-Prise en compte pour les calculs?(oui/non): yes; Calc-Consommation (l/s): 0.0001 m3/s
Name | In
2 x WC réservoir chasse ein saillie | R+2
2 x WC réservoir chasse ein saillie | Mezzannine
2 x WC réservoir chasse ein saillie | R+1
2 x WC réservoir chasse ein saillie | Rez de chaussŽe

# IfcFlowTreatmentDevice: Filtre en Y (9)
In: Rez de chaussŽe
Description: Filtre en Y
Pset Plancal nova - MEP - Tech-Type de connection (filetage=2, bride=3): 3; Nom: Filtre en Y; Tech-PN: 16; Tech-Epaisseur isolant (m): 0 m
Name | Geom-Ø exterieur (m) (m) | Geom-DN | Geom-Longueur (m) (m) | Group
Filtre en Y | 0.185 | 65 | 0.185 | Eau froide
4 x Filtre en Y | 0.105 | 20 | 0.095 | Retour
Filtre en Y | 0.115 | 25 | 0.105 | Retour
2 x Filtre en Y | 0.14 | 32 | 0.12 | Retour
Filtre en Y | 0.15 | 40 | 0.13 | Retour

# IfcProxy: Manchette en toile, rect. (8)
Description: Manchette en toile, rect.; ProxyType: PRODUCT; Group: Elément
Pset Plancal nova - MEP - Geom-Côte 1 connection (m): 1.2 m; Nom: Manchette en toile, rect.
Name | Geom-Côte 2 connection (m) (m) | Calc-Perte de charge totale (Pa) (Pa) | Tech-Fluide | Calc-Debit vol (m3/s) (m3/s)
Manchette en toile, rect. | 1.3 | 22 | V_Air_rejeté
Manchette en toile, rect. | 1.2 | 164.628 | V_Air_soufflé | 2.22222
Manchette en toile, rect. | 1.3 | 0.0000452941 | V_Air_neuf | 0.0555556
Manchette en toile, rect. | 1.3 | 138.518 | V_Air_rejeté | 0.888889
Manchette en toile, rect. | 1.2 | 218.763 | V_Air_extrait | 3.83333
Manchette en toile, rect. | 1.3 | 246.515 | V_Air_extrait | 3.11111
Manchette en toile, rect. | 1.3 | 164.01 | V_Air_soufflé | 1.94444
Manchette en toile, rect. | 1.2 | 160.475 | V_Air_neuf | 1.94444

# IfcSlab: roof standard, Plafond ou dalle d'étage
In: Rez de chaussŽe
Type - PredefinedType: ROOF; Material: abc
PredefinedType: FLOOR
Pset_SlabCommon - ThermalTransmittance: 0.455; IsExternal: no
Pset nova - Archi - Description: Plafond ou dalle d'étage; Surface (m2): 1.83048 m2
